VERSION 5.8 ;
BUSBITCHARS "[]" ;
DIVIDERCHAR "/" ;

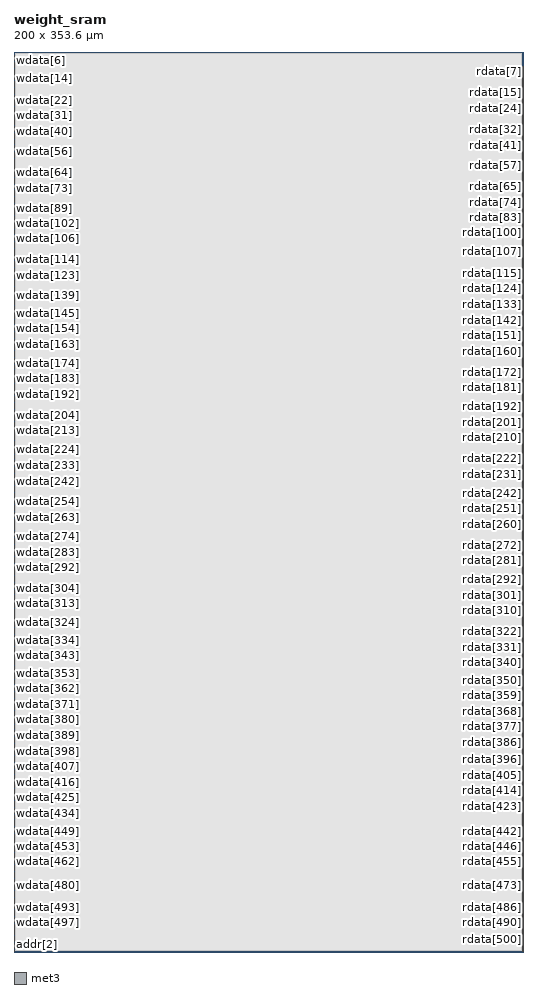
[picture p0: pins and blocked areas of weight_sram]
MACRO weight_sram
  CLASS BLOCK ;
  ORIGIN 0.000 0.000 ;
  FOREIGN weight_sram 0.000 0.000 ;
  SIZE 200.000 BY 353.600 ;
  SYMMETRY X Y ;

  PIN clk
    DIRECTION INPUT ;
    USE CLOCK ;
    PORT
      LAYER met3 ;
        RECT 0.000 0.190 0.300 0.490 ;
    END
  END clk

  PIN we
    DIRECTION INPUT ;
    USE SIGNAL ;
    PORT
      LAYER met3 ;
        RECT 0.000 0.870 0.300 1.170 ;
    END
  END we

  PIN addr[4]
    DIRECTION INPUT ;
    USE SIGNAL ;
    PORT
      LAYER met3 ;
        RECT 0.000 1.550 0.300 1.850 ;
    END
  END addr[4]

  PIN addr[3]
    DIRECTION INPUT ;
    USE SIGNAL ;
    PORT
      LAYER met3 ;
        RECT 0.000 2.230 0.300 2.530 ;
    END
  END addr[3]

  PIN addr[2]
    DIRECTION INPUT ;
    USE SIGNAL ;
    PORT
      LAYER met3 ;
        RECT 0.000 2.910 0.300 3.210 ;
    END
  END addr[2]

  PIN addr[1]
    DIRECTION INPUT ;
    USE SIGNAL ;
    PORT
      LAYER met3 ;
        RECT 0.000 3.590 0.300 3.890 ;
    END
  END addr[1]

  PIN addr[0]
    DIRECTION INPUT ;
    USE SIGNAL ;
    PORT
      LAYER met3 ;
        RECT 0.000 4.270 0.300 4.570 ;
    END
  END addr[0]

  PIN wdata[511]
    DIRECTION INPUT ;
    USE SIGNAL ;
    PORT
      LAYER met3 ;
        RECT 0.000 4.950 0.300 5.250 ;
    END
  END wdata[511]

  PIN wdata[510]
    DIRECTION INPUT ;
    USE SIGNAL ;
    PORT
      LAYER met3 ;
        RECT 0.000 5.630 0.300 5.930 ;
    END
  END wdata[510]

  PIN wdata[509]
    DIRECTION INPUT ;
    USE SIGNAL ;
    PORT
      LAYER met3 ;
        RECT 0.000 6.310 0.300 6.610 ;
    END
  END wdata[509]

  PIN wdata[508]
    DIRECTION INPUT ;
    USE SIGNAL ;
    PORT
      LAYER met3 ;
        RECT 0.000 6.990 0.300 7.290 ;
    END
  END wdata[508]

  PIN wdata[507]
    DIRECTION INPUT ;
    USE SIGNAL ;
    PORT
      LAYER met3 ;
        RECT 0.000 7.670 0.300 7.970 ;
    END
  END wdata[507]

  PIN wdata[506]
    DIRECTION INPUT ;
    USE SIGNAL ;
    PORT
      LAYER met3 ;
        RECT 0.000 8.350 0.300 8.650 ;
    END
  END wdata[506]

  PIN wdata[505]
    DIRECTION INPUT ;
    USE SIGNAL ;
    PORT
      LAYER met3 ;
        RECT 0.000 9.030 0.300 9.330 ;
    END
  END wdata[505]

  PIN wdata[504]
    DIRECTION INPUT ;
    USE SIGNAL ;
    PORT
      LAYER met3 ;
        RECT 0.000 9.710 0.300 10.010 ;
    END
  END wdata[504]

  PIN wdata[503]
    DIRECTION INPUT ;
    USE SIGNAL ;
    PORT
      LAYER met3 ;
        RECT 0.000 10.390 0.300 10.690 ;
    END
  END wdata[503]

  PIN wdata[502]
    DIRECTION INPUT ;
    USE SIGNAL ;
    PORT
      LAYER met3 ;
        RECT 0.000 11.070 0.300 11.370 ;
    END
  END wdata[502]

  PIN wdata[501]
    DIRECTION INPUT ;
    USE SIGNAL ;
    PORT
      LAYER met3 ;
        RECT 0.000 11.750 0.300 12.050 ;
    END
  END wdata[501]

  PIN wdata[500]
    DIRECTION INPUT ;
    USE SIGNAL ;
    PORT
      LAYER met3 ;
        RECT 0.000 12.430 0.300 12.730 ;
    END
  END wdata[500]

  PIN wdata[499]
    DIRECTION INPUT ;
    USE SIGNAL ;
    PORT
      LAYER met3 ;
        RECT 0.000 13.110 0.300 13.410 ;
    END
  END wdata[499]

  PIN wdata[498]
    DIRECTION INPUT ;
    USE SIGNAL ;
    PORT
      LAYER met3 ;
        RECT 0.000 13.790 0.300 14.090 ;
    END
  END wdata[498]

  PIN wdata[497]
    DIRECTION INPUT ;
    USE SIGNAL ;
    PORT
      LAYER met3 ;
        RECT 0.000 14.470 0.300 14.770 ;
    END
  END wdata[497]

  PIN wdata[496]
    DIRECTION INPUT ;
    USE SIGNAL ;
    PORT
      LAYER met3 ;
        RECT 0.000 15.150 0.300 15.450 ;
    END
  END wdata[496]

  PIN wdata[495]
    DIRECTION INPUT ;
    USE SIGNAL ;
    PORT
      LAYER met3 ;
        RECT 0.000 15.830 0.300 16.130 ;
    END
  END wdata[495]

  PIN wdata[494]
    DIRECTION INPUT ;
    USE SIGNAL ;
    PORT
      LAYER met3 ;
        RECT 0.000 16.510 0.300 16.810 ;
    END
  END wdata[494]

  PIN wdata[493]
    DIRECTION INPUT ;
    USE SIGNAL ;
    PORT
      LAYER met3 ;
        RECT 0.000 17.190 0.300 17.490 ;
    END
  END wdata[493]

  PIN wdata[492]
    DIRECTION INPUT ;
    USE SIGNAL ;
    PORT
      LAYER met3 ;
        RECT 0.000 17.870 0.300 18.170 ;
    END
  END wdata[492]

  PIN wdata[491]
    DIRECTION INPUT ;
    USE SIGNAL ;
    PORT
      LAYER met3 ;
        RECT 0.000 18.550 0.300 18.850 ;
    END
  END wdata[491]

  PIN wdata[490]
    DIRECTION INPUT ;
    USE SIGNAL ;
    PORT
      LAYER met3 ;
        RECT 0.000 19.230 0.300 19.530 ;
    END
  END wdata[490]

  PIN wdata[489]
    DIRECTION INPUT ;
    USE SIGNAL ;
    PORT
      LAYER met3 ;
        RECT 0.000 19.910 0.300 20.210 ;
    END
  END wdata[489]

  PIN wdata[488]
    DIRECTION INPUT ;
    USE SIGNAL ;
    PORT
      LAYER met3 ;
        RECT 0.000 20.590 0.300 20.890 ;
    END
  END wdata[488]

  PIN wdata[487]
    DIRECTION INPUT ;
    USE SIGNAL ;
    PORT
      LAYER met3 ;
        RECT 0.000 21.270 0.300 21.570 ;
    END
  END wdata[487]

  PIN wdata[486]
    DIRECTION INPUT ;
    USE SIGNAL ;
    PORT
      LAYER met3 ;
        RECT 0.000 21.950 0.300 22.250 ;
    END
  END wdata[486]

  PIN wdata[485]
    DIRECTION INPUT ;
    USE SIGNAL ;
    PORT
      LAYER met3 ;
        RECT 0.000 22.630 0.300 22.930 ;
    END
  END wdata[485]

  PIN wdata[484]
    DIRECTION INPUT ;
    USE SIGNAL ;
    PORT
      LAYER met3 ;
        RECT 0.000 23.310 0.300 23.610 ;
    END
  END wdata[484]

  PIN wdata[483]
    DIRECTION INPUT ;
    USE SIGNAL ;
    PORT
      LAYER met3 ;
        RECT 0.000 23.990 0.300 24.290 ;
    END
  END wdata[483]

  PIN wdata[482]
    DIRECTION INPUT ;
    USE SIGNAL ;
    PORT
      LAYER met3 ;
        RECT 0.000 24.670 0.300 24.970 ;
    END
  END wdata[482]

  PIN wdata[481]
    DIRECTION INPUT ;
    USE SIGNAL ;
    PORT
      LAYER met3 ;
        RECT 0.000 25.350 0.300 25.650 ;
    END
  END wdata[481]

  PIN wdata[480]
    DIRECTION INPUT ;
    USE SIGNAL ;
    PORT
      LAYER met3 ;
        RECT 0.000 26.030 0.300 26.330 ;
    END
  END wdata[480]

  PIN wdata[479]
    DIRECTION INPUT ;
    USE SIGNAL ;
    PORT
      LAYER met3 ;
        RECT 0.000 26.710 0.300 27.010 ;
    END
  END wdata[479]

  PIN wdata[478]
    DIRECTION INPUT ;
    USE SIGNAL ;
    PORT
      LAYER met3 ;
        RECT 0.000 27.390 0.300 27.690 ;
    END
  END wdata[478]

  PIN wdata[477]
    DIRECTION INPUT ;
    USE SIGNAL ;
    PORT
      LAYER met3 ;
        RECT 0.000 28.070 0.300 28.370 ;
    END
  END wdata[477]

  PIN wdata[476]
    DIRECTION INPUT ;
    USE SIGNAL ;
    PORT
      LAYER met3 ;
        RECT 0.000 28.750 0.300 29.050 ;
    END
  END wdata[476]

  PIN wdata[475]
    DIRECTION INPUT ;
    USE SIGNAL ;
    PORT
      LAYER met3 ;
        RECT 0.000 29.430 0.300 29.730 ;
    END
  END wdata[475]

  PIN wdata[474]
    DIRECTION INPUT ;
    USE SIGNAL ;
    PORT
      LAYER met3 ;
        RECT 0.000 30.110 0.300 30.410 ;
    END
  END wdata[474]

  PIN wdata[473]
    DIRECTION INPUT ;
    USE SIGNAL ;
    PORT
      LAYER met3 ;
        RECT 0.000 30.790 0.300 31.090 ;
    END
  END wdata[473]

  PIN wdata[472]
    DIRECTION INPUT ;
    USE SIGNAL ;
    PORT
      LAYER met3 ;
        RECT 0.000 31.470 0.300 31.770 ;
    END
  END wdata[472]

  PIN wdata[471]
    DIRECTION INPUT ;
    USE SIGNAL ;
    PORT
      LAYER met3 ;
        RECT 0.000 32.150 0.300 32.450 ;
    END
  END wdata[471]

  PIN wdata[470]
    DIRECTION INPUT ;
    USE SIGNAL ;
    PORT
      LAYER met3 ;
        RECT 0.000 32.830 0.300 33.130 ;
    END
  END wdata[470]

  PIN wdata[469]
    DIRECTION INPUT ;
    USE SIGNAL ;
    PORT
      LAYER met3 ;
        RECT 0.000 33.510 0.300 33.810 ;
    END
  END wdata[469]

  PIN wdata[468]
    DIRECTION INPUT ;
    USE SIGNAL ;
    PORT
      LAYER met3 ;
        RECT 0.000 34.190 0.300 34.490 ;
    END
  END wdata[468]

  PIN wdata[467]
    DIRECTION INPUT ;
    USE SIGNAL ;
    PORT
      LAYER met3 ;
        RECT 0.000 34.870 0.300 35.170 ;
    END
  END wdata[467]

  PIN wdata[466]
    DIRECTION INPUT ;
    USE SIGNAL ;
    PORT
      LAYER met3 ;
        RECT 0.000 35.550 0.300 35.850 ;
    END
  END wdata[466]

  PIN wdata[465]
    DIRECTION INPUT ;
    USE SIGNAL ;
    PORT
      LAYER met3 ;
        RECT 0.000 36.230 0.300 36.530 ;
    END
  END wdata[465]

  PIN wdata[464]
    DIRECTION INPUT ;
    USE SIGNAL ;
    PORT
      LAYER met3 ;
        RECT 0.000 36.910 0.300 37.210 ;
    END
  END wdata[464]

  PIN wdata[463]
    DIRECTION INPUT ;
    USE SIGNAL ;
    PORT
      LAYER met3 ;
        RECT 0.000 37.590 0.300 37.890 ;
    END
  END wdata[463]

  PIN wdata[462]
    DIRECTION INPUT ;
    USE SIGNAL ;
    PORT
      LAYER met3 ;
        RECT 0.000 38.270 0.300 38.570 ;
    END
  END wdata[462]

  PIN wdata[461]
    DIRECTION INPUT ;
    USE SIGNAL ;
    PORT
      LAYER met3 ;
        RECT 0.000 38.950 0.300 39.250 ;
    END
  END wdata[461]

  PIN wdata[460]
    DIRECTION INPUT ;
    USE SIGNAL ;
    PORT
      LAYER met3 ;
        RECT 0.000 39.630 0.300 39.930 ;
    END
  END wdata[460]

  PIN wdata[459]
    DIRECTION INPUT ;
    USE SIGNAL ;
    PORT
      LAYER met3 ;
        RECT 0.000 40.310 0.300 40.610 ;
    END
  END wdata[459]

  PIN wdata[458]
    DIRECTION INPUT ;
    USE SIGNAL ;
    PORT
      LAYER met3 ;
        RECT 0.000 40.990 0.300 41.290 ;
    END
  END wdata[458]

  PIN wdata[457]
    DIRECTION INPUT ;
    USE SIGNAL ;
    PORT
      LAYER met3 ;
        RECT 0.000 41.670 0.300 41.970 ;
    END
  END wdata[457]

  PIN wdata[456]
    DIRECTION INPUT ;
    USE SIGNAL ;
    PORT
      LAYER met3 ;
        RECT 0.000 42.350 0.300 42.650 ;
    END
  END wdata[456]

  PIN wdata[455]
    DIRECTION INPUT ;
    USE SIGNAL ;
    PORT
      LAYER met3 ;
        RECT 0.000 43.030 0.300 43.330 ;
    END
  END wdata[455]

  PIN wdata[454]
    DIRECTION INPUT ;
    USE SIGNAL ;
    PORT
      LAYER met3 ;
        RECT 0.000 43.710 0.300 44.010 ;
    END
  END wdata[454]

  PIN wdata[453]
    DIRECTION INPUT ;
    USE SIGNAL ;
    PORT
      LAYER met3 ;
        RECT 0.000 44.390 0.300 44.690 ;
    END
  END wdata[453]

  PIN wdata[452]
    DIRECTION INPUT ;
    USE SIGNAL ;
    PORT
      LAYER met3 ;
        RECT 0.000 45.070 0.300 45.370 ;
    END
  END wdata[452]

  PIN wdata[451]
    DIRECTION INPUT ;
    USE SIGNAL ;
    PORT
      LAYER met3 ;
        RECT 0.000 45.750 0.300 46.050 ;
    END
  END wdata[451]

  PIN wdata[450]
    DIRECTION INPUT ;
    USE SIGNAL ;
    PORT
      LAYER met3 ;
        RECT 0.000 46.430 0.300 46.730 ;
    END
  END wdata[450]

  PIN wdata[449]
    DIRECTION INPUT ;
    USE SIGNAL ;
    PORT
      LAYER met3 ;
        RECT 0.000 47.110 0.300 47.410 ;
    END
  END wdata[449]

  PIN wdata[448]
    DIRECTION INPUT ;
    USE SIGNAL ;
    PORT
      LAYER met3 ;
        RECT 0.000 47.790 0.300 48.090 ;
    END
  END wdata[448]

  PIN wdata[447]
    DIRECTION INPUT ;
    USE SIGNAL ;
    PORT
      LAYER met3 ;
        RECT 0.000 48.470 0.300 48.770 ;
    END
  END wdata[447]

  PIN wdata[446]
    DIRECTION INPUT ;
    USE SIGNAL ;
    PORT
      LAYER met3 ;
        RECT 0.000 49.150 0.300 49.450 ;
    END
  END wdata[446]

  PIN wdata[445]
    DIRECTION INPUT ;
    USE SIGNAL ;
    PORT
      LAYER met3 ;
        RECT 0.000 49.830 0.300 50.130 ;
    END
  END wdata[445]

  PIN wdata[444]
    DIRECTION INPUT ;
    USE SIGNAL ;
    PORT
      LAYER met3 ;
        RECT 0.000 50.510 0.300 50.810 ;
    END
  END wdata[444]

  PIN wdata[443]
    DIRECTION INPUT ;
    USE SIGNAL ;
    PORT
      LAYER met3 ;
        RECT 0.000 51.190 0.300 51.490 ;
    END
  END wdata[443]

  PIN wdata[442]
    DIRECTION INPUT ;
    USE SIGNAL ;
    PORT
      LAYER met3 ;
        RECT 0.000 51.870 0.300 52.170 ;
    END
  END wdata[442]

  PIN wdata[441]
    DIRECTION INPUT ;
    USE SIGNAL ;
    PORT
      LAYER met3 ;
        RECT 0.000 52.550 0.300 52.850 ;
    END
  END wdata[441]

  PIN wdata[440]
    DIRECTION INPUT ;
    USE SIGNAL ;
    PORT
      LAYER met3 ;
        RECT 0.000 53.230 0.300 53.530 ;
    END
  END wdata[440]

  PIN wdata[439]
    DIRECTION INPUT ;
    USE SIGNAL ;
    PORT
      LAYER met3 ;
        RECT 0.000 53.910 0.300 54.210 ;
    END
  END wdata[439]

  PIN wdata[438]
    DIRECTION INPUT ;
    USE SIGNAL ;
    PORT
      LAYER met3 ;
        RECT 0.000 54.590 0.300 54.890 ;
    END
  END wdata[438]

  PIN wdata[437]
    DIRECTION INPUT ;
    USE SIGNAL ;
    PORT
      LAYER met3 ;
        RECT 0.000 55.270 0.300 55.570 ;
    END
  END wdata[437]

  PIN wdata[436]
    DIRECTION INPUT ;
    USE SIGNAL ;
    PORT
      LAYER met3 ;
        RECT 0.000 55.950 0.300 56.250 ;
    END
  END wdata[436]

  PIN wdata[435]
    DIRECTION INPUT ;
    USE SIGNAL ;
    PORT
      LAYER met3 ;
        RECT 0.000 56.630 0.300 56.930 ;
    END
  END wdata[435]

  PIN wdata[434]
    DIRECTION INPUT ;
    USE SIGNAL ;
    PORT
      LAYER met3 ;
        RECT 0.000 57.310 0.300 57.610 ;
    END
  END wdata[434]

  PIN wdata[433]
    DIRECTION INPUT ;
    USE SIGNAL ;
    PORT
      LAYER met3 ;
        RECT 0.000 57.990 0.300 58.290 ;
    END
  END wdata[433]

  PIN wdata[432]
    DIRECTION INPUT ;
    USE SIGNAL ;
    PORT
      LAYER met3 ;
        RECT 0.000 58.670 0.300 58.970 ;
    END
  END wdata[432]

  PIN wdata[431]
    DIRECTION INPUT ;
    USE SIGNAL ;
    PORT
      LAYER met3 ;
        RECT 0.000 59.350 0.300 59.650 ;
    END
  END wdata[431]

  PIN wdata[430]
    DIRECTION INPUT ;
    USE SIGNAL ;
    PORT
      LAYER met3 ;
        RECT 0.000 60.030 0.300 60.330 ;
    END
  END wdata[430]

  PIN wdata[429]
    DIRECTION INPUT ;
    USE SIGNAL ;
    PORT
      LAYER met3 ;
        RECT 0.000 60.710 0.300 61.010 ;
    END
  END wdata[429]

  PIN wdata[428]
    DIRECTION INPUT ;
    USE SIGNAL ;
    PORT
      LAYER met3 ;
        RECT 0.000 61.390 0.300 61.690 ;
    END
  END wdata[428]

  PIN wdata[427]
    DIRECTION INPUT ;
    USE SIGNAL ;
    PORT
      LAYER met3 ;
        RECT 0.000 62.070 0.300 62.370 ;
    END
  END wdata[427]

  PIN wdata[426]
    DIRECTION INPUT ;
    USE SIGNAL ;
    PORT
      LAYER met3 ;
        RECT 0.000 62.750 0.300 63.050 ;
    END
  END wdata[426]

  PIN wdata[425]
    DIRECTION INPUT ;
    USE SIGNAL ;
    PORT
      LAYER met3 ;
        RECT 0.000 63.430 0.300 63.730 ;
    END
  END wdata[425]

  PIN wdata[424]
    DIRECTION INPUT ;
    USE SIGNAL ;
    PORT
      LAYER met3 ;
        RECT 0.000 64.110 0.300 64.410 ;
    END
  END wdata[424]

  PIN wdata[423]
    DIRECTION INPUT ;
    USE SIGNAL ;
    PORT
      LAYER met3 ;
        RECT 0.000 64.790 0.300 65.090 ;
    END
  END wdata[423]

  PIN wdata[422]
    DIRECTION INPUT ;
    USE SIGNAL ;
    PORT
      LAYER met3 ;
        RECT 0.000 65.470 0.300 65.770 ;
    END
  END wdata[422]

  PIN wdata[421]
    DIRECTION INPUT ;
    USE SIGNAL ;
    PORT
      LAYER met3 ;
        RECT 0.000 66.150 0.300 66.450 ;
    END
  END wdata[421]

  PIN wdata[420]
    DIRECTION INPUT ;
    USE SIGNAL ;
    PORT
      LAYER met3 ;
        RECT 0.000 66.830 0.300 67.130 ;
    END
  END wdata[420]

  PIN wdata[419]
    DIRECTION INPUT ;
    USE SIGNAL ;
    PORT
      LAYER met3 ;
        RECT 0.000 67.510 0.300 67.810 ;
    END
  END wdata[419]

  PIN wdata[418]
    DIRECTION INPUT ;
    USE SIGNAL ;
    PORT
      LAYER met3 ;
        RECT 0.000 68.190 0.300 68.490 ;
    END
  END wdata[418]

  PIN wdata[417]
    DIRECTION INPUT ;
    USE SIGNAL ;
    PORT
      LAYER met3 ;
        RECT 0.000 68.870 0.300 69.170 ;
    END
  END wdata[417]

  PIN wdata[416]
    DIRECTION INPUT ;
    USE SIGNAL ;
    PORT
      LAYER met3 ;
        RECT 0.000 69.550 0.300 69.850 ;
    END
  END wdata[416]

  PIN wdata[415]
    DIRECTION INPUT ;
    USE SIGNAL ;
    PORT
      LAYER met3 ;
        RECT 0.000 70.230 0.300 70.530 ;
    END
  END wdata[415]

  PIN wdata[414]
    DIRECTION INPUT ;
    USE SIGNAL ;
    PORT
      LAYER met3 ;
        RECT 0.000 70.910 0.300 71.210 ;
    END
  END wdata[414]

  PIN wdata[413]
    DIRECTION INPUT ;
    USE SIGNAL ;
    PORT
      LAYER met3 ;
        RECT 0.000 71.590 0.300 71.890 ;
    END
  END wdata[413]

  PIN wdata[412]
    DIRECTION INPUT ;
    USE SIGNAL ;
    PORT
      LAYER met3 ;
        RECT 0.000 72.270 0.300 72.570 ;
    END
  END wdata[412]

  PIN wdata[411]
    DIRECTION INPUT ;
    USE SIGNAL ;
    PORT
      LAYER met3 ;
        RECT 0.000 72.950 0.300 73.250 ;
    END
  END wdata[411]

  PIN wdata[410]
    DIRECTION INPUT ;
    USE SIGNAL ;
    PORT
      LAYER met3 ;
        RECT 0.000 73.630 0.300 73.930 ;
    END
  END wdata[410]

  PIN wdata[409]
    DIRECTION INPUT ;
    USE SIGNAL ;
    PORT
      LAYER met3 ;
        RECT 0.000 74.310 0.300 74.610 ;
    END
  END wdata[409]

  PIN wdata[408]
    DIRECTION INPUT ;
    USE SIGNAL ;
    PORT
      LAYER met3 ;
        RECT 0.000 74.990 0.300 75.290 ;
    END
  END wdata[408]

  PIN wdata[407]
    DIRECTION INPUT ;
    USE SIGNAL ;
    PORT
      LAYER met3 ;
        RECT 0.000 75.670 0.300 75.970 ;
    END
  END wdata[407]

  PIN wdata[406]
    DIRECTION INPUT ;
    USE SIGNAL ;
    PORT
      LAYER met3 ;
        RECT 0.000 76.350 0.300 76.650 ;
    END
  END wdata[406]

  PIN wdata[405]
    DIRECTION INPUT ;
    USE SIGNAL ;
    PORT
      LAYER met3 ;
        RECT 0.000 77.030 0.300 77.330 ;
    END
  END wdata[405]

  PIN wdata[404]
    DIRECTION INPUT ;
    USE SIGNAL ;
    PORT
      LAYER met3 ;
        RECT 0.000 77.710 0.300 78.010 ;
    END
  END wdata[404]

  PIN wdata[403]
    DIRECTION INPUT ;
    USE SIGNAL ;
    PORT
      LAYER met3 ;
        RECT 0.000 78.390 0.300 78.690 ;
    END
  END wdata[403]

  PIN wdata[402]
    DIRECTION INPUT ;
    USE SIGNAL ;
    PORT
      LAYER met3 ;
        RECT 0.000 79.070 0.300 79.370 ;
    END
  END wdata[402]

  PIN wdata[401]
    DIRECTION INPUT ;
    USE SIGNAL ;
    PORT
      LAYER met3 ;
        RECT 0.000 79.750 0.300 80.050 ;
    END
  END wdata[401]

  PIN wdata[400]
    DIRECTION INPUT ;
    USE SIGNAL ;
    PORT
      LAYER met3 ;
        RECT 0.000 80.430 0.300 80.730 ;
    END
  END wdata[400]

  PIN wdata[399]
    DIRECTION INPUT ;
    USE SIGNAL ;
    PORT
      LAYER met3 ;
        RECT 0.000 81.110 0.300 81.410 ;
    END
  END wdata[399]

  PIN wdata[398]
    DIRECTION INPUT ;
    USE SIGNAL ;
    PORT
      LAYER met3 ;
        RECT 0.000 81.790 0.300 82.090 ;
    END
  END wdata[398]

  PIN wdata[397]
    DIRECTION INPUT ;
    USE SIGNAL ;
    PORT
      LAYER met3 ;
        RECT 0.000 82.470 0.300 82.770 ;
    END
  END wdata[397]

  PIN wdata[396]
    DIRECTION INPUT ;
    USE SIGNAL ;
    PORT
      LAYER met3 ;
        RECT 0.000 83.150 0.300 83.450 ;
    END
  END wdata[396]

  PIN wdata[395]
    DIRECTION INPUT ;
    USE SIGNAL ;
    PORT
      LAYER met3 ;
        RECT 0.000 83.830 0.300 84.130 ;
    END
  END wdata[395]

  PIN wdata[394]
    DIRECTION INPUT ;
    USE SIGNAL ;
    PORT
      LAYER met3 ;
        RECT 0.000 84.510 0.300 84.810 ;
    END
  END wdata[394]

  PIN wdata[393]
    DIRECTION INPUT ;
    USE SIGNAL ;
    PORT
      LAYER met3 ;
        RECT 0.000 85.190 0.300 85.490 ;
    END
  END wdata[393]

  PIN wdata[392]
    DIRECTION INPUT ;
    USE SIGNAL ;
    PORT
      LAYER met3 ;
        RECT 0.000 85.870 0.300 86.170 ;
    END
  END wdata[392]

  PIN wdata[391]
    DIRECTION INPUT ;
    USE SIGNAL ;
    PORT
      LAYER met3 ;
        RECT 0.000 86.550 0.300 86.850 ;
    END
  END wdata[391]

  PIN wdata[390]
    DIRECTION INPUT ;
    USE SIGNAL ;
    PORT
      LAYER met3 ;
        RECT 0.000 87.230 0.300 87.530 ;
    END
  END wdata[390]

  PIN wdata[389]
    DIRECTION INPUT ;
    USE SIGNAL ;
    PORT
      LAYER met3 ;
        RECT 0.000 87.910 0.300 88.210 ;
    END
  END wdata[389]

  PIN wdata[388]
    DIRECTION INPUT ;
    USE SIGNAL ;
    PORT
      LAYER met3 ;
        RECT 0.000 88.590 0.300 88.890 ;
    END
  END wdata[388]

  PIN wdata[387]
    DIRECTION INPUT ;
    USE SIGNAL ;
    PORT
      LAYER met3 ;
        RECT 0.000 89.270 0.300 89.570 ;
    END
  END wdata[387]

  PIN wdata[386]
    DIRECTION INPUT ;
    USE SIGNAL ;
    PORT
      LAYER met3 ;
        RECT 0.000 89.950 0.300 90.250 ;
    END
  END wdata[386]

  PIN wdata[385]
    DIRECTION INPUT ;
    USE SIGNAL ;
    PORT
      LAYER met3 ;
        RECT 0.000 90.630 0.300 90.930 ;
    END
  END wdata[385]

  PIN wdata[384]
    DIRECTION INPUT ;
    USE SIGNAL ;
    PORT
      LAYER met3 ;
        RECT 0.000 91.310 0.300 91.610 ;
    END
  END wdata[384]

  PIN wdata[383]
    DIRECTION INPUT ;
    USE SIGNAL ;
    PORT
      LAYER met3 ;
        RECT 0.000 91.990 0.300 92.290 ;
    END
  END wdata[383]

  PIN wdata[382]
    DIRECTION INPUT ;
    USE SIGNAL ;
    PORT
      LAYER met3 ;
        RECT 0.000 92.670 0.300 92.970 ;
    END
  END wdata[382]

  PIN wdata[381]
    DIRECTION INPUT ;
    USE SIGNAL ;
    PORT
      LAYER met3 ;
        RECT 0.000 93.350 0.300 93.650 ;
    END
  END wdata[381]

  PIN wdata[380]
    DIRECTION INPUT ;
    USE SIGNAL ;
    PORT
      LAYER met3 ;
        RECT 0.000 94.030 0.300 94.330 ;
    END
  END wdata[380]

  PIN wdata[379]
    DIRECTION INPUT ;
    USE SIGNAL ;
    PORT
      LAYER met3 ;
        RECT 0.000 94.710 0.300 95.010 ;
    END
  END wdata[379]

  PIN wdata[378]
    DIRECTION INPUT ;
    USE SIGNAL ;
    PORT
      LAYER met3 ;
        RECT 0.000 95.390 0.300 95.690 ;
    END
  END wdata[378]

  PIN wdata[377]
    DIRECTION INPUT ;
    USE SIGNAL ;
    PORT
      LAYER met3 ;
        RECT 0.000 96.070 0.300 96.370 ;
    END
  END wdata[377]

  PIN wdata[376]
    DIRECTION INPUT ;
    USE SIGNAL ;
    PORT
      LAYER met3 ;
        RECT 0.000 96.750 0.300 97.050 ;
    END
  END wdata[376]

  PIN wdata[375]
    DIRECTION INPUT ;
    USE SIGNAL ;
    PORT
      LAYER met3 ;
        RECT 0.000 97.430 0.300 97.730 ;
    END
  END wdata[375]

  PIN wdata[374]
    DIRECTION INPUT ;
    USE SIGNAL ;
    PORT
      LAYER met3 ;
        RECT 0.000 98.110 0.300 98.410 ;
    END
  END wdata[374]

  PIN wdata[373]
    DIRECTION INPUT ;
    USE SIGNAL ;
    PORT
      LAYER met3 ;
        RECT 0.000 98.790 0.300 99.090 ;
    END
  END wdata[373]

  PIN wdata[372]
    DIRECTION INPUT ;
    USE SIGNAL ;
    PORT
      LAYER met3 ;
        RECT 0.000 99.470 0.300 99.770 ;
    END
  END wdata[372]

  PIN wdata[371]
    DIRECTION INPUT ;
    USE SIGNAL ;
    PORT
      LAYER met3 ;
        RECT 0.000 100.150 0.300 100.450 ;
    END
  END wdata[371]

  PIN wdata[370]
    DIRECTION INPUT ;
    USE SIGNAL ;
    PORT
      LAYER met3 ;
        RECT 0.000 100.830 0.300 101.130 ;
    END
  END wdata[370]

  PIN wdata[369]
    DIRECTION INPUT ;
    USE SIGNAL ;
    PORT
      LAYER met3 ;
        RECT 0.000 101.510 0.300 101.810 ;
    END
  END wdata[369]

  PIN wdata[368]
    DIRECTION INPUT ;
    USE SIGNAL ;
    PORT
      LAYER met3 ;
        RECT 0.000 102.190 0.300 102.490 ;
    END
  END wdata[368]

  PIN wdata[367]
    DIRECTION INPUT ;
    USE SIGNAL ;
    PORT
      LAYER met3 ;
        RECT 0.000 102.870 0.300 103.170 ;
    END
  END wdata[367]

  PIN wdata[366]
    DIRECTION INPUT ;
    USE SIGNAL ;
    PORT
      LAYER met3 ;
        RECT 0.000 103.550 0.300 103.850 ;
    END
  END wdata[366]

  PIN wdata[365]
    DIRECTION INPUT ;
    USE SIGNAL ;
    PORT
      LAYER met3 ;
        RECT 0.000 104.230 0.300 104.530 ;
    END
  END wdata[365]

  PIN wdata[364]
    DIRECTION INPUT ;
    USE SIGNAL ;
    PORT
      LAYER met3 ;
        RECT 0.000 104.910 0.300 105.210 ;
    END
  END wdata[364]

  PIN wdata[363]
    DIRECTION INPUT ;
    USE SIGNAL ;
    PORT
      LAYER met3 ;
        RECT 0.000 105.590 0.300 105.890 ;
    END
  END wdata[363]

  PIN wdata[362]
    DIRECTION INPUT ;
    USE SIGNAL ;
    PORT
      LAYER met3 ;
        RECT 0.000 106.270 0.300 106.570 ;
    END
  END wdata[362]

  PIN wdata[361]
    DIRECTION INPUT ;
    USE SIGNAL ;
    PORT
      LAYER met3 ;
        RECT 0.000 106.950 0.300 107.250 ;
    END
  END wdata[361]

  PIN wdata[360]
    DIRECTION INPUT ;
    USE SIGNAL ;
    PORT
      LAYER met3 ;
        RECT 0.000 107.630 0.300 107.930 ;
    END
  END wdata[360]

  PIN wdata[359]
    DIRECTION INPUT ;
    USE SIGNAL ;
    PORT
      LAYER met3 ;
        RECT 0.000 108.310 0.300 108.610 ;
    END
  END wdata[359]

  PIN wdata[358]
    DIRECTION INPUT ;
    USE SIGNAL ;
    PORT
      LAYER met3 ;
        RECT 0.000 108.990 0.300 109.290 ;
    END
  END wdata[358]

  PIN wdata[357]
    DIRECTION INPUT ;
    USE SIGNAL ;
    PORT
      LAYER met3 ;
        RECT 0.000 109.670 0.300 109.970 ;
    END
  END wdata[357]

  PIN wdata[356]
    DIRECTION INPUT ;
    USE SIGNAL ;
    PORT
      LAYER met3 ;
        RECT 0.000 110.350 0.300 110.650 ;
    END
  END wdata[356]

  PIN wdata[355]
    DIRECTION INPUT ;
    USE SIGNAL ;
    PORT
      LAYER met3 ;
        RECT 0.000 111.030 0.300 111.330 ;
    END
  END wdata[355]

  PIN wdata[354]
    DIRECTION INPUT ;
    USE SIGNAL ;
    PORT
      LAYER met3 ;
        RECT 0.000 111.710 0.300 112.010 ;
    END
  END wdata[354]

  PIN wdata[353]
    DIRECTION INPUT ;
    USE SIGNAL ;
    PORT
      LAYER met3 ;
        RECT 0.000 112.390 0.300 112.690 ;
    END
  END wdata[353]

  PIN wdata[352]
    DIRECTION INPUT ;
    USE SIGNAL ;
    PORT
      LAYER met3 ;
        RECT 0.000 113.070 0.300 113.370 ;
    END
  END wdata[352]

  PIN wdata[351]
    DIRECTION INPUT ;
    USE SIGNAL ;
    PORT
      LAYER met3 ;
        RECT 0.000 113.750 0.300 114.050 ;
    END
  END wdata[351]

  PIN wdata[350]
    DIRECTION INPUT ;
    USE SIGNAL ;
    PORT
      LAYER met3 ;
        RECT 0.000 114.430 0.300 114.730 ;
    END
  END wdata[350]

  PIN wdata[349]
    DIRECTION INPUT ;
    USE SIGNAL ;
    PORT
      LAYER met3 ;
        RECT 0.000 115.110 0.300 115.410 ;
    END
  END wdata[349]

  PIN wdata[348]
    DIRECTION INPUT ;
    USE SIGNAL ;
    PORT
      LAYER met3 ;
        RECT 0.000 115.790 0.300 116.090 ;
    END
  END wdata[348]

  PIN wdata[347]
    DIRECTION INPUT ;
    USE SIGNAL ;
    PORT
      LAYER met3 ;
        RECT 0.000 116.470 0.300 116.770 ;
    END
  END wdata[347]

  PIN wdata[346]
    DIRECTION INPUT ;
    USE SIGNAL ;
    PORT
      LAYER met3 ;
        RECT 0.000 117.150 0.300 117.450 ;
    END
  END wdata[346]

  PIN wdata[345]
    DIRECTION INPUT ;
    USE SIGNAL ;
    PORT
      LAYER met3 ;
        RECT 0.000 117.830 0.300 118.130 ;
    END
  END wdata[345]

  PIN wdata[344]
    DIRECTION INPUT ;
    USE SIGNAL ;
    PORT
      LAYER met3 ;
        RECT 0.000 118.510 0.300 118.810 ;
    END
  END wdata[344]

  PIN wdata[343]
    DIRECTION INPUT ;
    USE SIGNAL ;
    PORT
      LAYER met3 ;
        RECT 0.000 119.190 0.300 119.490 ;
    END
  END wdata[343]

  PIN wdata[342]
    DIRECTION INPUT ;
    USE SIGNAL ;
    PORT
      LAYER met3 ;
        RECT 0.000 119.870 0.300 120.170 ;
    END
  END wdata[342]

  PIN wdata[341]
    DIRECTION INPUT ;
    USE SIGNAL ;
    PORT
      LAYER met3 ;
        RECT 0.000 120.550 0.300 120.850 ;
    END
  END wdata[341]

  PIN wdata[340]
    DIRECTION INPUT ;
    USE SIGNAL ;
    PORT
      LAYER met3 ;
        RECT 0.000 121.230 0.300 121.530 ;
    END
  END wdata[340]

  PIN wdata[339]
    DIRECTION INPUT ;
    USE SIGNAL ;
    PORT
      LAYER met3 ;
        RECT 0.000 121.910 0.300 122.210 ;
    END
  END wdata[339]

  PIN wdata[338]
    DIRECTION INPUT ;
    USE SIGNAL ;
    PORT
      LAYER met3 ;
        RECT 0.000 122.590 0.300 122.890 ;
    END
  END wdata[338]

  PIN wdata[337]
    DIRECTION INPUT ;
    USE SIGNAL ;
    PORT
      LAYER met3 ;
        RECT 0.000 123.270 0.300 123.570 ;
    END
  END wdata[337]

  PIN wdata[336]
    DIRECTION INPUT ;
    USE SIGNAL ;
    PORT
      LAYER met3 ;
        RECT 0.000 123.950 0.300 124.250 ;
    END
  END wdata[336]

  PIN wdata[335]
    DIRECTION INPUT ;
    USE SIGNAL ;
    PORT
      LAYER met3 ;
        RECT 0.000 124.630 0.300 124.930 ;
    END
  END wdata[335]

  PIN wdata[334]
    DIRECTION INPUT ;
    USE SIGNAL ;
    PORT
      LAYER met3 ;
        RECT 0.000 125.310 0.300 125.610 ;
    END
  END wdata[334]

  PIN wdata[333]
    DIRECTION INPUT ;
    USE SIGNAL ;
    PORT
      LAYER met3 ;
        RECT 0.000 125.990 0.300 126.290 ;
    END
  END wdata[333]

  PIN wdata[332]
    DIRECTION INPUT ;
    USE SIGNAL ;
    PORT
      LAYER met3 ;
        RECT 0.000 126.670 0.300 126.970 ;
    END
  END wdata[332]

  PIN wdata[331]
    DIRECTION INPUT ;
    USE SIGNAL ;
    PORT
      LAYER met3 ;
        RECT 0.000 127.350 0.300 127.650 ;
    END
  END wdata[331]

  PIN wdata[330]
    DIRECTION INPUT ;
    USE SIGNAL ;
    PORT
      LAYER met3 ;
        RECT 0.000 128.030 0.300 128.330 ;
    END
  END wdata[330]

  PIN wdata[329]
    DIRECTION INPUT ;
    USE SIGNAL ;
    PORT
      LAYER met3 ;
        RECT 0.000 128.710 0.300 129.010 ;
    END
  END wdata[329]

  PIN wdata[328]
    DIRECTION INPUT ;
    USE SIGNAL ;
    PORT
      LAYER met3 ;
        RECT 0.000 129.390 0.300 129.690 ;
    END
  END wdata[328]

  PIN wdata[327]
    DIRECTION INPUT ;
    USE SIGNAL ;
    PORT
      LAYER met3 ;
        RECT 0.000 130.070 0.300 130.370 ;
    END
  END wdata[327]

  PIN wdata[326]
    DIRECTION INPUT ;
    USE SIGNAL ;
    PORT
      LAYER met3 ;
        RECT 0.000 130.750 0.300 131.050 ;
    END
  END wdata[326]

  PIN wdata[325]
    DIRECTION INPUT ;
    USE SIGNAL ;
    PORT
      LAYER met3 ;
        RECT 0.000 131.430 0.300 131.730 ;
    END
  END wdata[325]

  PIN wdata[324]
    DIRECTION INPUT ;
    USE SIGNAL ;
    PORT
      LAYER met3 ;
        RECT 0.000 132.110 0.300 132.410 ;
    END
  END wdata[324]

  PIN wdata[323]
    DIRECTION INPUT ;
    USE SIGNAL ;
    PORT
      LAYER met3 ;
        RECT 0.000 132.790 0.300 133.090 ;
    END
  END wdata[323]

  PIN wdata[322]
    DIRECTION INPUT ;
    USE SIGNAL ;
    PORT
      LAYER met3 ;
        RECT 0.000 133.470 0.300 133.770 ;
    END
  END wdata[322]

  PIN wdata[321]
    DIRECTION INPUT ;
    USE SIGNAL ;
    PORT
      LAYER met3 ;
        RECT 0.000 134.150 0.300 134.450 ;
    END
  END wdata[321]

  PIN wdata[320]
    DIRECTION INPUT ;
    USE SIGNAL ;
    PORT
      LAYER met3 ;
        RECT 0.000 134.830 0.300 135.130 ;
    END
  END wdata[320]

  PIN wdata[319]
    DIRECTION INPUT ;
    USE SIGNAL ;
    PORT
      LAYER met3 ;
        RECT 0.000 135.510 0.300 135.810 ;
    END
  END wdata[319]

  PIN wdata[318]
    DIRECTION INPUT ;
    USE SIGNAL ;
    PORT
      LAYER met3 ;
        RECT 0.000 136.190 0.300 136.490 ;
    END
  END wdata[318]

  PIN wdata[317]
    DIRECTION INPUT ;
    USE SIGNAL ;
    PORT
      LAYER met3 ;
        RECT 0.000 136.870 0.300 137.170 ;
    END
  END wdata[317]

  PIN wdata[316]
    DIRECTION INPUT ;
    USE SIGNAL ;
    PORT
      LAYER met3 ;
        RECT 0.000 137.550 0.300 137.850 ;
    END
  END wdata[316]

  PIN wdata[315]
    DIRECTION INPUT ;
    USE SIGNAL ;
    PORT
      LAYER met3 ;
        RECT 0.000 138.230 0.300 138.530 ;
    END
  END wdata[315]

  PIN wdata[314]
    DIRECTION INPUT ;
    USE SIGNAL ;
    PORT
      LAYER met3 ;
        RECT 0.000 138.910 0.300 139.210 ;
    END
  END wdata[314]

  PIN wdata[313]
    DIRECTION INPUT ;
    USE SIGNAL ;
    PORT
      LAYER met3 ;
        RECT 0.000 139.590 0.300 139.890 ;
    END
  END wdata[313]

  PIN wdata[312]
    DIRECTION INPUT ;
    USE SIGNAL ;
    PORT
      LAYER met3 ;
        RECT 0.000 140.270 0.300 140.570 ;
    END
  END wdata[312]

  PIN wdata[311]
    DIRECTION INPUT ;
    USE SIGNAL ;
    PORT
      LAYER met3 ;
        RECT 0.000 140.950 0.300 141.250 ;
    END
  END wdata[311]

  PIN wdata[310]
    DIRECTION INPUT ;
    USE SIGNAL ;
    PORT
      LAYER met3 ;
        RECT 0.000 141.630 0.300 141.930 ;
    END
  END wdata[310]

  PIN wdata[309]
    DIRECTION INPUT ;
    USE SIGNAL ;
    PORT
      LAYER met3 ;
        RECT 0.000 142.310 0.300 142.610 ;
    END
  END wdata[309]

  PIN wdata[308]
    DIRECTION INPUT ;
    USE SIGNAL ;
    PORT
      LAYER met3 ;
        RECT 0.000 142.990 0.300 143.290 ;
    END
  END wdata[308]

  PIN wdata[307]
    DIRECTION INPUT ;
    USE SIGNAL ;
    PORT
      LAYER met3 ;
        RECT 0.000 143.670 0.300 143.970 ;
    END
  END wdata[307]

  PIN wdata[306]
    DIRECTION INPUT ;
    USE SIGNAL ;
    PORT
      LAYER met3 ;
        RECT 0.000 144.350 0.300 144.650 ;
    END
  END wdata[306]

  PIN wdata[305]
    DIRECTION INPUT ;
    USE SIGNAL ;
    PORT
      LAYER met3 ;
        RECT 0.000 145.030 0.300 145.330 ;
    END
  END wdata[305]

  PIN wdata[304]
    DIRECTION INPUT ;
    USE SIGNAL ;
    PORT
      LAYER met3 ;
        RECT 0.000 145.710 0.300 146.010 ;
    END
  END wdata[304]

  PIN wdata[303]
    DIRECTION INPUT ;
    USE SIGNAL ;
    PORT
      LAYER met3 ;
        RECT 0.000 146.390 0.300 146.690 ;
    END
  END wdata[303]

  PIN wdata[302]
    DIRECTION INPUT ;
    USE SIGNAL ;
    PORT
      LAYER met3 ;
        RECT 0.000 147.070 0.300 147.370 ;
    END
  END wdata[302]

  PIN wdata[301]
    DIRECTION INPUT ;
    USE SIGNAL ;
    PORT
      LAYER met3 ;
        RECT 0.000 147.750 0.300 148.050 ;
    END
  END wdata[301]

  PIN wdata[300]
    DIRECTION INPUT ;
    USE SIGNAL ;
    PORT
      LAYER met3 ;
        RECT 0.000 148.430 0.300 148.730 ;
    END
  END wdata[300]

  PIN wdata[299]
    DIRECTION INPUT ;
    USE SIGNAL ;
    PORT
      LAYER met3 ;
        RECT 0.000 149.110 0.300 149.410 ;
    END
  END wdata[299]

  PIN wdata[298]
    DIRECTION INPUT ;
    USE SIGNAL ;
    PORT
      LAYER met3 ;
        RECT 0.000 149.790 0.300 150.090 ;
    END
  END wdata[298]

  PIN wdata[297]
    DIRECTION INPUT ;
    USE SIGNAL ;
    PORT
      LAYER met3 ;
        RECT 0.000 150.470 0.300 150.770 ;
    END
  END wdata[297]

  PIN wdata[296]
    DIRECTION INPUT ;
    USE SIGNAL ;
    PORT
      LAYER met3 ;
        RECT 0.000 151.150 0.300 151.450 ;
    END
  END wdata[296]

  PIN wdata[295]
    DIRECTION INPUT ;
    USE SIGNAL ;
    PORT
      LAYER met3 ;
        RECT 0.000 151.830 0.300 152.130 ;
    END
  END wdata[295]

  PIN wdata[294]
    DIRECTION INPUT ;
    USE SIGNAL ;
    PORT
      LAYER met3 ;
        RECT 0.000 152.510 0.300 152.810 ;
    END
  END wdata[294]

  PIN wdata[293]
    DIRECTION INPUT ;
    USE SIGNAL ;
    PORT
      LAYER met3 ;
        RECT 0.000 153.190 0.300 153.490 ;
    END
  END wdata[293]

  PIN wdata[292]
    DIRECTION INPUT ;
    USE SIGNAL ;
    PORT
      LAYER met3 ;
        RECT 0.000 153.870 0.300 154.170 ;
    END
  END wdata[292]

  PIN wdata[291]
    DIRECTION INPUT ;
    USE SIGNAL ;
    PORT
      LAYER met3 ;
        RECT 0.000 154.550 0.300 154.850 ;
    END
  END wdata[291]

  PIN wdata[290]
    DIRECTION INPUT ;
    USE SIGNAL ;
    PORT
      LAYER met3 ;
        RECT 0.000 155.230 0.300 155.530 ;
    END
  END wdata[290]

  PIN wdata[289]
    DIRECTION INPUT ;
    USE SIGNAL ;
    PORT
      LAYER met3 ;
        RECT 0.000 155.910 0.300 156.210 ;
    END
  END wdata[289]

  PIN wdata[288]
    DIRECTION INPUT ;
    USE SIGNAL ;
    PORT
      LAYER met3 ;
        RECT 0.000 156.590 0.300 156.890 ;
    END
  END wdata[288]

  PIN wdata[287]
    DIRECTION INPUT ;
    USE SIGNAL ;
    PORT
      LAYER met3 ;
        RECT 0.000 157.270 0.300 157.570 ;
    END
  END wdata[287]

  PIN wdata[286]
    DIRECTION INPUT ;
    USE SIGNAL ;
    PORT
      LAYER met3 ;
        RECT 0.000 157.950 0.300 158.250 ;
    END
  END wdata[286]

  PIN wdata[285]
    DIRECTION INPUT ;
    USE SIGNAL ;
    PORT
      LAYER met3 ;
        RECT 0.000 158.630 0.300 158.930 ;
    END
  END wdata[285]

  PIN wdata[284]
    DIRECTION INPUT ;
    USE SIGNAL ;
    PORT
      LAYER met3 ;
        RECT 0.000 159.310 0.300 159.610 ;
    END
  END wdata[284]

  PIN wdata[283]
    DIRECTION INPUT ;
    USE SIGNAL ;
    PORT
      LAYER met3 ;
        RECT 0.000 159.990 0.300 160.290 ;
    END
  END wdata[283]

  PIN wdata[282]
    DIRECTION INPUT ;
    USE SIGNAL ;
    PORT
      LAYER met3 ;
        RECT 0.000 160.670 0.300 160.970 ;
    END
  END wdata[282]

  PIN wdata[281]
    DIRECTION INPUT ;
    USE SIGNAL ;
    PORT
      LAYER met3 ;
        RECT 0.000 161.350 0.300 161.650 ;
    END
  END wdata[281]

  PIN wdata[280]
    DIRECTION INPUT ;
    USE SIGNAL ;
    PORT
      LAYER met3 ;
        RECT 0.000 162.030 0.300 162.330 ;
    END
  END wdata[280]

  PIN wdata[279]
    DIRECTION INPUT ;
    USE SIGNAL ;
    PORT
      LAYER met3 ;
        RECT 0.000 162.710 0.300 163.010 ;
    END
  END wdata[279]

  PIN wdata[278]
    DIRECTION INPUT ;
    USE SIGNAL ;
    PORT
      LAYER met3 ;
        RECT 0.000 163.390 0.300 163.690 ;
    END
  END wdata[278]

  PIN wdata[277]
    DIRECTION INPUT ;
    USE SIGNAL ;
    PORT
      LAYER met3 ;
        RECT 0.000 164.070 0.300 164.370 ;
    END
  END wdata[277]

  PIN wdata[276]
    DIRECTION INPUT ;
    USE SIGNAL ;
    PORT
      LAYER met3 ;
        RECT 0.000 164.750 0.300 165.050 ;
    END
  END wdata[276]

  PIN wdata[275]
    DIRECTION INPUT ;
    USE SIGNAL ;
    PORT
      LAYER met3 ;
        RECT 0.000 165.430 0.300 165.730 ;
    END
  END wdata[275]

  PIN wdata[274]
    DIRECTION INPUT ;
    USE SIGNAL ;
    PORT
      LAYER met3 ;
        RECT 0.000 166.110 0.300 166.410 ;
    END
  END wdata[274]

  PIN wdata[273]
    DIRECTION INPUT ;
    USE SIGNAL ;
    PORT
      LAYER met3 ;
        RECT 0.000 166.790 0.300 167.090 ;
    END
  END wdata[273]

  PIN wdata[272]
    DIRECTION INPUT ;
    USE SIGNAL ;
    PORT
      LAYER met3 ;
        RECT 0.000 167.470 0.300 167.770 ;
    END
  END wdata[272]

  PIN wdata[271]
    DIRECTION INPUT ;
    USE SIGNAL ;
    PORT
      LAYER met3 ;
        RECT 0.000 168.150 0.300 168.450 ;
    END
  END wdata[271]

  PIN wdata[270]
    DIRECTION INPUT ;
    USE SIGNAL ;
    PORT
      LAYER met3 ;
        RECT 0.000 168.830 0.300 169.130 ;
    END
  END wdata[270]

  PIN wdata[269]
    DIRECTION INPUT ;
    USE SIGNAL ;
    PORT
      LAYER met3 ;
        RECT 0.000 169.510 0.300 169.810 ;
    END
  END wdata[269]

  PIN wdata[268]
    DIRECTION INPUT ;
    USE SIGNAL ;
    PORT
      LAYER met3 ;
        RECT 0.000 170.190 0.300 170.490 ;
    END
  END wdata[268]

  PIN wdata[267]
    DIRECTION INPUT ;
    USE SIGNAL ;
    PORT
      LAYER met3 ;
        RECT 0.000 170.870 0.300 171.170 ;
    END
  END wdata[267]

  PIN wdata[266]
    DIRECTION INPUT ;
    USE SIGNAL ;
    PORT
      LAYER met3 ;
        RECT 0.000 171.550 0.300 171.850 ;
    END
  END wdata[266]

  PIN wdata[265]
    DIRECTION INPUT ;
    USE SIGNAL ;
    PORT
      LAYER met3 ;
        RECT 0.000 172.230 0.300 172.530 ;
    END
  END wdata[265]

  PIN wdata[264]
    DIRECTION INPUT ;
    USE SIGNAL ;
    PORT
      LAYER met3 ;
        RECT 0.000 172.910 0.300 173.210 ;
    END
  END wdata[264]

  PIN wdata[263]
    DIRECTION INPUT ;
    USE SIGNAL ;
    PORT
      LAYER met3 ;
        RECT 0.000 173.590 0.300 173.890 ;
    END
  END wdata[263]

  PIN wdata[262]
    DIRECTION INPUT ;
    USE SIGNAL ;
    PORT
      LAYER met3 ;
        RECT 0.000 174.270 0.300 174.570 ;
    END
  END wdata[262]

  PIN wdata[261]
    DIRECTION INPUT ;
    USE SIGNAL ;
    PORT
      LAYER met3 ;
        RECT 0.000 174.950 0.300 175.250 ;
    END
  END wdata[261]

  PIN wdata[260]
    DIRECTION INPUT ;
    USE SIGNAL ;
    PORT
      LAYER met3 ;
        RECT 0.000 175.630 0.300 175.930 ;
    END
  END wdata[260]

  PIN wdata[259]
    DIRECTION INPUT ;
    USE SIGNAL ;
    PORT
      LAYER met3 ;
        RECT 0.000 176.310 0.300 176.610 ;
    END
  END wdata[259]

  PIN wdata[258]
    DIRECTION INPUT ;
    USE SIGNAL ;
    PORT
      LAYER met3 ;
        RECT 0.000 176.990 0.300 177.290 ;
    END
  END wdata[258]

  PIN wdata[257]
    DIRECTION INPUT ;
    USE SIGNAL ;
    PORT
      LAYER met3 ;
        RECT 0.000 177.670 0.300 177.970 ;
    END
  END wdata[257]

  PIN wdata[256]
    DIRECTION INPUT ;
    USE SIGNAL ;
    PORT
      LAYER met3 ;
        RECT 0.000 178.350 0.300 178.650 ;
    END
  END wdata[256]

  PIN wdata[255]
    DIRECTION INPUT ;
    USE SIGNAL ;
    PORT
      LAYER met3 ;
        RECT 0.000 179.030 0.300 179.330 ;
    END
  END wdata[255]

  PIN wdata[254]
    DIRECTION INPUT ;
    USE SIGNAL ;
    PORT
      LAYER met3 ;
        RECT 0.000 179.710 0.300 180.010 ;
    END
  END wdata[254]

  PIN wdata[253]
    DIRECTION INPUT ;
    USE SIGNAL ;
    PORT
      LAYER met3 ;
        RECT 0.000 180.390 0.300 180.690 ;
    END
  END wdata[253]

  PIN wdata[252]
    DIRECTION INPUT ;
    USE SIGNAL ;
    PORT
      LAYER met3 ;
        RECT 0.000 181.070 0.300 181.370 ;
    END
  END wdata[252]

  PIN wdata[251]
    DIRECTION INPUT ;
    USE SIGNAL ;
    PORT
      LAYER met3 ;
        RECT 0.000 181.750 0.300 182.050 ;
    END
  END wdata[251]

  PIN wdata[250]
    DIRECTION INPUT ;
    USE SIGNAL ;
    PORT
      LAYER met3 ;
        RECT 0.000 182.430 0.300 182.730 ;
    END
  END wdata[250]

  PIN wdata[249]
    DIRECTION INPUT ;
    USE SIGNAL ;
    PORT
      LAYER met3 ;
        RECT 0.000 183.110 0.300 183.410 ;
    END
  END wdata[249]

  PIN wdata[248]
    DIRECTION INPUT ;
    USE SIGNAL ;
    PORT
      LAYER met3 ;
        RECT 0.000 183.790 0.300 184.090 ;
    END
  END wdata[248]

  PIN wdata[247]
    DIRECTION INPUT ;
    USE SIGNAL ;
    PORT
      LAYER met3 ;
        RECT 0.000 184.470 0.300 184.770 ;
    END
  END wdata[247]

  PIN wdata[246]
    DIRECTION INPUT ;
    USE SIGNAL ;
    PORT
      LAYER met3 ;
        RECT 0.000 185.150 0.300 185.450 ;
    END
  END wdata[246]

  PIN wdata[245]
    DIRECTION INPUT ;
    USE SIGNAL ;
    PORT
      LAYER met3 ;
        RECT 0.000 185.830 0.300 186.130 ;
    END
  END wdata[245]

  PIN wdata[244]
    DIRECTION INPUT ;
    USE SIGNAL ;
    PORT
      LAYER met3 ;
        RECT 0.000 186.510 0.300 186.810 ;
    END
  END wdata[244]

  PIN wdata[243]
    DIRECTION INPUT ;
    USE SIGNAL ;
    PORT
      LAYER met3 ;
        RECT 0.000 187.190 0.300 187.490 ;
    END
  END wdata[243]

  PIN wdata[242]
    DIRECTION INPUT ;
    USE SIGNAL ;
    PORT
      LAYER met3 ;
        RECT 0.000 187.870 0.300 188.170 ;
    END
  END wdata[242]

  PIN wdata[241]
    DIRECTION INPUT ;
    USE SIGNAL ;
    PORT
      LAYER met3 ;
        RECT 0.000 188.550 0.300 188.850 ;
    END
  END wdata[241]

  PIN wdata[240]
    DIRECTION INPUT ;
    USE SIGNAL ;
    PORT
      LAYER met3 ;
        RECT 0.000 189.230 0.300 189.530 ;
    END
  END wdata[240]

  PIN wdata[239]
    DIRECTION INPUT ;
    USE SIGNAL ;
    PORT
      LAYER met3 ;
        RECT 0.000 189.910 0.300 190.210 ;
    END
  END wdata[239]

  PIN wdata[238]
    DIRECTION INPUT ;
    USE SIGNAL ;
    PORT
      LAYER met3 ;
        RECT 0.000 190.590 0.300 190.890 ;
    END
  END wdata[238]

  PIN wdata[237]
    DIRECTION INPUT ;
    USE SIGNAL ;
    PORT
      LAYER met3 ;
        RECT 0.000 191.270 0.300 191.570 ;
    END
  END wdata[237]

  PIN wdata[236]
    DIRECTION INPUT ;
    USE SIGNAL ;
    PORT
      LAYER met3 ;
        RECT 0.000 191.950 0.300 192.250 ;
    END
  END wdata[236]

  PIN wdata[235]
    DIRECTION INPUT ;
    USE SIGNAL ;
    PORT
      LAYER met3 ;
        RECT 0.000 192.630 0.300 192.930 ;
    END
  END wdata[235]

  PIN wdata[234]
    DIRECTION INPUT ;
    USE SIGNAL ;
    PORT
      LAYER met3 ;
        RECT 0.000 193.310 0.300 193.610 ;
    END
  END wdata[234]

  PIN wdata[233]
    DIRECTION INPUT ;
    USE SIGNAL ;
    PORT
      LAYER met3 ;
        RECT 0.000 193.990 0.300 194.290 ;
    END
  END wdata[233]

  PIN wdata[232]
    DIRECTION INPUT ;
    USE SIGNAL ;
    PORT
      LAYER met3 ;
        RECT 0.000 194.670 0.300 194.970 ;
    END
  END wdata[232]

  PIN wdata[231]
    DIRECTION INPUT ;
    USE SIGNAL ;
    PORT
      LAYER met3 ;
        RECT 0.000 195.350 0.300 195.650 ;
    END
  END wdata[231]

  PIN wdata[230]
    DIRECTION INPUT ;
    USE SIGNAL ;
    PORT
      LAYER met3 ;
        RECT 0.000 196.030 0.300 196.330 ;
    END
  END wdata[230]

  PIN wdata[229]
    DIRECTION INPUT ;
    USE SIGNAL ;
    PORT
      LAYER met3 ;
        RECT 0.000 196.710 0.300 197.010 ;
    END
  END wdata[229]

  PIN wdata[228]
    DIRECTION INPUT ;
    USE SIGNAL ;
    PORT
      LAYER met3 ;
        RECT 0.000 197.390 0.300 197.690 ;
    END
  END wdata[228]

  PIN wdata[227]
    DIRECTION INPUT ;
    USE SIGNAL ;
    PORT
      LAYER met3 ;
        RECT 0.000 198.070 0.300 198.370 ;
    END
  END wdata[227]

  PIN wdata[226]
    DIRECTION INPUT ;
    USE SIGNAL ;
    PORT
      LAYER met3 ;
        RECT 0.000 198.750 0.300 199.050 ;
    END
  END wdata[226]

  PIN wdata[225]
    DIRECTION INPUT ;
    USE SIGNAL ;
    PORT
      LAYER met3 ;
        RECT 0.000 199.430 0.300 199.730 ;
    END
  END wdata[225]

  PIN wdata[224]
    DIRECTION INPUT ;
    USE SIGNAL ;
    PORT
      LAYER met3 ;
        RECT 0.000 200.110 0.300 200.410 ;
    END
  END wdata[224]

  PIN wdata[223]
    DIRECTION INPUT ;
    USE SIGNAL ;
    PORT
      LAYER met3 ;
        RECT 0.000 200.790 0.300 201.090 ;
    END
  END wdata[223]

  PIN wdata[222]
    DIRECTION INPUT ;
    USE SIGNAL ;
    PORT
      LAYER met3 ;
        RECT 0.000 201.470 0.300 201.770 ;
    END
  END wdata[222]

  PIN wdata[221]
    DIRECTION INPUT ;
    USE SIGNAL ;
    PORT
      LAYER met3 ;
        RECT 0.000 202.150 0.300 202.450 ;
    END
  END wdata[221]

  PIN wdata[220]
    DIRECTION INPUT ;
    USE SIGNAL ;
    PORT
      LAYER met3 ;
        RECT 0.000 202.830 0.300 203.130 ;
    END
  END wdata[220]

  PIN wdata[219]
    DIRECTION INPUT ;
    USE SIGNAL ;
    PORT
      LAYER met3 ;
        RECT 0.000 203.510 0.300 203.810 ;
    END
  END wdata[219]

  PIN wdata[218]
    DIRECTION INPUT ;
    USE SIGNAL ;
    PORT
      LAYER met3 ;
        RECT 0.000 204.190 0.300 204.490 ;
    END
  END wdata[218]

  PIN wdata[217]
    DIRECTION INPUT ;
    USE SIGNAL ;
    PORT
      LAYER met3 ;
        RECT 0.000 204.870 0.300 205.170 ;
    END
  END wdata[217]

  PIN wdata[216]
    DIRECTION INPUT ;
    USE SIGNAL ;
    PORT
      LAYER met3 ;
        RECT 0.000 205.550 0.300 205.850 ;
    END
  END wdata[216]

  PIN wdata[215]
    DIRECTION INPUT ;
    USE SIGNAL ;
    PORT
      LAYER met3 ;
        RECT 0.000 206.230 0.300 206.530 ;
    END
  END wdata[215]

  PIN wdata[214]
    DIRECTION INPUT ;
    USE SIGNAL ;
    PORT
      LAYER met3 ;
        RECT 0.000 206.910 0.300 207.210 ;
    END
  END wdata[214]

  PIN wdata[213]
    DIRECTION INPUT ;
    USE SIGNAL ;
    PORT
      LAYER met3 ;
        RECT 0.000 207.590 0.300 207.890 ;
    END
  END wdata[213]

  PIN wdata[212]
    DIRECTION INPUT ;
    USE SIGNAL ;
    PORT
      LAYER met3 ;
        RECT 0.000 208.270 0.300 208.570 ;
    END
  END wdata[212]

  PIN wdata[211]
    DIRECTION INPUT ;
    USE SIGNAL ;
    PORT
      LAYER met3 ;
        RECT 0.000 208.950 0.300 209.250 ;
    END
  END wdata[211]

  PIN wdata[210]
    DIRECTION INPUT ;
    USE SIGNAL ;
    PORT
      LAYER met3 ;
        RECT 0.000 209.630 0.300 209.930 ;
    END
  END wdata[210]

  PIN wdata[209]
    DIRECTION INPUT ;
    USE SIGNAL ;
    PORT
      LAYER met3 ;
        RECT 0.000 210.310 0.300 210.610 ;
    END
  END wdata[209]

  PIN wdata[208]
    DIRECTION INPUT ;
    USE SIGNAL ;
    PORT
      LAYER met3 ;
        RECT 0.000 210.990 0.300 211.290 ;
    END
  END wdata[208]

  PIN wdata[207]
    DIRECTION INPUT ;
    USE SIGNAL ;
    PORT
      LAYER met3 ;
        RECT 0.000 211.670 0.300 211.970 ;
    END
  END wdata[207]

  PIN wdata[206]
    DIRECTION INPUT ;
    USE SIGNAL ;
    PORT
      LAYER met3 ;
        RECT 0.000 212.350 0.300 212.650 ;
    END
  END wdata[206]

  PIN wdata[205]
    DIRECTION INPUT ;
    USE SIGNAL ;
    PORT
      LAYER met3 ;
        RECT 0.000 213.030 0.300 213.330 ;
    END
  END wdata[205]

  PIN wdata[204]
    DIRECTION INPUT ;
    USE SIGNAL ;
    PORT
      LAYER met3 ;
        RECT 0.000 213.710 0.300 214.010 ;
    END
  END wdata[204]

  PIN wdata[203]
    DIRECTION INPUT ;
    USE SIGNAL ;
    PORT
      LAYER met3 ;
        RECT 0.000 214.390 0.300 214.690 ;
    END
  END wdata[203]

  PIN wdata[202]
    DIRECTION INPUT ;
    USE SIGNAL ;
    PORT
      LAYER met3 ;
        RECT 0.000 215.070 0.300 215.370 ;
    END
  END wdata[202]

  PIN wdata[201]
    DIRECTION INPUT ;
    USE SIGNAL ;
    PORT
      LAYER met3 ;
        RECT 0.000 215.750 0.300 216.050 ;
    END
  END wdata[201]

  PIN wdata[200]
    DIRECTION INPUT ;
    USE SIGNAL ;
    PORT
      LAYER met3 ;
        RECT 0.000 216.430 0.300 216.730 ;
    END
  END wdata[200]

  PIN wdata[199]
    DIRECTION INPUT ;
    USE SIGNAL ;
    PORT
      LAYER met3 ;
        RECT 0.000 217.110 0.300 217.410 ;
    END
  END wdata[199]

  PIN wdata[198]
    DIRECTION INPUT ;
    USE SIGNAL ;
    PORT
      LAYER met3 ;
        RECT 0.000 217.790 0.300 218.090 ;
    END
  END wdata[198]

  PIN wdata[197]
    DIRECTION INPUT ;
    USE SIGNAL ;
    PORT
      LAYER met3 ;
        RECT 0.000 218.470 0.300 218.770 ;
    END
  END wdata[197]

  PIN wdata[196]
    DIRECTION INPUT ;
    USE SIGNAL ;
    PORT
      LAYER met3 ;
        RECT 0.000 219.150 0.300 219.450 ;
    END
  END wdata[196]

  PIN wdata[195]
    DIRECTION INPUT ;
    USE SIGNAL ;
    PORT
      LAYER met3 ;
        RECT 0.000 219.830 0.300 220.130 ;
    END
  END wdata[195]

  PIN wdata[194]
    DIRECTION INPUT ;
    USE SIGNAL ;
    PORT
      LAYER met3 ;
        RECT 0.000 220.510 0.300 220.810 ;
    END
  END wdata[194]

  PIN wdata[193]
    DIRECTION INPUT ;
    USE SIGNAL ;
    PORT
      LAYER met3 ;
        RECT 0.000 221.190 0.300 221.490 ;
    END
  END wdata[193]

  PIN wdata[192]
    DIRECTION INPUT ;
    USE SIGNAL ;
    PORT
      LAYER met3 ;
        RECT 0.000 221.870 0.300 222.170 ;
    END
  END wdata[192]

  PIN wdata[191]
    DIRECTION INPUT ;
    USE SIGNAL ;
    PORT
      LAYER met3 ;
        RECT 0.000 222.550 0.300 222.850 ;
    END
  END wdata[191]

  PIN wdata[190]
    DIRECTION INPUT ;
    USE SIGNAL ;
    PORT
      LAYER met3 ;
        RECT 0.000 223.230 0.300 223.530 ;
    END
  END wdata[190]

  PIN wdata[189]
    DIRECTION INPUT ;
    USE SIGNAL ;
    PORT
      LAYER met3 ;
        RECT 0.000 223.910 0.300 224.210 ;
    END
  END wdata[189]

  PIN wdata[188]
    DIRECTION INPUT ;
    USE SIGNAL ;
    PORT
      LAYER met3 ;
        RECT 0.000 224.590 0.300 224.890 ;
    END
  END wdata[188]

  PIN wdata[187]
    DIRECTION INPUT ;
    USE SIGNAL ;
    PORT
      LAYER met3 ;
        RECT 0.000 225.270 0.300 225.570 ;
    END
  END wdata[187]

  PIN wdata[186]
    DIRECTION INPUT ;
    USE SIGNAL ;
    PORT
      LAYER met3 ;
        RECT 0.000 225.950 0.300 226.250 ;
    END
  END wdata[186]

  PIN wdata[185]
    DIRECTION INPUT ;
    USE SIGNAL ;
    PORT
      LAYER met3 ;
        RECT 0.000 226.630 0.300 226.930 ;
    END
  END wdata[185]

  PIN wdata[184]
    DIRECTION INPUT ;
    USE SIGNAL ;
    PORT
      LAYER met3 ;
        RECT 0.000 227.310 0.300 227.610 ;
    END
  END wdata[184]

  PIN wdata[183]
    DIRECTION INPUT ;
    USE SIGNAL ;
    PORT
      LAYER met3 ;
        RECT 0.000 227.990 0.300 228.290 ;
    END
  END wdata[183]

  PIN wdata[182]
    DIRECTION INPUT ;
    USE SIGNAL ;
    PORT
      LAYER met3 ;
        RECT 0.000 228.670 0.300 228.970 ;
    END
  END wdata[182]

  PIN wdata[181]
    DIRECTION INPUT ;
    USE SIGNAL ;
    PORT
      LAYER met3 ;
        RECT 0.000 229.350 0.300 229.650 ;
    END
  END wdata[181]

  PIN wdata[180]
    DIRECTION INPUT ;
    USE SIGNAL ;
    PORT
      LAYER met3 ;
        RECT 0.000 230.030 0.300 230.330 ;
    END
  END wdata[180]

  PIN wdata[179]
    DIRECTION INPUT ;
    USE SIGNAL ;
    PORT
      LAYER met3 ;
        RECT 0.000 230.710 0.300 231.010 ;
    END
  END wdata[179]

  PIN wdata[178]
    DIRECTION INPUT ;
    USE SIGNAL ;
    PORT
      LAYER met3 ;
        RECT 0.000 231.390 0.300 231.690 ;
    END
  END wdata[178]

  PIN wdata[177]
    DIRECTION INPUT ;
    USE SIGNAL ;
    PORT
      LAYER met3 ;
        RECT 0.000 232.070 0.300 232.370 ;
    END
  END wdata[177]

  PIN wdata[176]
    DIRECTION INPUT ;
    USE SIGNAL ;
    PORT
      LAYER met3 ;
        RECT 0.000 232.750 0.300 233.050 ;
    END
  END wdata[176]

  PIN wdata[175]
    DIRECTION INPUT ;
    USE SIGNAL ;
    PORT
      LAYER met3 ;
        RECT 0.000 233.430 0.300 233.730 ;
    END
  END wdata[175]

  PIN wdata[174]
    DIRECTION INPUT ;
    USE SIGNAL ;
    PORT
      LAYER met3 ;
        RECT 0.000 234.110 0.300 234.410 ;
    END
  END wdata[174]

  PIN wdata[173]
    DIRECTION INPUT ;
    USE SIGNAL ;
    PORT
      LAYER met3 ;
        RECT 0.000 234.790 0.300 235.090 ;
    END
  END wdata[173]

  PIN wdata[172]
    DIRECTION INPUT ;
    USE SIGNAL ;
    PORT
      LAYER met3 ;
        RECT 0.000 235.470 0.300 235.770 ;
    END
  END wdata[172]

  PIN wdata[171]
    DIRECTION INPUT ;
    USE SIGNAL ;
    PORT
      LAYER met3 ;
        RECT 0.000 236.150 0.300 236.450 ;
    END
  END wdata[171]

  PIN wdata[170]
    DIRECTION INPUT ;
    USE SIGNAL ;
    PORT
      LAYER met3 ;
        RECT 0.000 236.830 0.300 237.130 ;
    END
  END wdata[170]

  PIN wdata[169]
    DIRECTION INPUT ;
    USE SIGNAL ;
    PORT
      LAYER met3 ;
        RECT 0.000 237.510 0.300 237.810 ;
    END
  END wdata[169]

  PIN wdata[168]
    DIRECTION INPUT ;
    USE SIGNAL ;
    PORT
      LAYER met3 ;
        RECT 0.000 238.190 0.300 238.490 ;
    END
  END wdata[168]

  PIN wdata[167]
    DIRECTION INPUT ;
    USE SIGNAL ;
    PORT
      LAYER met3 ;
        RECT 0.000 238.870 0.300 239.170 ;
    END
  END wdata[167]

  PIN wdata[166]
    DIRECTION INPUT ;
    USE SIGNAL ;
    PORT
      LAYER met3 ;
        RECT 0.000 239.550 0.300 239.850 ;
    END
  END wdata[166]

  PIN wdata[165]
    DIRECTION INPUT ;
    USE SIGNAL ;
    PORT
      LAYER met3 ;
        RECT 0.000 240.230 0.300 240.530 ;
    END
  END wdata[165]

  PIN wdata[164]
    DIRECTION INPUT ;
    USE SIGNAL ;
    PORT
      LAYER met3 ;
        RECT 0.000 240.910 0.300 241.210 ;
    END
  END wdata[164]

  PIN wdata[163]
    DIRECTION INPUT ;
    USE SIGNAL ;
    PORT
      LAYER met3 ;
        RECT 0.000 241.590 0.300 241.890 ;
    END
  END wdata[163]

  PIN wdata[162]
    DIRECTION INPUT ;
    USE SIGNAL ;
    PORT
      LAYER met3 ;
        RECT 0.000 242.270 0.300 242.570 ;
    END
  END wdata[162]

  PIN wdata[161]
    DIRECTION INPUT ;
    USE SIGNAL ;
    PORT
      LAYER met3 ;
        RECT 0.000 242.950 0.300 243.250 ;
    END
  END wdata[161]

  PIN wdata[160]
    DIRECTION INPUT ;
    USE SIGNAL ;
    PORT
      LAYER met3 ;
        RECT 0.000 243.630 0.300 243.930 ;
    END
  END wdata[160]

  PIN wdata[159]
    DIRECTION INPUT ;
    USE SIGNAL ;
    PORT
      LAYER met3 ;
        RECT 0.000 244.310 0.300 244.610 ;
    END
  END wdata[159]

  PIN wdata[158]
    DIRECTION INPUT ;
    USE SIGNAL ;
    PORT
      LAYER met3 ;
        RECT 0.000 244.990 0.300 245.290 ;
    END
  END wdata[158]

  PIN wdata[157]
    DIRECTION INPUT ;
    USE SIGNAL ;
    PORT
      LAYER met3 ;
        RECT 0.000 245.670 0.300 245.970 ;
    END
  END wdata[157]

  PIN wdata[156]
    DIRECTION INPUT ;
    USE SIGNAL ;
    PORT
      LAYER met3 ;
        RECT 0.000 246.350 0.300 246.650 ;
    END
  END wdata[156]

  PIN wdata[155]
    DIRECTION INPUT ;
    USE SIGNAL ;
    PORT
      LAYER met3 ;
        RECT 0.000 247.030 0.300 247.330 ;
    END
  END wdata[155]

  PIN wdata[154]
    DIRECTION INPUT ;
    USE SIGNAL ;
    PORT
      LAYER met3 ;
        RECT 0.000 247.710 0.300 248.010 ;
    END
  END wdata[154]

  PIN wdata[153]
    DIRECTION INPUT ;
    USE SIGNAL ;
    PORT
      LAYER met3 ;
        RECT 0.000 248.390 0.300 248.690 ;
    END
  END wdata[153]

  PIN wdata[152]
    DIRECTION INPUT ;
    USE SIGNAL ;
    PORT
      LAYER met3 ;
        RECT 0.000 249.070 0.300 249.370 ;
    END
  END wdata[152]

  PIN wdata[151]
    DIRECTION INPUT ;
    USE SIGNAL ;
    PORT
      LAYER met3 ;
        RECT 0.000 249.750 0.300 250.050 ;
    END
  END wdata[151]

  PIN wdata[150]
    DIRECTION INPUT ;
    USE SIGNAL ;
    PORT
      LAYER met3 ;
        RECT 0.000 250.430 0.300 250.730 ;
    END
  END wdata[150]

  PIN wdata[149]
    DIRECTION INPUT ;
    USE SIGNAL ;
    PORT
      LAYER met3 ;
        RECT 0.000 251.110 0.300 251.410 ;
    END
  END wdata[149]

  PIN wdata[148]
    DIRECTION INPUT ;
    USE SIGNAL ;
    PORT
      LAYER met3 ;
        RECT 0.000 251.790 0.300 252.090 ;
    END
  END wdata[148]

  PIN wdata[147]
    DIRECTION INPUT ;
    USE SIGNAL ;
    PORT
      LAYER met3 ;
        RECT 0.000 252.470 0.300 252.770 ;
    END
  END wdata[147]

  PIN wdata[146]
    DIRECTION INPUT ;
    USE SIGNAL ;
    PORT
      LAYER met3 ;
        RECT 0.000 253.150 0.300 253.450 ;
    END
  END wdata[146]

  PIN wdata[145]
    DIRECTION INPUT ;
    USE SIGNAL ;
    PORT
      LAYER met3 ;
        RECT 0.000 253.830 0.300 254.130 ;
    END
  END wdata[145]

  PIN wdata[144]
    DIRECTION INPUT ;
    USE SIGNAL ;
    PORT
      LAYER met3 ;
        RECT 0.000 254.510 0.300 254.810 ;
    END
  END wdata[144]

  PIN wdata[143]
    DIRECTION INPUT ;
    USE SIGNAL ;
    PORT
      LAYER met3 ;
        RECT 0.000 255.190 0.300 255.490 ;
    END
  END wdata[143]

  PIN wdata[142]
    DIRECTION INPUT ;
    USE SIGNAL ;
    PORT
      LAYER met3 ;
        RECT 0.000 255.870 0.300 256.170 ;
    END
  END wdata[142]

  PIN wdata[141]
    DIRECTION INPUT ;
    USE SIGNAL ;
    PORT
      LAYER met3 ;
        RECT 0.000 256.550 0.300 256.850 ;
    END
  END wdata[141]

  PIN wdata[140]
    DIRECTION INPUT ;
    USE SIGNAL ;
    PORT
      LAYER met3 ;
        RECT 0.000 257.230 0.300 257.530 ;
    END
  END wdata[140]

  PIN wdata[139]
    DIRECTION INPUT ;
    USE SIGNAL ;
    PORT
      LAYER met3 ;
        RECT 0.000 257.910 0.300 258.210 ;
    END
  END wdata[139]

  PIN wdata[138]
    DIRECTION INPUT ;
    USE SIGNAL ;
    PORT
      LAYER met3 ;
        RECT 0.000 258.590 0.300 258.890 ;
    END
  END wdata[138]

  PIN wdata[137]
    DIRECTION INPUT ;
    USE SIGNAL ;
    PORT
      LAYER met3 ;
        RECT 0.000 259.270 0.300 259.570 ;
    END
  END wdata[137]

  PIN wdata[136]
    DIRECTION INPUT ;
    USE SIGNAL ;
    PORT
      LAYER met3 ;
        RECT 0.000 259.950 0.300 260.250 ;
    END
  END wdata[136]

  PIN wdata[135]
    DIRECTION INPUT ;
    USE SIGNAL ;
    PORT
      LAYER met3 ;
        RECT 0.000 260.630 0.300 260.930 ;
    END
  END wdata[135]

  PIN wdata[134]
    DIRECTION INPUT ;
    USE SIGNAL ;
    PORT
      LAYER met3 ;
        RECT 0.000 261.310 0.300 261.610 ;
    END
  END wdata[134]

  PIN wdata[133]
    DIRECTION INPUT ;
    USE SIGNAL ;
    PORT
      LAYER met3 ;
        RECT 0.000 261.990 0.300 262.290 ;
    END
  END wdata[133]

  PIN wdata[132]
    DIRECTION INPUT ;
    USE SIGNAL ;
    PORT
      LAYER met3 ;
        RECT 0.000 262.670 0.300 262.970 ;
    END
  END wdata[132]

  PIN wdata[131]
    DIRECTION INPUT ;
    USE SIGNAL ;
    PORT
      LAYER met3 ;
        RECT 0.000 263.350 0.300 263.650 ;
    END
  END wdata[131]

  PIN wdata[130]
    DIRECTION INPUT ;
    USE SIGNAL ;
    PORT
      LAYER met3 ;
        RECT 0.000 264.030 0.300 264.330 ;
    END
  END wdata[130]

  PIN wdata[129]
    DIRECTION INPUT ;
    USE SIGNAL ;
    PORT
      LAYER met3 ;
        RECT 0.000 264.710 0.300 265.010 ;
    END
  END wdata[129]

  PIN wdata[128]
    DIRECTION INPUT ;
    USE SIGNAL ;
    PORT
      LAYER met3 ;
        RECT 0.000 265.390 0.300 265.690 ;
    END
  END wdata[128]

  PIN wdata[127]
    DIRECTION INPUT ;
    USE SIGNAL ;
    PORT
      LAYER met3 ;
        RECT 0.000 266.070 0.300 266.370 ;
    END
  END wdata[127]

  PIN wdata[126]
    DIRECTION INPUT ;
    USE SIGNAL ;
    PORT
      LAYER met3 ;
        RECT 0.000 266.750 0.300 267.050 ;
    END
  END wdata[126]

  PIN wdata[125]
    DIRECTION INPUT ;
    USE SIGNAL ;
    PORT
      LAYER met3 ;
        RECT 0.000 267.430 0.300 267.730 ;
    END
  END wdata[125]

  PIN wdata[124]
    DIRECTION INPUT ;
    USE SIGNAL ;
    PORT
      LAYER met3 ;
        RECT 0.000 268.110 0.300 268.410 ;
    END
  END wdata[124]

  PIN wdata[123]
    DIRECTION INPUT ;
    USE SIGNAL ;
    PORT
      LAYER met3 ;
        RECT 0.000 268.790 0.300 269.090 ;
    END
  END wdata[123]

  PIN wdata[122]
    DIRECTION INPUT ;
    USE SIGNAL ;
    PORT
      LAYER met3 ;
        RECT 0.000 269.470 0.300 269.770 ;
    END
  END wdata[122]

  PIN wdata[121]
    DIRECTION INPUT ;
    USE SIGNAL ;
    PORT
      LAYER met3 ;
        RECT 0.000 270.150 0.300 270.450 ;
    END
  END wdata[121]

  PIN wdata[120]
    DIRECTION INPUT ;
    USE SIGNAL ;
    PORT
      LAYER met3 ;
        RECT 0.000 270.830 0.300 271.130 ;
    END
  END wdata[120]

  PIN wdata[119]
    DIRECTION INPUT ;
    USE SIGNAL ;
    PORT
      LAYER met3 ;
        RECT 0.000 271.510 0.300 271.810 ;
    END
  END wdata[119]

  PIN wdata[118]
    DIRECTION INPUT ;
    USE SIGNAL ;
    PORT
      LAYER met3 ;
        RECT 0.000 272.190 0.300 272.490 ;
    END
  END wdata[118]

  PIN wdata[117]
    DIRECTION INPUT ;
    USE SIGNAL ;
    PORT
      LAYER met3 ;
        RECT 0.000 272.870 0.300 273.170 ;
    END
  END wdata[117]

  PIN wdata[116]
    DIRECTION INPUT ;
    USE SIGNAL ;
    PORT
      LAYER met3 ;
        RECT 0.000 273.550 0.300 273.850 ;
    END
  END wdata[116]

  PIN wdata[115]
    DIRECTION INPUT ;
    USE SIGNAL ;
    PORT
      LAYER met3 ;
        RECT 0.000 274.230 0.300 274.530 ;
    END
  END wdata[115]

  PIN wdata[114]
    DIRECTION INPUT ;
    USE SIGNAL ;
    PORT
      LAYER met3 ;
        RECT 0.000 274.910 0.300 275.210 ;
    END
  END wdata[114]

  PIN wdata[113]
    DIRECTION INPUT ;
    USE SIGNAL ;
    PORT
      LAYER met3 ;
        RECT 0.000 275.590 0.300 275.890 ;
    END
  END wdata[113]

  PIN wdata[112]
    DIRECTION INPUT ;
    USE SIGNAL ;
    PORT
      LAYER met3 ;
        RECT 0.000 276.270 0.300 276.570 ;
    END
  END wdata[112]

  PIN wdata[111]
    DIRECTION INPUT ;
    USE SIGNAL ;
    PORT
      LAYER met3 ;
        RECT 0.000 276.950 0.300 277.250 ;
    END
  END wdata[111]

  PIN wdata[110]
    DIRECTION INPUT ;
    USE SIGNAL ;
    PORT
      LAYER met3 ;
        RECT 0.000 277.630 0.300 277.930 ;
    END
  END wdata[110]

  PIN wdata[109]
    DIRECTION INPUT ;
    USE SIGNAL ;
    PORT
      LAYER met3 ;
        RECT 0.000 278.310 0.300 278.610 ;
    END
  END wdata[109]

  PIN wdata[108]
    DIRECTION INPUT ;
    USE SIGNAL ;
    PORT
      LAYER met3 ;
        RECT 0.000 278.990 0.300 279.290 ;
    END
  END wdata[108]

  PIN wdata[107]
    DIRECTION INPUT ;
    USE SIGNAL ;
    PORT
      LAYER met3 ;
        RECT 0.000 279.670 0.300 279.970 ;
    END
  END wdata[107]

  PIN wdata[106]
    DIRECTION INPUT ;
    USE SIGNAL ;
    PORT
      LAYER met3 ;
        RECT 0.000 280.350 0.300 280.650 ;
    END
  END wdata[106]

  PIN wdata[105]
    DIRECTION INPUT ;
    USE SIGNAL ;
    PORT
      LAYER met3 ;
        RECT 0.000 281.030 0.300 281.330 ;
    END
  END wdata[105]

  PIN wdata[104]
    DIRECTION INPUT ;
    USE SIGNAL ;
    PORT
      LAYER met3 ;
        RECT 0.000 281.710 0.300 282.010 ;
    END
  END wdata[104]

  PIN wdata[103]
    DIRECTION INPUT ;
    USE SIGNAL ;
    PORT
      LAYER met3 ;
        RECT 0.000 282.390 0.300 282.690 ;
    END
  END wdata[103]

  PIN wdata[102]
    DIRECTION INPUT ;
    USE SIGNAL ;
    PORT
      LAYER met3 ;
        RECT 0.000 283.070 0.300 283.370 ;
    END
  END wdata[102]

  PIN wdata[101]
    DIRECTION INPUT ;
    USE SIGNAL ;
    PORT
      LAYER met3 ;
        RECT 0.000 283.750 0.300 284.050 ;
    END
  END wdata[101]

  PIN wdata[100]
    DIRECTION INPUT ;
    USE SIGNAL ;
    PORT
      LAYER met3 ;
        RECT 0.000 284.430 0.300 284.730 ;
    END
  END wdata[100]

  PIN wdata[99]
    DIRECTION INPUT ;
    USE SIGNAL ;
    PORT
      LAYER met3 ;
        RECT 0.000 285.110 0.300 285.410 ;
    END
  END wdata[99]

  PIN wdata[98]
    DIRECTION INPUT ;
    USE SIGNAL ;
    PORT
      LAYER met3 ;
        RECT 0.000 285.790 0.300 286.090 ;
    END
  END wdata[98]

  PIN wdata[97]
    DIRECTION INPUT ;
    USE SIGNAL ;
    PORT
      LAYER met3 ;
        RECT 0.000 286.470 0.300 286.770 ;
    END
  END wdata[97]

  PIN wdata[96]
    DIRECTION INPUT ;
    USE SIGNAL ;
    PORT
      LAYER met3 ;
        RECT 0.000 287.150 0.300 287.450 ;
    END
  END wdata[96]

  PIN wdata[95]
    DIRECTION INPUT ;
    USE SIGNAL ;
    PORT
      LAYER met3 ;
        RECT 0.000 287.830 0.300 288.130 ;
    END
  END wdata[95]

  PIN wdata[94]
    DIRECTION INPUT ;
    USE SIGNAL ;
    PORT
      LAYER met3 ;
        RECT 0.000 288.510 0.300 288.810 ;
    END
  END wdata[94]

  PIN wdata[93]
    DIRECTION INPUT ;
    USE SIGNAL ;
    PORT
      LAYER met3 ;
        RECT 0.000 289.190 0.300 289.490 ;
    END
  END wdata[93]

  PIN wdata[92]
    DIRECTION INPUT ;
    USE SIGNAL ;
    PORT
      LAYER met3 ;
        RECT 0.000 289.870 0.300 290.170 ;
    END
  END wdata[92]

  PIN wdata[91]
    DIRECTION INPUT ;
    USE SIGNAL ;
    PORT
      LAYER met3 ;
        RECT 0.000 290.550 0.300 290.850 ;
    END
  END wdata[91]

  PIN wdata[90]
    DIRECTION INPUT ;
    USE SIGNAL ;
    PORT
      LAYER met3 ;
        RECT 0.000 291.230 0.300 291.530 ;
    END
  END wdata[90]

  PIN wdata[89]
    DIRECTION INPUT ;
    USE SIGNAL ;
    PORT
      LAYER met3 ;
        RECT 0.000 291.910 0.300 292.210 ;
    END
  END wdata[89]

  PIN wdata[88]
    DIRECTION INPUT ;
    USE SIGNAL ;
    PORT
      LAYER met3 ;
        RECT 0.000 292.590 0.300 292.890 ;
    END
  END wdata[88]

  PIN wdata[87]
    DIRECTION INPUT ;
    USE SIGNAL ;
    PORT
      LAYER met3 ;
        RECT 0.000 293.270 0.300 293.570 ;
    END
  END wdata[87]

  PIN wdata[86]
    DIRECTION INPUT ;
    USE SIGNAL ;
    PORT
      LAYER met3 ;
        RECT 0.000 293.950 0.300 294.250 ;
    END
  END wdata[86]

  PIN wdata[85]
    DIRECTION INPUT ;
    USE SIGNAL ;
    PORT
      LAYER met3 ;
        RECT 0.000 294.630 0.300 294.930 ;
    END
  END wdata[85]

  PIN wdata[84]
    DIRECTION INPUT ;
    USE SIGNAL ;
    PORT
      LAYER met3 ;
        RECT 0.000 295.310 0.300 295.610 ;
    END
  END wdata[84]

  PIN wdata[83]
    DIRECTION INPUT ;
    USE SIGNAL ;
    PORT
      LAYER met3 ;
        RECT 0.000 295.990 0.300 296.290 ;
    END
  END wdata[83]

  PIN wdata[82]
    DIRECTION INPUT ;
    USE SIGNAL ;
    PORT
      LAYER met3 ;
        RECT 0.000 296.670 0.300 296.970 ;
    END
  END wdata[82]

  PIN wdata[81]
    DIRECTION INPUT ;
    USE SIGNAL ;
    PORT
      LAYER met3 ;
        RECT 0.000 297.350 0.300 297.650 ;
    END
  END wdata[81]

  PIN wdata[80]
    DIRECTION INPUT ;
    USE SIGNAL ;
    PORT
      LAYER met3 ;
        RECT 0.000 298.030 0.300 298.330 ;
    END
  END wdata[80]

  PIN wdata[79]
    DIRECTION INPUT ;
    USE SIGNAL ;
    PORT
      LAYER met3 ;
        RECT 0.000 298.710 0.300 299.010 ;
    END
  END wdata[79]

  PIN wdata[78]
    DIRECTION INPUT ;
    USE SIGNAL ;
    PORT
      LAYER met3 ;
        RECT 0.000 299.390 0.300 299.690 ;
    END
  END wdata[78]

  PIN wdata[77]
    DIRECTION INPUT ;
    USE SIGNAL ;
    PORT
      LAYER met3 ;
        RECT 0.000 300.070 0.300 300.370 ;
    END
  END wdata[77]

  PIN wdata[76]
    DIRECTION INPUT ;
    USE SIGNAL ;
    PORT
      LAYER met3 ;
        RECT 0.000 300.750 0.300 301.050 ;
    END
  END wdata[76]

  PIN wdata[75]
    DIRECTION INPUT ;
    USE SIGNAL ;
    PORT
      LAYER met3 ;
        RECT 0.000 301.430 0.300 301.730 ;
    END
  END wdata[75]

  PIN wdata[74]
    DIRECTION INPUT ;
    USE SIGNAL ;
    PORT
      LAYER met3 ;
        RECT 0.000 302.110 0.300 302.410 ;
    END
  END wdata[74]

  PIN wdata[73]
    DIRECTION INPUT ;
    USE SIGNAL ;
    PORT
      LAYER met3 ;
        RECT 0.000 302.790 0.300 303.090 ;
    END
  END wdata[73]

  PIN wdata[72]
    DIRECTION INPUT ;
    USE SIGNAL ;
    PORT
      LAYER met3 ;
        RECT 0.000 303.470 0.300 303.770 ;
    END
  END wdata[72]

  PIN wdata[71]
    DIRECTION INPUT ;
    USE SIGNAL ;
    PORT
      LAYER met3 ;
        RECT 0.000 304.150 0.300 304.450 ;
    END
  END wdata[71]

  PIN wdata[70]
    DIRECTION INPUT ;
    USE SIGNAL ;
    PORT
      LAYER met3 ;
        RECT 0.000 304.830 0.300 305.130 ;
    END
  END wdata[70]

  PIN wdata[69]
    DIRECTION INPUT ;
    USE SIGNAL ;
    PORT
      LAYER met3 ;
        RECT 0.000 305.510 0.300 305.810 ;
    END
  END wdata[69]

  PIN wdata[68]
    DIRECTION INPUT ;
    USE SIGNAL ;
    PORT
      LAYER met3 ;
        RECT 0.000 306.190 0.300 306.490 ;
    END
  END wdata[68]

  PIN wdata[67]
    DIRECTION INPUT ;
    USE SIGNAL ;
    PORT
      LAYER met3 ;
        RECT 0.000 306.870 0.300 307.170 ;
    END
  END wdata[67]

  PIN wdata[66]
    DIRECTION INPUT ;
    USE SIGNAL ;
    PORT
      LAYER met3 ;
        RECT 0.000 307.550 0.300 307.850 ;
    END
  END wdata[66]

  PIN wdata[65]
    DIRECTION INPUT ;
    USE SIGNAL ;
    PORT
      LAYER met3 ;
        RECT 0.000 308.230 0.300 308.530 ;
    END
  END wdata[65]

  PIN wdata[64]
    DIRECTION INPUT ;
    USE SIGNAL ;
    PORT
      LAYER met3 ;
        RECT 0.000 308.910 0.300 309.210 ;
    END
  END wdata[64]

  PIN wdata[63]
    DIRECTION INPUT ;
    USE SIGNAL ;
    PORT
      LAYER met3 ;
        RECT 0.000 309.590 0.300 309.890 ;
    END
  END wdata[63]

  PIN wdata[62]
    DIRECTION INPUT ;
    USE SIGNAL ;
    PORT
      LAYER met3 ;
        RECT 0.000 310.270 0.300 310.570 ;
    END
  END wdata[62]

  PIN wdata[61]
    DIRECTION INPUT ;
    USE SIGNAL ;
    PORT
      LAYER met3 ;
        RECT 0.000 310.950 0.300 311.250 ;
    END
  END wdata[61]

  PIN wdata[60]
    DIRECTION INPUT ;
    USE SIGNAL ;
    PORT
      LAYER met3 ;
        RECT 0.000 311.630 0.300 311.930 ;
    END
  END wdata[60]

  PIN wdata[59]
    DIRECTION INPUT ;
    USE SIGNAL ;
    PORT
      LAYER met3 ;
        RECT 0.000 312.310 0.300 312.610 ;
    END
  END wdata[59]

  PIN wdata[58]
    DIRECTION INPUT ;
    USE SIGNAL ;
    PORT
      LAYER met3 ;
        RECT 0.000 312.990 0.300 313.290 ;
    END
  END wdata[58]

  PIN wdata[57]
    DIRECTION INPUT ;
    USE SIGNAL ;
    PORT
      LAYER met3 ;
        RECT 0.000 313.670 0.300 313.970 ;
    END
  END wdata[57]

  PIN wdata[56]
    DIRECTION INPUT ;
    USE SIGNAL ;
    PORT
      LAYER met3 ;
        RECT 0.000 314.350 0.300 314.650 ;
    END
  END wdata[56]

  PIN wdata[55]
    DIRECTION INPUT ;
    USE SIGNAL ;
    PORT
      LAYER met3 ;
        RECT 0.000 315.030 0.300 315.330 ;
    END
  END wdata[55]

  PIN wdata[54]
    DIRECTION INPUT ;
    USE SIGNAL ;
    PORT
      LAYER met3 ;
        RECT 0.000 315.710 0.300 316.010 ;
    END
  END wdata[54]

  PIN wdata[53]
    DIRECTION INPUT ;
    USE SIGNAL ;
    PORT
      LAYER met3 ;
        RECT 0.000 316.390 0.300 316.690 ;
    END
  END wdata[53]

  PIN wdata[52]
    DIRECTION INPUT ;
    USE SIGNAL ;
    PORT
      LAYER met3 ;
        RECT 0.000 317.070 0.300 317.370 ;
    END
  END wdata[52]

  PIN wdata[51]
    DIRECTION INPUT ;
    USE SIGNAL ;
    PORT
      LAYER met3 ;
        RECT 0.000 317.750 0.300 318.050 ;
    END
  END wdata[51]

  PIN wdata[50]
    DIRECTION INPUT ;
    USE SIGNAL ;
    PORT
      LAYER met3 ;
        RECT 0.000 318.430 0.300 318.730 ;
    END
  END wdata[50]

  PIN wdata[49]
    DIRECTION INPUT ;
    USE SIGNAL ;
    PORT
      LAYER met3 ;
        RECT 0.000 319.110 0.300 319.410 ;
    END
  END wdata[49]

  PIN wdata[48]
    DIRECTION INPUT ;
    USE SIGNAL ;
    PORT
      LAYER met3 ;
        RECT 0.000 319.790 0.300 320.090 ;
    END
  END wdata[48]

  PIN wdata[47]
    DIRECTION INPUT ;
    USE SIGNAL ;
    PORT
      LAYER met3 ;
        RECT 0.000 320.470 0.300 320.770 ;
    END
  END wdata[47]

  PIN wdata[46]
    DIRECTION INPUT ;
    USE SIGNAL ;
    PORT
      LAYER met3 ;
        RECT 0.000 321.150 0.300 321.450 ;
    END
  END wdata[46]

  PIN wdata[45]
    DIRECTION INPUT ;
    USE SIGNAL ;
    PORT
      LAYER met3 ;
        RECT 0.000 321.830 0.300 322.130 ;
    END
  END wdata[45]

  PIN wdata[44]
    DIRECTION INPUT ;
    USE SIGNAL ;
    PORT
      LAYER met3 ;
        RECT 0.000 322.510 0.300 322.810 ;
    END
  END wdata[44]

  PIN wdata[43]
    DIRECTION INPUT ;
    USE SIGNAL ;
    PORT
      LAYER met3 ;
        RECT 0.000 323.190 0.300 323.490 ;
    END
  END wdata[43]

  PIN wdata[42]
    DIRECTION INPUT ;
    USE SIGNAL ;
    PORT
      LAYER met3 ;
        RECT 0.000 323.870 0.300 324.170 ;
    END
  END wdata[42]

  PIN wdata[41]
    DIRECTION INPUT ;
    USE SIGNAL ;
    PORT
      LAYER met3 ;
        RECT 0.000 324.550 0.300 324.850 ;
    END
  END wdata[41]

  PIN wdata[40]
    DIRECTION INPUT ;
    USE SIGNAL ;
    PORT
      LAYER met3 ;
        RECT 0.000 325.230 0.300 325.530 ;
    END
  END wdata[40]

  PIN wdata[39]
    DIRECTION INPUT ;
    USE SIGNAL ;
    PORT
      LAYER met3 ;
        RECT 0.000 325.910 0.300 326.210 ;
    END
  END wdata[39]

  PIN wdata[38]
    DIRECTION INPUT ;
    USE SIGNAL ;
    PORT
      LAYER met3 ;
        RECT 0.000 326.590 0.300 326.890 ;
    END
  END wdata[38]

  PIN wdata[37]
    DIRECTION INPUT ;
    USE SIGNAL ;
    PORT
      LAYER met3 ;
        RECT 0.000 327.270 0.300 327.570 ;
    END
  END wdata[37]

  PIN wdata[36]
    DIRECTION INPUT ;
    USE SIGNAL ;
    PORT
      LAYER met3 ;
        RECT 0.000 327.950 0.300 328.250 ;
    END
  END wdata[36]

  PIN wdata[35]
    DIRECTION INPUT ;
    USE SIGNAL ;
    PORT
      LAYER met3 ;
        RECT 0.000 328.630 0.300 328.930 ;
    END
  END wdata[35]

  PIN wdata[34]
    DIRECTION INPUT ;
    USE SIGNAL ;
    PORT
      LAYER met3 ;
        RECT 0.000 329.310 0.300 329.610 ;
    END
  END wdata[34]

  PIN wdata[33]
    DIRECTION INPUT ;
    USE SIGNAL ;
    PORT
      LAYER met3 ;
        RECT 0.000 329.990 0.300 330.290 ;
    END
  END wdata[33]

  PIN wdata[32]
    DIRECTION INPUT ;
    USE SIGNAL ;
    PORT
      LAYER met3 ;
        RECT 0.000 330.670 0.300 330.970 ;
    END
  END wdata[32]

  PIN wdata[31]
    DIRECTION INPUT ;
    USE SIGNAL ;
    PORT
      LAYER met3 ;
        RECT 0.000 331.350 0.300 331.650 ;
    END
  END wdata[31]

  PIN wdata[30]
    DIRECTION INPUT ;
    USE SIGNAL ;
    PORT
      LAYER met3 ;
        RECT 0.000 332.030 0.300 332.330 ;
    END
  END wdata[30]

  PIN wdata[29]
    DIRECTION INPUT ;
    USE SIGNAL ;
    PORT
      LAYER met3 ;
        RECT 0.000 332.710 0.300 333.010 ;
    END
  END wdata[29]

  PIN wdata[28]
    DIRECTION INPUT ;
    USE SIGNAL ;
    PORT
      LAYER met3 ;
        RECT 0.000 333.390 0.300 333.690 ;
    END
  END wdata[28]

  PIN wdata[27]
    DIRECTION INPUT ;
    USE SIGNAL ;
    PORT
      LAYER met3 ;
        RECT 0.000 334.070 0.300 334.370 ;
    END
  END wdata[27]

  PIN wdata[26]
    DIRECTION INPUT ;
    USE SIGNAL ;
    PORT
      LAYER met3 ;
        RECT 0.000 334.750 0.300 335.050 ;
    END
  END wdata[26]

  PIN wdata[25]
    DIRECTION INPUT ;
    USE SIGNAL ;
    PORT
      LAYER met3 ;
        RECT 0.000 335.430 0.300 335.730 ;
    END
  END wdata[25]

  PIN wdata[24]
    DIRECTION INPUT ;
    USE SIGNAL ;
    PORT
      LAYER met3 ;
        RECT 0.000 336.110 0.300 336.410 ;
    END
  END wdata[24]

  PIN wdata[23]
    DIRECTION INPUT ;
    USE SIGNAL ;
    PORT
      LAYER met3 ;
        RECT 0.000 336.790 0.300 337.090 ;
    END
  END wdata[23]

  PIN wdata[22]
    DIRECTION INPUT ;
    USE SIGNAL ;
    PORT
      LAYER met3 ;
        RECT 0.000 337.470 0.300 337.770 ;
    END
  END wdata[22]

  PIN wdata[21]
    DIRECTION INPUT ;
    USE SIGNAL ;
    PORT
      LAYER met3 ;
        RECT 0.000 338.150 0.300 338.450 ;
    END
  END wdata[21]

  PIN wdata[20]
    DIRECTION INPUT ;
    USE SIGNAL ;
    PORT
      LAYER met3 ;
        RECT 0.000 338.830 0.300 339.130 ;
    END
  END wdata[20]

  PIN wdata[19]
    DIRECTION INPUT ;
    USE SIGNAL ;
    PORT
      LAYER met3 ;
        RECT 0.000 339.510 0.300 339.810 ;
    END
  END wdata[19]

  PIN wdata[18]
    DIRECTION INPUT ;
    USE SIGNAL ;
    PORT
      LAYER met3 ;
        RECT 0.000 340.190 0.300 340.490 ;
    END
  END wdata[18]

  PIN wdata[17]
    DIRECTION INPUT ;
    USE SIGNAL ;
    PORT
      LAYER met3 ;
        RECT 0.000 340.870 0.300 341.170 ;
    END
  END wdata[17]

  PIN wdata[16]
    DIRECTION INPUT ;
    USE SIGNAL ;
    PORT
      LAYER met3 ;
        RECT 0.000 341.550 0.300 341.850 ;
    END
  END wdata[16]

  PIN wdata[15]
    DIRECTION INPUT ;
    USE SIGNAL ;
    PORT
      LAYER met3 ;
        RECT 0.000 342.230 0.300 342.530 ;
    END
  END wdata[15]

  PIN wdata[14]
    DIRECTION INPUT ;
    USE SIGNAL ;
    PORT
      LAYER met3 ;
        RECT 0.000 342.910 0.300 343.210 ;
    END
  END wdata[14]

  PIN wdata[13]
    DIRECTION INPUT ;
    USE SIGNAL ;
    PORT
      LAYER met3 ;
        RECT 0.000 343.590 0.300 343.890 ;
    END
  END wdata[13]

  PIN wdata[12]
    DIRECTION INPUT ;
    USE SIGNAL ;
    PORT
      LAYER met3 ;
        RECT 0.000 344.270 0.300 344.570 ;
    END
  END wdata[12]

  PIN wdata[11]
    DIRECTION INPUT ;
    USE SIGNAL ;
    PORT
      LAYER met3 ;
        RECT 0.000 344.950 0.300 345.250 ;
    END
  END wdata[11]

  PIN wdata[10]
    DIRECTION INPUT ;
    USE SIGNAL ;
    PORT
      LAYER met3 ;
        RECT 0.000 345.630 0.300 345.930 ;
    END
  END wdata[10]

  PIN wdata[9]
    DIRECTION INPUT ;
    USE SIGNAL ;
    PORT
      LAYER met3 ;
        RECT 0.000 346.310 0.300 346.610 ;
    END
  END wdata[9]

  PIN wdata[8]
    DIRECTION INPUT ;
    USE SIGNAL ;
    PORT
      LAYER met3 ;
        RECT 0.000 346.990 0.300 347.290 ;
    END
  END wdata[8]

  PIN wdata[7]
    DIRECTION INPUT ;
    USE SIGNAL ;
    PORT
      LAYER met3 ;
        RECT 0.000 347.670 0.300 347.970 ;
    END
  END wdata[7]

  PIN wdata[6]
    DIRECTION INPUT ;
    USE SIGNAL ;
    PORT
      LAYER met3 ;
        RECT 0.000 348.350 0.300 348.650 ;
    END
  END wdata[6]

  PIN wdata[5]
    DIRECTION INPUT ;
    USE SIGNAL ;
    PORT
      LAYER met3 ;
        RECT 0.000 349.030 0.300 349.330 ;
    END
  END wdata[5]

  PIN wdata[4]
    DIRECTION INPUT ;
    USE SIGNAL ;
    PORT
      LAYER met3 ;
        RECT 0.000 349.710 0.300 350.010 ;
    END
  END wdata[4]

  PIN wdata[3]
    DIRECTION INPUT ;
    USE SIGNAL ;
    PORT
      LAYER met3 ;
        RECT 0.000 350.390 0.300 350.690 ;
    END
  END wdata[3]

  PIN wdata[2]
    DIRECTION INPUT ;
    USE SIGNAL ;
    PORT
      LAYER met3 ;
        RECT 0.000 351.070 0.300 351.370 ;
    END
  END wdata[2]

  PIN wdata[1]
    DIRECTION INPUT ;
    USE SIGNAL ;
    PORT
      LAYER met3 ;
        RECT 0.000 351.750 0.300 352.050 ;
    END
  END wdata[1]

  PIN wdata[0]
    DIRECTION INPUT ;
    USE SIGNAL ;
    PORT
      LAYER met3 ;
        RECT 0.000 352.430 0.300 352.730 ;
    END
  END wdata[0]

  PIN rdata[511]
    DIRECTION OUTPUT ;
    USE SIGNAL ;
    PORT
      LAYER met3 ;
        RECT 199.700 0.190 200.000 0.490 ;
    END
  END rdata[511]

  PIN rdata[510]
    DIRECTION OUTPUT ;
    USE SIGNAL ;
    PORT
      LAYER met3 ;
        RECT 199.700 0.870 200.000 1.170 ;
    END
  END rdata[510]

  PIN rdata[509]
    DIRECTION OUTPUT ;
    USE SIGNAL ;
    PORT
      LAYER met3 ;
        RECT 199.700 1.550 200.000 1.850 ;
    END
  END rdata[509]

  PIN rdata[508]
    DIRECTION OUTPUT ;
    USE SIGNAL ;
    PORT
      LAYER met3 ;
        RECT 199.700 2.230 200.000 2.530 ;
    END
  END rdata[508]

  PIN rdata[507]
    DIRECTION OUTPUT ;
    USE SIGNAL ;
    PORT
      LAYER met3 ;
        RECT 199.700 2.910 200.000 3.210 ;
    END
  END rdata[507]

  PIN rdata[506]
    DIRECTION OUTPUT ;
    USE SIGNAL ;
    PORT
      LAYER met3 ;
        RECT 199.700 3.590 200.000 3.890 ;
    END
  END rdata[506]

  PIN rdata[505]
    DIRECTION OUTPUT ;
    USE SIGNAL ;
    PORT
      LAYER met3 ;
        RECT 199.700 4.270 200.000 4.570 ;
    END
  END rdata[505]

  PIN rdata[504]
    DIRECTION OUTPUT ;
    USE SIGNAL ;
    PORT
      LAYER met3 ;
        RECT 199.700 4.950 200.000 5.250 ;
    END
  END rdata[504]

  PIN rdata[503]
    DIRECTION OUTPUT ;
    USE SIGNAL ;
    PORT
      LAYER met3 ;
        RECT 199.700 5.630 200.000 5.930 ;
    END
  END rdata[503]

  PIN rdata[502]
    DIRECTION OUTPUT ;
    USE SIGNAL ;
    PORT
      LAYER met3 ;
        RECT 199.700 6.310 200.000 6.610 ;
    END
  END rdata[502]

  PIN rdata[501]
    DIRECTION OUTPUT ;
    USE SIGNAL ;
    PORT
      LAYER met3 ;
        RECT 199.700 6.990 200.000 7.290 ;
    END
  END rdata[501]

  PIN rdata[500]
    DIRECTION OUTPUT ;
    USE SIGNAL ;
    PORT
      LAYER met3 ;
        RECT 199.700 7.670 200.000 7.970 ;
    END
  END rdata[500]

  PIN rdata[499]
    DIRECTION OUTPUT ;
    USE SIGNAL ;
    PORT
      LAYER met3 ;
        RECT 199.700 8.350 200.000 8.650 ;
    END
  END rdata[499]

  PIN rdata[498]
    DIRECTION OUTPUT ;
    USE SIGNAL ;
    PORT
      LAYER met3 ;
        RECT 199.700 9.030 200.000 9.330 ;
    END
  END rdata[498]

  PIN rdata[497]
    DIRECTION OUTPUT ;
    USE SIGNAL ;
    PORT
      LAYER met3 ;
        RECT 199.700 9.710 200.000 10.010 ;
    END
  END rdata[497]

  PIN rdata[496]
    DIRECTION OUTPUT ;
    USE SIGNAL ;
    PORT
      LAYER met3 ;
        RECT 199.700 10.390 200.000 10.690 ;
    END
  END rdata[496]

  PIN rdata[495]
    DIRECTION OUTPUT ;
    USE SIGNAL ;
    PORT
      LAYER met3 ;
        RECT 199.700 11.070 200.000 11.370 ;
    END
  END rdata[495]

  PIN rdata[494]
    DIRECTION OUTPUT ;
    USE SIGNAL ;
    PORT
      LAYER met3 ;
        RECT 199.700 11.750 200.000 12.050 ;
    END
  END rdata[494]

  PIN rdata[493]
    DIRECTION OUTPUT ;
    USE SIGNAL ;
    PORT
      LAYER met3 ;
        RECT 199.700 12.430 200.000 12.730 ;
    END
  END rdata[493]

  PIN rdata[492]
    DIRECTION OUTPUT ;
    USE SIGNAL ;
    PORT
      LAYER met3 ;
        RECT 199.700 13.110 200.000 13.410 ;
    END
  END rdata[492]

  PIN rdata[491]
    DIRECTION OUTPUT ;
    USE SIGNAL ;
    PORT
      LAYER met3 ;
        RECT 199.700 13.790 200.000 14.090 ;
    END
  END rdata[491]

  PIN rdata[490]
    DIRECTION OUTPUT ;
    USE SIGNAL ;
    PORT
      LAYER met3 ;
        RECT 199.700 14.470 200.000 14.770 ;
    END
  END rdata[490]

  PIN rdata[489]
    DIRECTION OUTPUT ;
    USE SIGNAL ;
    PORT
      LAYER met3 ;
        RECT 199.700 15.150 200.000 15.450 ;
    END
  END rdata[489]

  PIN rdata[488]
    DIRECTION OUTPUT ;
    USE SIGNAL ;
    PORT
      LAYER met3 ;
        RECT 199.700 15.830 200.000 16.130 ;
    END
  END rdata[488]

  PIN rdata[487]
    DIRECTION OUTPUT ;
    USE SIGNAL ;
    PORT
      LAYER met3 ;
        RECT 199.700 16.510 200.000 16.810 ;
    END
  END rdata[487]

  PIN rdata[486]
    DIRECTION OUTPUT ;
    USE SIGNAL ;
    PORT
      LAYER met3 ;
        RECT 199.700 17.190 200.000 17.490 ;
    END
  END rdata[486]

  PIN rdata[485]
    DIRECTION OUTPUT ;
    USE SIGNAL ;
    PORT
      LAYER met3 ;
        RECT 199.700 17.870 200.000 18.170 ;
    END
  END rdata[485]

  PIN rdata[484]
    DIRECTION OUTPUT ;
    USE SIGNAL ;
    PORT
      LAYER met3 ;
        RECT 199.700 18.550 200.000 18.850 ;
    END
  END rdata[484]

  PIN rdata[483]
    DIRECTION OUTPUT ;
    USE SIGNAL ;
    PORT
      LAYER met3 ;
        RECT 199.700 19.230 200.000 19.530 ;
    END
  END rdata[483]

  PIN rdata[482]
    DIRECTION OUTPUT ;
    USE SIGNAL ;
    PORT
      LAYER met3 ;
        RECT 199.700 19.910 200.000 20.210 ;
    END
  END rdata[482]

  PIN rdata[481]
    DIRECTION OUTPUT ;
    USE SIGNAL ;
    PORT
      LAYER met3 ;
        RECT 199.700 20.590 200.000 20.890 ;
    END
  END rdata[481]

  PIN rdata[480]
    DIRECTION OUTPUT ;
    USE SIGNAL ;
    PORT
      LAYER met3 ;
        RECT 199.700 21.270 200.000 21.570 ;
    END
  END rdata[480]

  PIN rdata[479]
    DIRECTION OUTPUT ;
    USE SIGNAL ;
    PORT
      LAYER met3 ;
        RECT 199.700 21.950 200.000 22.250 ;
    END
  END rdata[479]

  PIN rdata[478]
    DIRECTION OUTPUT ;
    USE SIGNAL ;
    PORT
      LAYER met3 ;
        RECT 199.700 22.630 200.000 22.930 ;
    END
  END rdata[478]

  PIN rdata[477]
    DIRECTION OUTPUT ;
    USE SIGNAL ;
    PORT
      LAYER met3 ;
        RECT 199.700 23.310 200.000 23.610 ;
    END
  END rdata[477]

  PIN rdata[476]
    DIRECTION OUTPUT ;
    USE SIGNAL ;
    PORT
      LAYER met3 ;
        RECT 199.700 23.990 200.000 24.290 ;
    END
  END rdata[476]

  PIN rdata[475]
    DIRECTION OUTPUT ;
    USE SIGNAL ;
    PORT
      LAYER met3 ;
        RECT 199.700 24.670 200.000 24.970 ;
    END
  END rdata[475]

  PIN rdata[474]
    DIRECTION OUTPUT ;
    USE SIGNAL ;
    PORT
      LAYER met3 ;
        RECT 199.700 25.350 200.000 25.650 ;
    END
  END rdata[474]

  PIN rdata[473]
    DIRECTION OUTPUT ;
    USE SIGNAL ;
    PORT
      LAYER met3 ;
        RECT 199.700 26.030 200.000 26.330 ;
    END
  END rdata[473]

  PIN rdata[472]
    DIRECTION OUTPUT ;
    USE SIGNAL ;
    PORT
      LAYER met3 ;
        RECT 199.700 26.710 200.000 27.010 ;
    END
  END rdata[472]

  PIN rdata[471]
    DIRECTION OUTPUT ;
    USE SIGNAL ;
    PORT
      LAYER met3 ;
        RECT 199.700 27.390 200.000 27.690 ;
    END
  END rdata[471]

  PIN rdata[470]
    DIRECTION OUTPUT ;
    USE SIGNAL ;
    PORT
      LAYER met3 ;
        RECT 199.700 28.070 200.000 28.370 ;
    END
  END rdata[470]

  PIN rdata[469]
    DIRECTION OUTPUT ;
    USE SIGNAL ;
    PORT
      LAYER met3 ;
        RECT 199.700 28.750 200.000 29.050 ;
    END
  END rdata[469]

  PIN rdata[468]
    DIRECTION OUTPUT ;
    USE SIGNAL ;
    PORT
      LAYER met3 ;
        RECT 199.700 29.430 200.000 29.730 ;
    END
  END rdata[468]

  PIN rdata[467]
    DIRECTION OUTPUT ;
    USE SIGNAL ;
    PORT
      LAYER met3 ;
        RECT 199.700 30.110 200.000 30.410 ;
    END
  END rdata[467]

  PIN rdata[466]
    DIRECTION OUTPUT ;
    USE SIGNAL ;
    PORT
      LAYER met3 ;
        RECT 199.700 30.790 200.000 31.090 ;
    END
  END rdata[466]

  PIN rdata[465]
    DIRECTION OUTPUT ;
    USE SIGNAL ;
    PORT
      LAYER met3 ;
        RECT 199.700 31.470 200.000 31.770 ;
    END
  END rdata[465]

  PIN rdata[464]
    DIRECTION OUTPUT ;
    USE SIGNAL ;
    PORT
      LAYER met3 ;
        RECT 199.700 32.150 200.000 32.450 ;
    END
  END rdata[464]

  PIN rdata[463]
    DIRECTION OUTPUT ;
    USE SIGNAL ;
    PORT
      LAYER met3 ;
        RECT 199.700 32.830 200.000 33.130 ;
    END
  END rdata[463]

  PIN rdata[462]
    DIRECTION OUTPUT ;
    USE SIGNAL ;
    PORT
      LAYER met3 ;
        RECT 199.700 33.510 200.000 33.810 ;
    END
  END rdata[462]

  PIN rdata[461]
    DIRECTION OUTPUT ;
    USE SIGNAL ;
    PORT
      LAYER met3 ;
        RECT 199.700 34.190 200.000 34.490 ;
    END
  END rdata[461]

  PIN rdata[460]
    DIRECTION OUTPUT ;
    USE SIGNAL ;
    PORT
      LAYER met3 ;
        RECT 199.700 34.870 200.000 35.170 ;
    END
  END rdata[460]

  PIN rdata[459]
    DIRECTION OUTPUT ;
    USE SIGNAL ;
    PORT
      LAYER met3 ;
        RECT 199.700 35.550 200.000 35.850 ;
    END
  END rdata[459]

  PIN rdata[458]
    DIRECTION OUTPUT ;
    USE SIGNAL ;
    PORT
      LAYER met3 ;
        RECT 199.700 36.230 200.000 36.530 ;
    END
  END rdata[458]

  PIN rdata[457]
    DIRECTION OUTPUT ;
    USE SIGNAL ;
    PORT
      LAYER met3 ;
        RECT 199.700 36.910 200.000 37.210 ;
    END
  END rdata[457]

  PIN rdata[456]
    DIRECTION OUTPUT ;
    USE SIGNAL ;
    PORT
      LAYER met3 ;
        RECT 199.700 37.590 200.000 37.890 ;
    END
  END rdata[456]

  PIN rdata[455]
    DIRECTION OUTPUT ;
    USE SIGNAL ;
    PORT
      LAYER met3 ;
        RECT 199.700 38.270 200.000 38.570 ;
    END
  END rdata[455]

  PIN rdata[454]
    DIRECTION OUTPUT ;
    USE SIGNAL ;
    PORT
      LAYER met3 ;
        RECT 199.700 38.950 200.000 39.250 ;
    END
  END rdata[454]

  PIN rdata[453]
    DIRECTION OUTPUT ;
    USE SIGNAL ;
    PORT
      LAYER met3 ;
        RECT 199.700 39.630 200.000 39.930 ;
    END
  END rdata[453]

  PIN rdata[452]
    DIRECTION OUTPUT ;
    USE SIGNAL ;
    PORT
      LAYER met3 ;
        RECT 199.700 40.310 200.000 40.610 ;
    END
  END rdata[452]

  PIN rdata[451]
    DIRECTION OUTPUT ;
    USE SIGNAL ;
    PORT
      LAYER met3 ;
        RECT 199.700 40.990 200.000 41.290 ;
    END
  END rdata[451]

  PIN rdata[450]
    DIRECTION OUTPUT ;
    USE SIGNAL ;
    PORT
      LAYER met3 ;
        RECT 199.700 41.670 200.000 41.970 ;
    END
  END rdata[450]

  PIN rdata[449]
    DIRECTION OUTPUT ;
    USE SIGNAL ;
    PORT
      LAYER met3 ;
        RECT 199.700 42.350 200.000 42.650 ;
    END
  END rdata[449]

  PIN rdata[448]
    DIRECTION OUTPUT ;
    USE SIGNAL ;
    PORT
      LAYER met3 ;
        RECT 199.700 43.030 200.000 43.330 ;
    END
  END rdata[448]

  PIN rdata[447]
    DIRECTION OUTPUT ;
    USE SIGNAL ;
    PORT
      LAYER met3 ;
        RECT 199.700 43.710 200.000 44.010 ;
    END
  END rdata[447]

  PIN rdata[446]
    DIRECTION OUTPUT ;
    USE SIGNAL ;
    PORT
      LAYER met3 ;
        RECT 199.700 44.390 200.000 44.690 ;
    END
  END rdata[446]

  PIN rdata[445]
    DIRECTION OUTPUT ;
    USE SIGNAL ;
    PORT
      LAYER met3 ;
        RECT 199.700 45.070 200.000 45.370 ;
    END
  END rdata[445]

  PIN rdata[444]
    DIRECTION OUTPUT ;
    USE SIGNAL ;
    PORT
      LAYER met3 ;
        RECT 199.700 45.750 200.000 46.050 ;
    END
  END rdata[444]

  PIN rdata[443]
    DIRECTION OUTPUT ;
    USE SIGNAL ;
    PORT
      LAYER met3 ;
        RECT 199.700 46.430 200.000 46.730 ;
    END
  END rdata[443]

  PIN rdata[442]
    DIRECTION OUTPUT ;
    USE SIGNAL ;
    PORT
      LAYER met3 ;
        RECT 199.700 47.110 200.000 47.410 ;
    END
  END rdata[442]

  PIN rdata[441]
    DIRECTION OUTPUT ;
    USE SIGNAL ;
    PORT
      LAYER met3 ;
        RECT 199.700 47.790 200.000 48.090 ;
    END
  END rdata[441]

  PIN rdata[440]
    DIRECTION OUTPUT ;
    USE SIGNAL ;
    PORT
      LAYER met3 ;
        RECT 199.700 48.470 200.000 48.770 ;
    END
  END rdata[440]

  PIN rdata[439]
    DIRECTION OUTPUT ;
    USE SIGNAL ;
    PORT
      LAYER met3 ;
        RECT 199.700 49.150 200.000 49.450 ;
    END
  END rdata[439]

  PIN rdata[438]
    DIRECTION OUTPUT ;
    USE SIGNAL ;
    PORT
      LAYER met3 ;
        RECT 199.700 49.830 200.000 50.130 ;
    END
  END rdata[438]

  PIN rdata[437]
    DIRECTION OUTPUT ;
    USE SIGNAL ;
    PORT
      LAYER met3 ;
        RECT 199.700 50.510 200.000 50.810 ;
    END
  END rdata[437]

  PIN rdata[436]
    DIRECTION OUTPUT ;
    USE SIGNAL ;
    PORT
      LAYER met3 ;
        RECT 199.700 51.190 200.000 51.490 ;
    END
  END rdata[436]

  PIN rdata[435]
    DIRECTION OUTPUT ;
    USE SIGNAL ;
    PORT
      LAYER met3 ;
        RECT 199.700 51.870 200.000 52.170 ;
    END
  END rdata[435]

  PIN rdata[434]
    DIRECTION OUTPUT ;
    USE SIGNAL ;
    PORT
      LAYER met3 ;
        RECT 199.700 52.550 200.000 52.850 ;
    END
  END rdata[434]

  PIN rdata[433]
    DIRECTION OUTPUT ;
    USE SIGNAL ;
    PORT
      LAYER met3 ;
        RECT 199.700 53.230 200.000 53.530 ;
    END
  END rdata[433]

  PIN rdata[432]
    DIRECTION OUTPUT ;
    USE SIGNAL ;
    PORT
      LAYER met3 ;
        RECT 199.700 53.910 200.000 54.210 ;
    END
  END rdata[432]

  PIN rdata[431]
    DIRECTION OUTPUT ;
    USE SIGNAL ;
    PORT
      LAYER met3 ;
        RECT 199.700 54.590 200.000 54.890 ;
    END
  END rdata[431]

  PIN rdata[430]
    DIRECTION OUTPUT ;
    USE SIGNAL ;
    PORT
      LAYER met3 ;
        RECT 199.700 55.270 200.000 55.570 ;
    END
  END rdata[430]

  PIN rdata[429]
    DIRECTION OUTPUT ;
    USE SIGNAL ;
    PORT
      LAYER met3 ;
        RECT 199.700 55.950 200.000 56.250 ;
    END
  END rdata[429]

  PIN rdata[428]
    DIRECTION OUTPUT ;
    USE SIGNAL ;
    PORT
      LAYER met3 ;
        RECT 199.700 56.630 200.000 56.930 ;
    END
  END rdata[428]

  PIN rdata[427]
    DIRECTION OUTPUT ;
    USE SIGNAL ;
    PORT
      LAYER met3 ;
        RECT 199.700 57.310 200.000 57.610 ;
    END
  END rdata[427]

  PIN rdata[426]
    DIRECTION OUTPUT ;
    USE SIGNAL ;
    PORT
      LAYER met3 ;
        RECT 199.700 57.990 200.000 58.290 ;
    END
  END rdata[426]

  PIN rdata[425]
    DIRECTION OUTPUT ;
    USE SIGNAL ;
    PORT
      LAYER met3 ;
        RECT 199.700 58.670 200.000 58.970 ;
    END
  END rdata[425]

  PIN rdata[424]
    DIRECTION OUTPUT ;
    USE SIGNAL ;
    PORT
      LAYER met3 ;
        RECT 199.700 59.350 200.000 59.650 ;
    END
  END rdata[424]

  PIN rdata[423]
    DIRECTION OUTPUT ;
    USE SIGNAL ;
    PORT
      LAYER met3 ;
        RECT 199.700 60.030 200.000 60.330 ;
    END
  END rdata[423]

  PIN rdata[422]
    DIRECTION OUTPUT ;
    USE SIGNAL ;
    PORT
      LAYER met3 ;
        RECT 199.700 60.710 200.000 61.010 ;
    END
  END rdata[422]

  PIN rdata[421]
    DIRECTION OUTPUT ;
    USE SIGNAL ;
    PORT
      LAYER met3 ;
        RECT 199.700 61.390 200.000 61.690 ;
    END
  END rdata[421]

  PIN rdata[420]
    DIRECTION OUTPUT ;
    USE SIGNAL ;
    PORT
      LAYER met3 ;
        RECT 199.700 62.070 200.000 62.370 ;
    END
  END rdata[420]

  PIN rdata[419]
    DIRECTION OUTPUT ;
    USE SIGNAL ;
    PORT
      LAYER met3 ;
        RECT 199.700 62.750 200.000 63.050 ;
    END
  END rdata[419]

  PIN rdata[418]
    DIRECTION OUTPUT ;
    USE SIGNAL ;
    PORT
      LAYER met3 ;
        RECT 199.700 63.430 200.000 63.730 ;
    END
  END rdata[418]

  PIN rdata[417]
    DIRECTION OUTPUT ;
    USE SIGNAL ;
    PORT
      LAYER met3 ;
        RECT 199.700 64.110 200.000 64.410 ;
    END
  END rdata[417]

  PIN rdata[416]
    DIRECTION OUTPUT ;
    USE SIGNAL ;
    PORT
      LAYER met3 ;
        RECT 199.700 64.790 200.000 65.090 ;
    END
  END rdata[416]

  PIN rdata[415]
    DIRECTION OUTPUT ;
    USE SIGNAL ;
    PORT
      LAYER met3 ;
        RECT 199.700 65.470 200.000 65.770 ;
    END
  END rdata[415]

  PIN rdata[414]
    DIRECTION OUTPUT ;
    USE SIGNAL ;
    PORT
      LAYER met3 ;
        RECT 199.700 66.150 200.000 66.450 ;
    END
  END rdata[414]

  PIN rdata[413]
    DIRECTION OUTPUT ;
    USE SIGNAL ;
    PORT
      LAYER met3 ;
        RECT 199.700 66.830 200.000 67.130 ;
    END
  END rdata[413]

  PIN rdata[412]
    DIRECTION OUTPUT ;
    USE SIGNAL ;
    PORT
      LAYER met3 ;
        RECT 199.700 67.510 200.000 67.810 ;
    END
  END rdata[412]

  PIN rdata[411]
    DIRECTION OUTPUT ;
    USE SIGNAL ;
    PORT
      LAYER met3 ;
        RECT 199.700 68.190 200.000 68.490 ;
    END
  END rdata[411]

  PIN rdata[410]
    DIRECTION OUTPUT ;
    USE SIGNAL ;
    PORT
      LAYER met3 ;
        RECT 199.700 68.870 200.000 69.170 ;
    END
  END rdata[410]

  PIN rdata[409]
    DIRECTION OUTPUT ;
    USE SIGNAL ;
    PORT
      LAYER met3 ;
        RECT 199.700 69.550 200.000 69.850 ;
    END
  END rdata[409]

  PIN rdata[408]
    DIRECTION OUTPUT ;
    USE SIGNAL ;
    PORT
      LAYER met3 ;
        RECT 199.700 70.230 200.000 70.530 ;
    END
  END rdata[408]

  PIN rdata[407]
    DIRECTION OUTPUT ;
    USE SIGNAL ;
    PORT
      LAYER met3 ;
        RECT 199.700 70.910 200.000 71.210 ;
    END
  END rdata[407]

  PIN rdata[406]
    DIRECTION OUTPUT ;
    USE SIGNAL ;
    PORT
      LAYER met3 ;
        RECT 199.700 71.590 200.000 71.890 ;
    END
  END rdata[406]

  PIN rdata[405]
    DIRECTION OUTPUT ;
    USE SIGNAL ;
    PORT
      LAYER met3 ;
        RECT 199.700 72.270 200.000 72.570 ;
    END
  END rdata[405]

  PIN rdata[404]
    DIRECTION OUTPUT ;
    USE SIGNAL ;
    PORT
      LAYER met3 ;
        RECT 199.700 72.950 200.000 73.250 ;
    END
  END rdata[404]

  PIN rdata[403]
    DIRECTION OUTPUT ;
    USE SIGNAL ;
    PORT
      LAYER met3 ;
        RECT 199.700 73.630 200.000 73.930 ;
    END
  END rdata[403]

  PIN rdata[402]
    DIRECTION OUTPUT ;
    USE SIGNAL ;
    PORT
      LAYER met3 ;
        RECT 199.700 74.310 200.000 74.610 ;
    END
  END rdata[402]

  PIN rdata[401]
    DIRECTION OUTPUT ;
    USE SIGNAL ;
    PORT
      LAYER met3 ;
        RECT 199.700 74.990 200.000 75.290 ;
    END
  END rdata[401]

  PIN rdata[400]
    DIRECTION OUTPUT ;
    USE SIGNAL ;
    PORT
      LAYER met3 ;
        RECT 199.700 75.670 200.000 75.970 ;
    END
  END rdata[400]

  PIN rdata[399]
    DIRECTION OUTPUT ;
    USE SIGNAL ;
    PORT
      LAYER met3 ;
        RECT 199.700 76.350 200.000 76.650 ;
    END
  END rdata[399]

  PIN rdata[398]
    DIRECTION OUTPUT ;
    USE SIGNAL ;
    PORT
      LAYER met3 ;
        RECT 199.700 77.030 200.000 77.330 ;
    END
  END rdata[398]

  PIN rdata[397]
    DIRECTION OUTPUT ;
    USE SIGNAL ;
    PORT
      LAYER met3 ;
        RECT 199.700 77.710 200.000 78.010 ;
    END
  END rdata[397]

  PIN rdata[396]
    DIRECTION OUTPUT ;
    USE SIGNAL ;
    PORT
      LAYER met3 ;
        RECT 199.700 78.390 200.000 78.690 ;
    END
  END rdata[396]

  PIN rdata[395]
    DIRECTION OUTPUT ;
    USE SIGNAL ;
    PORT
      LAYER met3 ;
        RECT 199.700 79.070 200.000 79.370 ;
    END
  END rdata[395]

  PIN rdata[394]
    DIRECTION OUTPUT ;
    USE SIGNAL ;
    PORT
      LAYER met3 ;
        RECT 199.700 79.750 200.000 80.050 ;
    END
  END rdata[394]

  PIN rdata[393]
    DIRECTION OUTPUT ;
    USE SIGNAL ;
    PORT
      LAYER met3 ;
        RECT 199.700 80.430 200.000 80.730 ;
    END
  END rdata[393]

  PIN rdata[392]
    DIRECTION OUTPUT ;
    USE SIGNAL ;
    PORT
      LAYER met3 ;
        RECT 199.700 81.110 200.000 81.410 ;
    END
  END rdata[392]

  PIN rdata[391]
    DIRECTION OUTPUT ;
    USE SIGNAL ;
    PORT
      LAYER met3 ;
        RECT 199.700 81.790 200.000 82.090 ;
    END
  END rdata[391]

  PIN rdata[390]
    DIRECTION OUTPUT ;
    USE SIGNAL ;
    PORT
      LAYER met3 ;
        RECT 199.700 82.470 200.000 82.770 ;
    END
  END rdata[390]

  PIN rdata[389]
    DIRECTION OUTPUT ;
    USE SIGNAL ;
    PORT
      LAYER met3 ;
        RECT 199.700 83.150 200.000 83.450 ;
    END
  END rdata[389]

  PIN rdata[388]
    DIRECTION OUTPUT ;
    USE SIGNAL ;
    PORT
      LAYER met3 ;
        RECT 199.700 83.830 200.000 84.130 ;
    END
  END rdata[388]

  PIN rdata[387]
    DIRECTION OUTPUT ;
    USE SIGNAL ;
    PORT
      LAYER met3 ;
        RECT 199.700 84.510 200.000 84.810 ;
    END
  END rdata[387]

  PIN rdata[386]
    DIRECTION OUTPUT ;
    USE SIGNAL ;
    PORT
      LAYER met3 ;
        RECT 199.700 85.190 200.000 85.490 ;
    END
  END rdata[386]

  PIN rdata[385]
    DIRECTION OUTPUT ;
    USE SIGNAL ;
    PORT
      LAYER met3 ;
        RECT 199.700 85.870 200.000 86.170 ;
    END
  END rdata[385]

  PIN rdata[384]
    DIRECTION OUTPUT ;
    USE SIGNAL ;
    PORT
      LAYER met3 ;
        RECT 199.700 86.550 200.000 86.850 ;
    END
  END rdata[384]

  PIN rdata[383]
    DIRECTION OUTPUT ;
    USE SIGNAL ;
    PORT
      LAYER met3 ;
        RECT 199.700 87.230 200.000 87.530 ;
    END
  END rdata[383]

  PIN rdata[382]
    DIRECTION OUTPUT ;
    USE SIGNAL ;
    PORT
      LAYER met3 ;
        RECT 199.700 87.910 200.000 88.210 ;
    END
  END rdata[382]

  PIN rdata[381]
    DIRECTION OUTPUT ;
    USE SIGNAL ;
    PORT
      LAYER met3 ;
        RECT 199.700 88.590 200.000 88.890 ;
    END
  END rdata[381]

  PIN rdata[380]
    DIRECTION OUTPUT ;
    USE SIGNAL ;
    PORT
      LAYER met3 ;
        RECT 199.700 89.270 200.000 89.570 ;
    END
  END rdata[380]

  PIN rdata[379]
    DIRECTION OUTPUT ;
    USE SIGNAL ;
    PORT
      LAYER met3 ;
        RECT 199.700 89.950 200.000 90.250 ;
    END
  END rdata[379]

  PIN rdata[378]
    DIRECTION OUTPUT ;
    USE SIGNAL ;
    PORT
      LAYER met3 ;
        RECT 199.700 90.630 200.000 90.930 ;
    END
  END rdata[378]

  PIN rdata[377]
    DIRECTION OUTPUT ;
    USE SIGNAL ;
    PORT
      LAYER met3 ;
        RECT 199.700 91.310 200.000 91.610 ;
    END
  END rdata[377]

  PIN rdata[376]
    DIRECTION OUTPUT ;
    USE SIGNAL ;
    PORT
      LAYER met3 ;
        RECT 199.700 91.990 200.000 92.290 ;
    END
  END rdata[376]

  PIN rdata[375]
    DIRECTION OUTPUT ;
    USE SIGNAL ;
    PORT
      LAYER met3 ;
        RECT 199.700 92.670 200.000 92.970 ;
    END
  END rdata[375]

  PIN rdata[374]
    DIRECTION OUTPUT ;
    USE SIGNAL ;
    PORT
      LAYER met3 ;
        RECT 199.700 93.350 200.000 93.650 ;
    END
  END rdata[374]

  PIN rdata[373]
    DIRECTION OUTPUT ;
    USE SIGNAL ;
    PORT
      LAYER met3 ;
        RECT 199.700 94.030 200.000 94.330 ;
    END
  END rdata[373]

  PIN rdata[372]
    DIRECTION OUTPUT ;
    USE SIGNAL ;
    PORT
      LAYER met3 ;
        RECT 199.700 94.710 200.000 95.010 ;
    END
  END rdata[372]

  PIN rdata[371]
    DIRECTION OUTPUT ;
    USE SIGNAL ;
    PORT
      LAYER met3 ;
        RECT 199.700 95.390 200.000 95.690 ;
    END
  END rdata[371]

  PIN rdata[370]
    DIRECTION OUTPUT ;
    USE SIGNAL ;
    PORT
      LAYER met3 ;
        RECT 199.700 96.070 200.000 96.370 ;
    END
  END rdata[370]

  PIN rdata[369]
    DIRECTION OUTPUT ;
    USE SIGNAL ;
    PORT
      LAYER met3 ;
        RECT 199.700 96.750 200.000 97.050 ;
    END
  END rdata[369]

  PIN rdata[368]
    DIRECTION OUTPUT ;
    USE SIGNAL ;
    PORT
      LAYER met3 ;
        RECT 199.700 97.430 200.000 97.730 ;
    END
  END rdata[368]

  PIN rdata[367]
    DIRECTION OUTPUT ;
    USE SIGNAL ;
    PORT
      LAYER met3 ;
        RECT 199.700 98.110 200.000 98.410 ;
    END
  END rdata[367]

  PIN rdata[366]
    DIRECTION OUTPUT ;
    USE SIGNAL ;
    PORT
      LAYER met3 ;
        RECT 199.700 98.790 200.000 99.090 ;
    END
  END rdata[366]

  PIN rdata[365]
    DIRECTION OUTPUT ;
    USE SIGNAL ;
    PORT
      LAYER met3 ;
        RECT 199.700 99.470 200.000 99.770 ;
    END
  END rdata[365]

  PIN rdata[364]
    DIRECTION OUTPUT ;
    USE SIGNAL ;
    PORT
      LAYER met3 ;
        RECT 199.700 100.150 200.000 100.450 ;
    END
  END rdata[364]

  PIN rdata[363]
    DIRECTION OUTPUT ;
    USE SIGNAL ;
    PORT
      LAYER met3 ;
        RECT 199.700 100.830 200.000 101.130 ;
    END
  END rdata[363]

  PIN rdata[362]
    DIRECTION OUTPUT ;
    USE SIGNAL ;
    PORT
      LAYER met3 ;
        RECT 199.700 101.510 200.000 101.810 ;
    END
  END rdata[362]

  PIN rdata[361]
    DIRECTION OUTPUT ;
    USE SIGNAL ;
    PORT
      LAYER met3 ;
        RECT 199.700 102.190 200.000 102.490 ;
    END
  END rdata[361]

  PIN rdata[360]
    DIRECTION OUTPUT ;
    USE SIGNAL ;
    PORT
      LAYER met3 ;
        RECT 199.700 102.870 200.000 103.170 ;
    END
  END rdata[360]

  PIN rdata[359]
    DIRECTION OUTPUT ;
    USE SIGNAL ;
    PORT
      LAYER met3 ;
        RECT 199.700 103.550 200.000 103.850 ;
    END
  END rdata[359]

  PIN rdata[358]
    DIRECTION OUTPUT ;
    USE SIGNAL ;
    PORT
      LAYER met3 ;
        RECT 199.700 104.230 200.000 104.530 ;
    END
  END rdata[358]

  PIN rdata[357]
    DIRECTION OUTPUT ;
    USE SIGNAL ;
    PORT
      LAYER met3 ;
        RECT 199.700 104.910 200.000 105.210 ;
    END
  END rdata[357]

  PIN rdata[356]
    DIRECTION OUTPUT ;
    USE SIGNAL ;
    PORT
      LAYER met3 ;
        RECT 199.700 105.590 200.000 105.890 ;
    END
  END rdata[356]

  PIN rdata[355]
    DIRECTION OUTPUT ;
    USE SIGNAL ;
    PORT
      LAYER met3 ;
        RECT 199.700 106.270 200.000 106.570 ;
    END
  END rdata[355]

  PIN rdata[354]
    DIRECTION OUTPUT ;
    USE SIGNAL ;
    PORT
      LAYER met3 ;
        RECT 199.700 106.950 200.000 107.250 ;
    END
  END rdata[354]

  PIN rdata[353]
    DIRECTION OUTPUT ;
    USE SIGNAL ;
    PORT
      LAYER met3 ;
        RECT 199.700 107.630 200.000 107.930 ;
    END
  END rdata[353]

  PIN rdata[352]
    DIRECTION OUTPUT ;
    USE SIGNAL ;
    PORT
      LAYER met3 ;
        RECT 199.700 108.310 200.000 108.610 ;
    END
  END rdata[352]

  PIN rdata[351]
    DIRECTION OUTPUT ;
    USE SIGNAL ;
    PORT
      LAYER met3 ;
        RECT 199.700 108.990 200.000 109.290 ;
    END
  END rdata[351]

  PIN rdata[350]
    DIRECTION OUTPUT ;
    USE SIGNAL ;
    PORT
      LAYER met3 ;
        RECT 199.700 109.670 200.000 109.970 ;
    END
  END rdata[350]

  PIN rdata[349]
    DIRECTION OUTPUT ;
    USE SIGNAL ;
    PORT
      LAYER met3 ;
        RECT 199.700 110.350 200.000 110.650 ;
    END
  END rdata[349]

  PIN rdata[348]
    DIRECTION OUTPUT ;
    USE SIGNAL ;
    PORT
      LAYER met3 ;
        RECT 199.700 111.030 200.000 111.330 ;
    END
  END rdata[348]

  PIN rdata[347]
    DIRECTION OUTPUT ;
    USE SIGNAL ;
    PORT
      LAYER met3 ;
        RECT 199.700 111.710 200.000 112.010 ;
    END
  END rdata[347]

  PIN rdata[346]
    DIRECTION OUTPUT ;
    USE SIGNAL ;
    PORT
      LAYER met3 ;
        RECT 199.700 112.390 200.000 112.690 ;
    END
  END rdata[346]

  PIN rdata[345]
    DIRECTION OUTPUT ;
    USE SIGNAL ;
    PORT
      LAYER met3 ;
        RECT 199.700 113.070 200.000 113.370 ;
    END
  END rdata[345]

  PIN rdata[344]
    DIRECTION OUTPUT ;
    USE SIGNAL ;
    PORT
      LAYER met3 ;
        RECT 199.700 113.750 200.000 114.050 ;
    END
  END rdata[344]

  PIN rdata[343]
    DIRECTION OUTPUT ;
    USE SIGNAL ;
    PORT
      LAYER met3 ;
        RECT 199.700 114.430 200.000 114.730 ;
    END
  END rdata[343]

  PIN rdata[342]
    DIRECTION OUTPUT ;
    USE SIGNAL ;
    PORT
      LAYER met3 ;
        RECT 199.700 115.110 200.000 115.410 ;
    END
  END rdata[342]

  PIN rdata[341]
    DIRECTION OUTPUT ;
    USE SIGNAL ;
    PORT
      LAYER met3 ;
        RECT 199.700 115.790 200.000 116.090 ;
    END
  END rdata[341]

  PIN rdata[340]
    DIRECTION OUTPUT ;
    USE SIGNAL ;
    PORT
      LAYER met3 ;
        RECT 199.700 116.470 200.000 116.770 ;
    END
  END rdata[340]

  PIN rdata[339]
    DIRECTION OUTPUT ;
    USE SIGNAL ;
    PORT
      LAYER met3 ;
        RECT 199.700 117.150 200.000 117.450 ;
    END
  END rdata[339]

  PIN rdata[338]
    DIRECTION OUTPUT ;
    USE SIGNAL ;
    PORT
      LAYER met3 ;
        RECT 199.700 117.830 200.000 118.130 ;
    END
  END rdata[338]

  PIN rdata[337]
    DIRECTION OUTPUT ;
    USE SIGNAL ;
    PORT
      LAYER met3 ;
        RECT 199.700 118.510 200.000 118.810 ;
    END
  END rdata[337]

  PIN rdata[336]
    DIRECTION OUTPUT ;
    USE SIGNAL ;
    PORT
      LAYER met3 ;
        RECT 199.700 119.190 200.000 119.490 ;
    END
  END rdata[336]

  PIN rdata[335]
    DIRECTION OUTPUT ;
    USE SIGNAL ;
    PORT
      LAYER met3 ;
        RECT 199.700 119.870 200.000 120.170 ;
    END
  END rdata[335]

  PIN rdata[334]
    DIRECTION OUTPUT ;
    USE SIGNAL ;
    PORT
      LAYER met3 ;
        RECT 199.700 120.550 200.000 120.850 ;
    END
  END rdata[334]

  PIN rdata[333]
    DIRECTION OUTPUT ;
    USE SIGNAL ;
    PORT
      LAYER met3 ;
        RECT 199.700 121.230 200.000 121.530 ;
    END
  END rdata[333]

  PIN rdata[332]
    DIRECTION OUTPUT ;
    USE SIGNAL ;
    PORT
      LAYER met3 ;
        RECT 199.700 121.910 200.000 122.210 ;
    END
  END rdata[332]

  PIN rdata[331]
    DIRECTION OUTPUT ;
    USE SIGNAL ;
    PORT
      LAYER met3 ;
        RECT 199.700 122.590 200.000 122.890 ;
    END
  END rdata[331]

  PIN rdata[330]
    DIRECTION OUTPUT ;
    USE SIGNAL ;
    PORT
      LAYER met3 ;
        RECT 199.700 123.270 200.000 123.570 ;
    END
  END rdata[330]

  PIN rdata[329]
    DIRECTION OUTPUT ;
    USE SIGNAL ;
    PORT
      LAYER met3 ;
        RECT 199.700 123.950 200.000 124.250 ;
    END
  END rdata[329]

  PIN rdata[328]
    DIRECTION OUTPUT ;
    USE SIGNAL ;
    PORT
      LAYER met3 ;
        RECT 199.700 124.630 200.000 124.930 ;
    END
  END rdata[328]

  PIN rdata[327]
    DIRECTION OUTPUT ;
    USE SIGNAL ;
    PORT
      LAYER met3 ;
        RECT 199.700 125.310 200.000 125.610 ;
    END
  END rdata[327]

  PIN rdata[326]
    DIRECTION OUTPUT ;
    USE SIGNAL ;
    PORT
      LAYER met3 ;
        RECT 199.700 125.990 200.000 126.290 ;
    END
  END rdata[326]

  PIN rdata[325]
    DIRECTION OUTPUT ;
    USE SIGNAL ;
    PORT
      LAYER met3 ;
        RECT 199.700 126.670 200.000 126.970 ;
    END
  END rdata[325]

  PIN rdata[324]
    DIRECTION OUTPUT ;
    USE SIGNAL ;
    PORT
      LAYER met3 ;
        RECT 199.700 127.350 200.000 127.650 ;
    END
  END rdata[324]

  PIN rdata[323]
    DIRECTION OUTPUT ;
    USE SIGNAL ;
    PORT
      LAYER met3 ;
        RECT 199.700 128.030 200.000 128.330 ;
    END
  END rdata[323]

  PIN rdata[322]
    DIRECTION OUTPUT ;
    USE SIGNAL ;
    PORT
      LAYER met3 ;
        RECT 199.700 128.710 200.000 129.010 ;
    END
  END rdata[322]

  PIN rdata[321]
    DIRECTION OUTPUT ;
    USE SIGNAL ;
    PORT
      LAYER met3 ;
        RECT 199.700 129.390 200.000 129.690 ;
    END
  END rdata[321]

  PIN rdata[320]
    DIRECTION OUTPUT ;
    USE SIGNAL ;
    PORT
      LAYER met3 ;
        RECT 199.700 130.070 200.000 130.370 ;
    END
  END rdata[320]

  PIN rdata[319]
    DIRECTION OUTPUT ;
    USE SIGNAL ;
    PORT
      LAYER met3 ;
        RECT 199.700 130.750 200.000 131.050 ;
    END
  END rdata[319]

  PIN rdata[318]
    DIRECTION OUTPUT ;
    USE SIGNAL ;
    PORT
      LAYER met3 ;
        RECT 199.700 131.430 200.000 131.730 ;
    END
  END rdata[318]

  PIN rdata[317]
    DIRECTION OUTPUT ;
    USE SIGNAL ;
    PORT
      LAYER met3 ;
        RECT 199.700 132.110 200.000 132.410 ;
    END
  END rdata[317]

  PIN rdata[316]
    DIRECTION OUTPUT ;
    USE SIGNAL ;
    PORT
      LAYER met3 ;
        RECT 199.700 132.790 200.000 133.090 ;
    END
  END rdata[316]

  PIN rdata[315]
    DIRECTION OUTPUT ;
    USE SIGNAL ;
    PORT
      LAYER met3 ;
        RECT 199.700 133.470 200.000 133.770 ;
    END
  END rdata[315]

  PIN rdata[314]
    DIRECTION OUTPUT ;
    USE SIGNAL ;
    PORT
      LAYER met3 ;
        RECT 199.700 134.150 200.000 134.450 ;
    END
  END rdata[314]

  PIN rdata[313]
    DIRECTION OUTPUT ;
    USE SIGNAL ;
    PORT
      LAYER met3 ;
        RECT 199.700 134.830 200.000 135.130 ;
    END
  END rdata[313]

  PIN rdata[312]
    DIRECTION OUTPUT ;
    USE SIGNAL ;
    PORT
      LAYER met3 ;
        RECT 199.700 135.510 200.000 135.810 ;
    END
  END rdata[312]

  PIN rdata[311]
    DIRECTION OUTPUT ;
    USE SIGNAL ;
    PORT
      LAYER met3 ;
        RECT 199.700 136.190 200.000 136.490 ;
    END
  END rdata[311]

  PIN rdata[310]
    DIRECTION OUTPUT ;
    USE SIGNAL ;
    PORT
      LAYER met3 ;
        RECT 199.700 136.870 200.000 137.170 ;
    END
  END rdata[310]

  PIN rdata[309]
    DIRECTION OUTPUT ;
    USE SIGNAL ;
    PORT
      LAYER met3 ;
        RECT 199.700 137.550 200.000 137.850 ;
    END
  END rdata[309]

  PIN rdata[308]
    DIRECTION OUTPUT ;
    USE SIGNAL ;
    PORT
      LAYER met3 ;
        RECT 199.700 138.230 200.000 138.530 ;
    END
  END rdata[308]

  PIN rdata[307]
    DIRECTION OUTPUT ;
    USE SIGNAL ;
    PORT
      LAYER met3 ;
        RECT 199.700 138.910 200.000 139.210 ;
    END
  END rdata[307]

  PIN rdata[306]
    DIRECTION OUTPUT ;
    USE SIGNAL ;
    PORT
      LAYER met3 ;
        RECT 199.700 139.590 200.000 139.890 ;
    END
  END rdata[306]

  PIN rdata[305]
    DIRECTION OUTPUT ;
    USE SIGNAL ;
    PORT
      LAYER met3 ;
        RECT 199.700 140.270 200.000 140.570 ;
    END
  END rdata[305]

  PIN rdata[304]
    DIRECTION OUTPUT ;
    USE SIGNAL ;
    PORT
      LAYER met3 ;
        RECT 199.700 140.950 200.000 141.250 ;
    END
  END rdata[304]

  PIN rdata[303]
    DIRECTION OUTPUT ;
    USE SIGNAL ;
    PORT
      LAYER met3 ;
        RECT 199.700 141.630 200.000 141.930 ;
    END
  END rdata[303]

  PIN rdata[302]
    DIRECTION OUTPUT ;
    USE SIGNAL ;
    PORT
      LAYER met3 ;
        RECT 199.700 142.310 200.000 142.610 ;
    END
  END rdata[302]

  PIN rdata[301]
    DIRECTION OUTPUT ;
    USE SIGNAL ;
    PORT
      LAYER met3 ;
        RECT 199.700 142.990 200.000 143.290 ;
    END
  END rdata[301]

  PIN rdata[300]
    DIRECTION OUTPUT ;
    USE SIGNAL ;
    PORT
      LAYER met3 ;
        RECT 199.700 143.670 200.000 143.970 ;
    END
  END rdata[300]

  PIN rdata[299]
    DIRECTION OUTPUT ;
    USE SIGNAL ;
    PORT
      LAYER met3 ;
        RECT 199.700 144.350 200.000 144.650 ;
    END
  END rdata[299]

  PIN rdata[298]
    DIRECTION OUTPUT ;
    USE SIGNAL ;
    PORT
      LAYER met3 ;
        RECT 199.700 145.030 200.000 145.330 ;
    END
  END rdata[298]

  PIN rdata[297]
    DIRECTION OUTPUT ;
    USE SIGNAL ;
    PORT
      LAYER met3 ;
        RECT 199.700 145.710 200.000 146.010 ;
    END
  END rdata[297]

  PIN rdata[296]
    DIRECTION OUTPUT ;
    USE SIGNAL ;
    PORT
      LAYER met3 ;
        RECT 199.700 146.390 200.000 146.690 ;
    END
  END rdata[296]

  PIN rdata[295]
    DIRECTION OUTPUT ;
    USE SIGNAL ;
    PORT
      LAYER met3 ;
        RECT 199.700 147.070 200.000 147.370 ;
    END
  END rdata[295]

  PIN rdata[294]
    DIRECTION OUTPUT ;
    USE SIGNAL ;
    PORT
      LAYER met3 ;
        RECT 199.700 147.750 200.000 148.050 ;
    END
  END rdata[294]

  PIN rdata[293]
    DIRECTION OUTPUT ;
    USE SIGNAL ;
    PORT
      LAYER met3 ;
        RECT 199.700 148.430 200.000 148.730 ;
    END
  END rdata[293]

  PIN rdata[292]
    DIRECTION OUTPUT ;
    USE SIGNAL ;
    PORT
      LAYER met3 ;
        RECT 199.700 149.110 200.000 149.410 ;
    END
  END rdata[292]

  PIN rdata[291]
    DIRECTION OUTPUT ;
    USE SIGNAL ;
    PORT
      LAYER met3 ;
        RECT 199.700 149.790 200.000 150.090 ;
    END
  END rdata[291]

  PIN rdata[290]
    DIRECTION OUTPUT ;
    USE SIGNAL ;
    PORT
      LAYER met3 ;
        RECT 199.700 150.470 200.000 150.770 ;
    END
  END rdata[290]

  PIN rdata[289]
    DIRECTION OUTPUT ;
    USE SIGNAL ;
    PORT
      LAYER met3 ;
        RECT 199.700 151.150 200.000 151.450 ;
    END
  END rdata[289]

  PIN rdata[288]
    DIRECTION OUTPUT ;
    USE SIGNAL ;
    PORT
      LAYER met3 ;
        RECT 199.700 151.830 200.000 152.130 ;
    END
  END rdata[288]

  PIN rdata[287]
    DIRECTION OUTPUT ;
    USE SIGNAL ;
    PORT
      LAYER met3 ;
        RECT 199.700 152.510 200.000 152.810 ;
    END
  END rdata[287]

  PIN rdata[286]
    DIRECTION OUTPUT ;
    USE SIGNAL ;
    PORT
      LAYER met3 ;
        RECT 199.700 153.190 200.000 153.490 ;
    END
  END rdata[286]

  PIN rdata[285]
    DIRECTION OUTPUT ;
    USE SIGNAL ;
    PORT
      LAYER met3 ;
        RECT 199.700 153.870 200.000 154.170 ;
    END
  END rdata[285]

  PIN rdata[284]
    DIRECTION OUTPUT ;
    USE SIGNAL ;
    PORT
      LAYER met3 ;
        RECT 199.700 154.550 200.000 154.850 ;
    END
  END rdata[284]

  PIN rdata[283]
    DIRECTION OUTPUT ;
    USE SIGNAL ;
    PORT
      LAYER met3 ;
        RECT 199.700 155.230 200.000 155.530 ;
    END
  END rdata[283]

  PIN rdata[282]
    DIRECTION OUTPUT ;
    USE SIGNAL ;
    PORT
      LAYER met3 ;
        RECT 199.700 155.910 200.000 156.210 ;
    END
  END rdata[282]

  PIN rdata[281]
    DIRECTION OUTPUT ;
    USE SIGNAL ;
    PORT
      LAYER met3 ;
        RECT 199.700 156.590 200.000 156.890 ;
    END
  END rdata[281]

  PIN rdata[280]
    DIRECTION OUTPUT ;
    USE SIGNAL ;
    PORT
      LAYER met3 ;
        RECT 199.700 157.270 200.000 157.570 ;
    END
  END rdata[280]

  PIN rdata[279]
    DIRECTION OUTPUT ;
    USE SIGNAL ;
    PORT
      LAYER met3 ;
        RECT 199.700 157.950 200.000 158.250 ;
    END
  END rdata[279]

  PIN rdata[278]
    DIRECTION OUTPUT ;
    USE SIGNAL ;
    PORT
      LAYER met3 ;
        RECT 199.700 158.630 200.000 158.930 ;
    END
  END rdata[278]

  PIN rdata[277]
    DIRECTION OUTPUT ;
    USE SIGNAL ;
    PORT
      LAYER met3 ;
        RECT 199.700 159.310 200.000 159.610 ;
    END
  END rdata[277]

  PIN rdata[276]
    DIRECTION OUTPUT ;
    USE SIGNAL ;
    PORT
      LAYER met3 ;
        RECT 199.700 159.990 200.000 160.290 ;
    END
  END rdata[276]

  PIN rdata[275]
    DIRECTION OUTPUT ;
    USE SIGNAL ;
    PORT
      LAYER met3 ;
        RECT 199.700 160.670 200.000 160.970 ;
    END
  END rdata[275]

  PIN rdata[274]
    DIRECTION OUTPUT ;
    USE SIGNAL ;
    PORT
      LAYER met3 ;
        RECT 199.700 161.350 200.000 161.650 ;
    END
  END rdata[274]

  PIN rdata[273]
    DIRECTION OUTPUT ;
    USE SIGNAL ;
    PORT
      LAYER met3 ;
        RECT 199.700 162.030 200.000 162.330 ;
    END
  END rdata[273]

  PIN rdata[272]
    DIRECTION OUTPUT ;
    USE SIGNAL ;
    PORT
      LAYER met3 ;
        RECT 199.700 162.710 200.000 163.010 ;
    END
  END rdata[272]

  PIN rdata[271]
    DIRECTION OUTPUT ;
    USE SIGNAL ;
    PORT
      LAYER met3 ;
        RECT 199.700 163.390 200.000 163.690 ;
    END
  END rdata[271]

  PIN rdata[270]
    DIRECTION OUTPUT ;
    USE SIGNAL ;
    PORT
      LAYER met3 ;
        RECT 199.700 164.070 200.000 164.370 ;
    END
  END rdata[270]

  PIN rdata[269]
    DIRECTION OUTPUT ;
    USE SIGNAL ;
    PORT
      LAYER met3 ;
        RECT 199.700 164.750 200.000 165.050 ;
    END
  END rdata[269]

  PIN rdata[268]
    DIRECTION OUTPUT ;
    USE SIGNAL ;
    PORT
      LAYER met3 ;
        RECT 199.700 165.430 200.000 165.730 ;
    END
  END rdata[268]

  PIN rdata[267]
    DIRECTION OUTPUT ;
    USE SIGNAL ;
    PORT
      LAYER met3 ;
        RECT 199.700 166.110 200.000 166.410 ;
    END
  END rdata[267]

  PIN rdata[266]
    DIRECTION OUTPUT ;
    USE SIGNAL ;
    PORT
      LAYER met3 ;
        RECT 199.700 166.790 200.000 167.090 ;
    END
  END rdata[266]

  PIN rdata[265]
    DIRECTION OUTPUT ;
    USE SIGNAL ;
    PORT
      LAYER met3 ;
        RECT 199.700 167.470 200.000 167.770 ;
    END
  END rdata[265]

  PIN rdata[264]
    DIRECTION OUTPUT ;
    USE SIGNAL ;
    PORT
      LAYER met3 ;
        RECT 199.700 168.150 200.000 168.450 ;
    END
  END rdata[264]

  PIN rdata[263]
    DIRECTION OUTPUT ;
    USE SIGNAL ;
    PORT
      LAYER met3 ;
        RECT 199.700 168.830 200.000 169.130 ;
    END
  END rdata[263]

  PIN rdata[262]
    DIRECTION OUTPUT ;
    USE SIGNAL ;
    PORT
      LAYER met3 ;
        RECT 199.700 169.510 200.000 169.810 ;
    END
  END rdata[262]

  PIN rdata[261]
    DIRECTION OUTPUT ;
    USE SIGNAL ;
    PORT
      LAYER met3 ;
        RECT 199.700 170.190 200.000 170.490 ;
    END
  END rdata[261]

  PIN rdata[260]
    DIRECTION OUTPUT ;
    USE SIGNAL ;
    PORT
      LAYER met3 ;
        RECT 199.700 170.870 200.000 171.170 ;
    END
  END rdata[260]

  PIN rdata[259]
    DIRECTION OUTPUT ;
    USE SIGNAL ;
    PORT
      LAYER met3 ;
        RECT 199.700 171.550 200.000 171.850 ;
    END
  END rdata[259]

  PIN rdata[258]
    DIRECTION OUTPUT ;
    USE SIGNAL ;
    PORT
      LAYER met3 ;
        RECT 199.700 172.230 200.000 172.530 ;
    END
  END rdata[258]

  PIN rdata[257]
    DIRECTION OUTPUT ;
    USE SIGNAL ;
    PORT
      LAYER met3 ;
        RECT 199.700 172.910 200.000 173.210 ;
    END
  END rdata[257]

  PIN rdata[256]
    DIRECTION OUTPUT ;
    USE SIGNAL ;
    PORT
      LAYER met3 ;
        RECT 199.700 173.590 200.000 173.890 ;
    END
  END rdata[256]

  PIN rdata[255]
    DIRECTION OUTPUT ;
    USE SIGNAL ;
    PORT
      LAYER met3 ;
        RECT 199.700 174.270 200.000 174.570 ;
    END
  END rdata[255]

  PIN rdata[254]
    DIRECTION OUTPUT ;
    USE SIGNAL ;
    PORT
      LAYER met3 ;
        RECT 199.700 174.950 200.000 175.250 ;
    END
  END rdata[254]

  PIN rdata[253]
    DIRECTION OUTPUT ;
    USE SIGNAL ;
    PORT
      LAYER met3 ;
        RECT 199.700 175.630 200.000 175.930 ;
    END
  END rdata[253]

  PIN rdata[252]
    DIRECTION OUTPUT ;
    USE SIGNAL ;
    PORT
      LAYER met3 ;
        RECT 199.700 176.310 200.000 176.610 ;
    END
  END rdata[252]

  PIN rdata[251]
    DIRECTION OUTPUT ;
    USE SIGNAL ;
    PORT
      LAYER met3 ;
        RECT 199.700 176.990 200.000 177.290 ;
    END
  END rdata[251]

  PIN rdata[250]
    DIRECTION OUTPUT ;
    USE SIGNAL ;
    PORT
      LAYER met3 ;
        RECT 199.700 177.670 200.000 177.970 ;
    END
  END rdata[250]

  PIN rdata[249]
    DIRECTION OUTPUT ;
    USE SIGNAL ;
    PORT
      LAYER met3 ;
        RECT 199.700 178.350 200.000 178.650 ;
    END
  END rdata[249]

  PIN rdata[248]
    DIRECTION OUTPUT ;
    USE SIGNAL ;
    PORT
      LAYER met3 ;
        RECT 199.700 179.030 200.000 179.330 ;
    END
  END rdata[248]

  PIN rdata[247]
    DIRECTION OUTPUT ;
    USE SIGNAL ;
    PORT
      LAYER met3 ;
        RECT 199.700 179.710 200.000 180.010 ;
    END
  END rdata[247]

  PIN rdata[246]
    DIRECTION OUTPUT ;
    USE SIGNAL ;
    PORT
      LAYER met3 ;
        RECT 199.700 180.390 200.000 180.690 ;
    END
  END rdata[246]

  PIN rdata[245]
    DIRECTION OUTPUT ;
    USE SIGNAL ;
    PORT
      LAYER met3 ;
        RECT 199.700 181.070 200.000 181.370 ;
    END
  END rdata[245]

  PIN rdata[244]
    DIRECTION OUTPUT ;
    USE SIGNAL ;
    PORT
      LAYER met3 ;
        RECT 199.700 181.750 200.000 182.050 ;
    END
  END rdata[244]

  PIN rdata[243]
    DIRECTION OUTPUT ;
    USE SIGNAL ;
    PORT
      LAYER met3 ;
        RECT 199.700 182.430 200.000 182.730 ;
    END
  END rdata[243]

  PIN rdata[242]
    DIRECTION OUTPUT ;
    USE SIGNAL ;
    PORT
      LAYER met3 ;
        RECT 199.700 183.110 200.000 183.410 ;
    END
  END rdata[242]

  PIN rdata[241]
    DIRECTION OUTPUT ;
    USE SIGNAL ;
    PORT
      LAYER met3 ;
        RECT 199.700 183.790 200.000 184.090 ;
    END
  END rdata[241]

  PIN rdata[240]
    DIRECTION OUTPUT ;
    USE SIGNAL ;
    PORT
      LAYER met3 ;
        RECT 199.700 184.470 200.000 184.770 ;
    END
  END rdata[240]

  PIN rdata[239]
    DIRECTION OUTPUT ;
    USE SIGNAL ;
    PORT
      LAYER met3 ;
        RECT 199.700 185.150 200.000 185.450 ;
    END
  END rdata[239]

  PIN rdata[238]
    DIRECTION OUTPUT ;
    USE SIGNAL ;
    PORT
      LAYER met3 ;
        RECT 199.700 185.830 200.000 186.130 ;
    END
  END rdata[238]

  PIN rdata[237]
    DIRECTION OUTPUT ;
    USE SIGNAL ;
    PORT
      LAYER met3 ;
        RECT 199.700 186.510 200.000 186.810 ;
    END
  END rdata[237]

  PIN rdata[236]
    DIRECTION OUTPUT ;
    USE SIGNAL ;
    PORT
      LAYER met3 ;
        RECT 199.700 187.190 200.000 187.490 ;
    END
  END rdata[236]

  PIN rdata[235]
    DIRECTION OUTPUT ;
    USE SIGNAL ;
    PORT
      LAYER met3 ;
        RECT 199.700 187.870 200.000 188.170 ;
    END
  END rdata[235]

  PIN rdata[234]
    DIRECTION OUTPUT ;
    USE SIGNAL ;
    PORT
      LAYER met3 ;
        RECT 199.700 188.550 200.000 188.850 ;
    END
  END rdata[234]

  PIN rdata[233]
    DIRECTION OUTPUT ;
    USE SIGNAL ;
    PORT
      LAYER met3 ;
        RECT 199.700 189.230 200.000 189.530 ;
    END
  END rdata[233]

  PIN rdata[232]
    DIRECTION OUTPUT ;
    USE SIGNAL ;
    PORT
      LAYER met3 ;
        RECT 199.700 189.910 200.000 190.210 ;
    END
  END rdata[232]

  PIN rdata[231]
    DIRECTION OUTPUT ;
    USE SIGNAL ;
    PORT
      LAYER met3 ;
        RECT 199.700 190.590 200.000 190.890 ;
    END
  END rdata[231]

  PIN rdata[230]
    DIRECTION OUTPUT ;
    USE SIGNAL ;
    PORT
      LAYER met3 ;
        RECT 199.700 191.270 200.000 191.570 ;
    END
  END rdata[230]

  PIN rdata[229]
    DIRECTION OUTPUT ;
    USE SIGNAL ;
    PORT
      LAYER met3 ;
        RECT 199.700 191.950 200.000 192.250 ;
    END
  END rdata[229]

  PIN rdata[228]
    DIRECTION OUTPUT ;
    USE SIGNAL ;
    PORT
      LAYER met3 ;
        RECT 199.700 192.630 200.000 192.930 ;
    END
  END rdata[228]

  PIN rdata[227]
    DIRECTION OUTPUT ;
    USE SIGNAL ;
    PORT
      LAYER met3 ;
        RECT 199.700 193.310 200.000 193.610 ;
    END
  END rdata[227]

  PIN rdata[226]
    DIRECTION OUTPUT ;
    USE SIGNAL ;
    PORT
      LAYER met3 ;
        RECT 199.700 193.990 200.000 194.290 ;
    END
  END rdata[226]

  PIN rdata[225]
    DIRECTION OUTPUT ;
    USE SIGNAL ;
    PORT
      LAYER met3 ;
        RECT 199.700 194.670 200.000 194.970 ;
    END
  END rdata[225]

  PIN rdata[224]
    DIRECTION OUTPUT ;
    USE SIGNAL ;
    PORT
      LAYER met3 ;
        RECT 199.700 195.350 200.000 195.650 ;
    END
  END rdata[224]

  PIN rdata[223]
    DIRECTION OUTPUT ;
    USE SIGNAL ;
    PORT
      LAYER met3 ;
        RECT 199.700 196.030 200.000 196.330 ;
    END
  END rdata[223]

  PIN rdata[222]
    DIRECTION OUTPUT ;
    USE SIGNAL ;
    PORT
      LAYER met3 ;
        RECT 199.700 196.710 200.000 197.010 ;
    END
  END rdata[222]

  PIN rdata[221]
    DIRECTION OUTPUT ;
    USE SIGNAL ;
    PORT
      LAYER met3 ;
        RECT 199.700 197.390 200.000 197.690 ;
    END
  END rdata[221]

  PIN rdata[220]
    DIRECTION OUTPUT ;
    USE SIGNAL ;
    PORT
      LAYER met3 ;
        RECT 199.700 198.070 200.000 198.370 ;
    END
  END rdata[220]

  PIN rdata[219]
    DIRECTION OUTPUT ;
    USE SIGNAL ;
    PORT
      LAYER met3 ;
        RECT 199.700 198.750 200.000 199.050 ;
    END
  END rdata[219]

  PIN rdata[218]
    DIRECTION OUTPUT ;
    USE SIGNAL ;
    PORT
      LAYER met3 ;
        RECT 199.700 199.430 200.000 199.730 ;
    END
  END rdata[218]

  PIN rdata[217]
    DIRECTION OUTPUT ;
    USE SIGNAL ;
    PORT
      LAYER met3 ;
        RECT 199.700 200.110 200.000 200.410 ;
    END
  END rdata[217]

  PIN rdata[216]
    DIRECTION OUTPUT ;
    USE SIGNAL ;
    PORT
      LAYER met3 ;
        RECT 199.700 200.790 200.000 201.090 ;
    END
  END rdata[216]

  PIN rdata[215]
    DIRECTION OUTPUT ;
    USE SIGNAL ;
    PORT
      LAYER met3 ;
        RECT 199.700 201.470 200.000 201.770 ;
    END
  END rdata[215]

  PIN rdata[214]
    DIRECTION OUTPUT ;
    USE SIGNAL ;
    PORT
      LAYER met3 ;
        RECT 199.700 202.150 200.000 202.450 ;
    END
  END rdata[214]

  PIN rdata[213]
    DIRECTION OUTPUT ;
    USE SIGNAL ;
    PORT
      LAYER met3 ;
        RECT 199.700 202.830 200.000 203.130 ;
    END
  END rdata[213]

  PIN rdata[212]
    DIRECTION OUTPUT ;
    USE SIGNAL ;
    PORT
      LAYER met3 ;
        RECT 199.700 203.510 200.000 203.810 ;
    END
  END rdata[212]

  PIN rdata[211]
    DIRECTION OUTPUT ;
    USE SIGNAL ;
    PORT
      LAYER met3 ;
        RECT 199.700 204.190 200.000 204.490 ;
    END
  END rdata[211]

  PIN rdata[210]
    DIRECTION OUTPUT ;
    USE SIGNAL ;
    PORT
      LAYER met3 ;
        RECT 199.700 204.870 200.000 205.170 ;
    END
  END rdata[210]

  PIN rdata[209]
    DIRECTION OUTPUT ;
    USE SIGNAL ;
    PORT
      LAYER met3 ;
        RECT 199.700 205.550 200.000 205.850 ;
    END
  END rdata[209]

  PIN rdata[208]
    DIRECTION OUTPUT ;
    USE SIGNAL ;
    PORT
      LAYER met3 ;
        RECT 199.700 206.230 200.000 206.530 ;
    END
  END rdata[208]

  PIN rdata[207]
    DIRECTION OUTPUT ;
    USE SIGNAL ;
    PORT
      LAYER met3 ;
        RECT 199.700 206.910 200.000 207.210 ;
    END
  END rdata[207]

  PIN rdata[206]
    DIRECTION OUTPUT ;
    USE SIGNAL ;
    PORT
      LAYER met3 ;
        RECT 199.700 207.590 200.000 207.890 ;
    END
  END rdata[206]

  PIN rdata[205]
    DIRECTION OUTPUT ;
    USE SIGNAL ;
    PORT
      LAYER met3 ;
        RECT 199.700 208.270 200.000 208.570 ;
    END
  END rdata[205]

  PIN rdata[204]
    DIRECTION OUTPUT ;
    USE SIGNAL ;
    PORT
      LAYER met3 ;
        RECT 199.700 208.950 200.000 209.250 ;
    END
  END rdata[204]

  PIN rdata[203]
    DIRECTION OUTPUT ;
    USE SIGNAL ;
    PORT
      LAYER met3 ;
        RECT 199.700 209.630 200.000 209.930 ;
    END
  END rdata[203]

  PIN rdata[202]
    DIRECTION OUTPUT ;
    USE SIGNAL ;
    PORT
      LAYER met3 ;
        RECT 199.700 210.310 200.000 210.610 ;
    END
  END rdata[202]

  PIN rdata[201]
    DIRECTION OUTPUT ;
    USE SIGNAL ;
    PORT
      LAYER met3 ;
        RECT 199.700 210.990 200.000 211.290 ;
    END
  END rdata[201]

  PIN rdata[200]
    DIRECTION OUTPUT ;
    USE SIGNAL ;
    PORT
      LAYER met3 ;
        RECT 199.700 211.670 200.000 211.970 ;
    END
  END rdata[200]

  PIN rdata[199]
    DIRECTION OUTPUT ;
    USE SIGNAL ;
    PORT
      LAYER met3 ;
        RECT 199.700 212.350 200.000 212.650 ;
    END
  END rdata[199]

  PIN rdata[198]
    DIRECTION OUTPUT ;
    USE SIGNAL ;
    PORT
      LAYER met3 ;
        RECT 199.700 213.030 200.000 213.330 ;
    END
  END rdata[198]

  PIN rdata[197]
    DIRECTION OUTPUT ;
    USE SIGNAL ;
    PORT
      LAYER met3 ;
        RECT 199.700 213.710 200.000 214.010 ;
    END
  END rdata[197]

  PIN rdata[196]
    DIRECTION OUTPUT ;
    USE SIGNAL ;
    PORT
      LAYER met3 ;
        RECT 199.700 214.390 200.000 214.690 ;
    END
  END rdata[196]

  PIN rdata[195]
    DIRECTION OUTPUT ;
    USE SIGNAL ;
    PORT
      LAYER met3 ;
        RECT 199.700 215.070 200.000 215.370 ;
    END
  END rdata[195]

  PIN rdata[194]
    DIRECTION OUTPUT ;
    USE SIGNAL ;
    PORT
      LAYER met3 ;
        RECT 199.700 215.750 200.000 216.050 ;
    END
  END rdata[194]

  PIN rdata[193]
    DIRECTION OUTPUT ;
    USE SIGNAL ;
    PORT
      LAYER met3 ;
        RECT 199.700 216.430 200.000 216.730 ;
    END
  END rdata[193]

  PIN rdata[192]
    DIRECTION OUTPUT ;
    USE SIGNAL ;
    PORT
      LAYER met3 ;
        RECT 199.700 217.110 200.000 217.410 ;
    END
  END rdata[192]

  PIN rdata[191]
    DIRECTION OUTPUT ;
    USE SIGNAL ;
    PORT
      LAYER met3 ;
        RECT 199.700 217.790 200.000 218.090 ;
    END
  END rdata[191]

  PIN rdata[190]
    DIRECTION OUTPUT ;
    USE SIGNAL ;
    PORT
      LAYER met3 ;
        RECT 199.700 218.470 200.000 218.770 ;
    END
  END rdata[190]

  PIN rdata[189]
    DIRECTION OUTPUT ;
    USE SIGNAL ;
    PORT
      LAYER met3 ;
        RECT 199.700 219.150 200.000 219.450 ;
    END
  END rdata[189]

  PIN rdata[188]
    DIRECTION OUTPUT ;
    USE SIGNAL ;
    PORT
      LAYER met3 ;
        RECT 199.700 219.830 200.000 220.130 ;
    END
  END rdata[188]

  PIN rdata[187]
    DIRECTION OUTPUT ;
    USE SIGNAL ;
    PORT
      LAYER met3 ;
        RECT 199.700 220.510 200.000 220.810 ;
    END
  END rdata[187]

  PIN rdata[186]
    DIRECTION OUTPUT ;
    USE SIGNAL ;
    PORT
      LAYER met3 ;
        RECT 199.700 221.190 200.000 221.490 ;
    END
  END rdata[186]

  PIN rdata[185]
    DIRECTION OUTPUT ;
    USE SIGNAL ;
    PORT
      LAYER met3 ;
        RECT 199.700 221.870 200.000 222.170 ;
    END
  END rdata[185]

  PIN rdata[184]
    DIRECTION OUTPUT ;
    USE SIGNAL ;
    PORT
      LAYER met3 ;
        RECT 199.700 222.550 200.000 222.850 ;
    END
  END rdata[184]

  PIN rdata[183]
    DIRECTION OUTPUT ;
    USE SIGNAL ;
    PORT
      LAYER met3 ;
        RECT 199.700 223.230 200.000 223.530 ;
    END
  END rdata[183]

  PIN rdata[182]
    DIRECTION OUTPUT ;
    USE SIGNAL ;
    PORT
      LAYER met3 ;
        RECT 199.700 223.910 200.000 224.210 ;
    END
  END rdata[182]

  PIN rdata[181]
    DIRECTION OUTPUT ;
    USE SIGNAL ;
    PORT
      LAYER met3 ;
        RECT 199.700 224.590 200.000 224.890 ;
    END
  END rdata[181]

  PIN rdata[180]
    DIRECTION OUTPUT ;
    USE SIGNAL ;
    PORT
      LAYER met3 ;
        RECT 199.700 225.270 200.000 225.570 ;
    END
  END rdata[180]

  PIN rdata[179]
    DIRECTION OUTPUT ;
    USE SIGNAL ;
    PORT
      LAYER met3 ;
        RECT 199.700 225.950 200.000 226.250 ;
    END
  END rdata[179]

  PIN rdata[178]
    DIRECTION OUTPUT ;
    USE SIGNAL ;
    PORT
      LAYER met3 ;
        RECT 199.700 226.630 200.000 226.930 ;
    END
  END rdata[178]

  PIN rdata[177]
    DIRECTION OUTPUT ;
    USE SIGNAL ;
    PORT
      LAYER met3 ;
        RECT 199.700 227.310 200.000 227.610 ;
    END
  END rdata[177]

  PIN rdata[176]
    DIRECTION OUTPUT ;
    USE SIGNAL ;
    PORT
      LAYER met3 ;
        RECT 199.700 227.990 200.000 228.290 ;
    END
  END rdata[176]

  PIN rdata[175]
    DIRECTION OUTPUT ;
    USE SIGNAL ;
    PORT
      LAYER met3 ;
        RECT 199.700 228.670 200.000 228.970 ;
    END
  END rdata[175]

  PIN rdata[174]
    DIRECTION OUTPUT ;
    USE SIGNAL ;
    PORT
      LAYER met3 ;
        RECT 199.700 229.350 200.000 229.650 ;
    END
  END rdata[174]

  PIN rdata[173]
    DIRECTION OUTPUT ;
    USE SIGNAL ;
    PORT
      LAYER met3 ;
        RECT 199.700 230.030 200.000 230.330 ;
    END
  END rdata[173]

  PIN rdata[172]
    DIRECTION OUTPUT ;
    USE SIGNAL ;
    PORT
      LAYER met3 ;
        RECT 199.700 230.710 200.000 231.010 ;
    END
  END rdata[172]

  PIN rdata[171]
    DIRECTION OUTPUT ;
    USE SIGNAL ;
    PORT
      LAYER met3 ;
        RECT 199.700 231.390 200.000 231.690 ;
    END
  END rdata[171]

  PIN rdata[170]
    DIRECTION OUTPUT ;
    USE SIGNAL ;
    PORT
      LAYER met3 ;
        RECT 199.700 232.070 200.000 232.370 ;
    END
  END rdata[170]

  PIN rdata[169]
    DIRECTION OUTPUT ;
    USE SIGNAL ;
    PORT
      LAYER met3 ;
        RECT 199.700 232.750 200.000 233.050 ;
    END
  END rdata[169]

  PIN rdata[168]
    DIRECTION OUTPUT ;
    USE SIGNAL ;
    PORT
      LAYER met3 ;
        RECT 199.700 233.430 200.000 233.730 ;
    END
  END rdata[168]

  PIN rdata[167]
    DIRECTION OUTPUT ;
    USE SIGNAL ;
    PORT
      LAYER met3 ;
        RECT 199.700 234.110 200.000 234.410 ;
    END
  END rdata[167]

  PIN rdata[166]
    DIRECTION OUTPUT ;
    USE SIGNAL ;
    PORT
      LAYER met3 ;
        RECT 199.700 234.790 200.000 235.090 ;
    END
  END rdata[166]

  PIN rdata[165]
    DIRECTION OUTPUT ;
    USE SIGNAL ;
    PORT
      LAYER met3 ;
        RECT 199.700 235.470 200.000 235.770 ;
    END
  END rdata[165]

  PIN rdata[164]
    DIRECTION OUTPUT ;
    USE SIGNAL ;
    PORT
      LAYER met3 ;
        RECT 199.700 236.150 200.000 236.450 ;
    END
  END rdata[164]

  PIN rdata[163]
    DIRECTION OUTPUT ;
    USE SIGNAL ;
    PORT
      LAYER met3 ;
        RECT 199.700 236.830 200.000 237.130 ;
    END
  END rdata[163]

  PIN rdata[162]
    DIRECTION OUTPUT ;
    USE SIGNAL ;
    PORT
      LAYER met3 ;
        RECT 199.700 237.510 200.000 237.810 ;
    END
  END rdata[162]

  PIN rdata[161]
    DIRECTION OUTPUT ;
    USE SIGNAL ;
    PORT
      LAYER met3 ;
        RECT 199.700 238.190 200.000 238.490 ;
    END
  END rdata[161]

  PIN rdata[160]
    DIRECTION OUTPUT ;
    USE SIGNAL ;
    PORT
      LAYER met3 ;
        RECT 199.700 238.870 200.000 239.170 ;
    END
  END rdata[160]

  PIN rdata[159]
    DIRECTION OUTPUT ;
    USE SIGNAL ;
    PORT
      LAYER met3 ;
        RECT 199.700 239.550 200.000 239.850 ;
    END
  END rdata[159]

  PIN rdata[158]
    DIRECTION OUTPUT ;
    USE SIGNAL ;
    PORT
      LAYER met3 ;
        RECT 199.700 240.230 200.000 240.530 ;
    END
  END rdata[158]

  PIN rdata[157]
    DIRECTION OUTPUT ;
    USE SIGNAL ;
    PORT
      LAYER met3 ;
        RECT 199.700 240.910 200.000 241.210 ;
    END
  END rdata[157]

  PIN rdata[156]
    DIRECTION OUTPUT ;
    USE SIGNAL ;
    PORT
      LAYER met3 ;
        RECT 199.700 241.590 200.000 241.890 ;
    END
  END rdata[156]

  PIN rdata[155]
    DIRECTION OUTPUT ;
    USE SIGNAL ;
    PORT
      LAYER met3 ;
        RECT 199.700 242.270 200.000 242.570 ;
    END
  END rdata[155]

  PIN rdata[154]
    DIRECTION OUTPUT ;
    USE SIGNAL ;
    PORT
      LAYER met3 ;
        RECT 199.700 242.950 200.000 243.250 ;
    END
  END rdata[154]

  PIN rdata[153]
    DIRECTION OUTPUT ;
    USE SIGNAL ;
    PORT
      LAYER met3 ;
        RECT 199.700 243.630 200.000 243.930 ;
    END
  END rdata[153]

  PIN rdata[152]
    DIRECTION OUTPUT ;
    USE SIGNAL ;
    PORT
      LAYER met3 ;
        RECT 199.700 244.310 200.000 244.610 ;
    END
  END rdata[152]

  PIN rdata[151]
    DIRECTION OUTPUT ;
    USE SIGNAL ;
    PORT
      LAYER met3 ;
        RECT 199.700 244.990 200.000 245.290 ;
    END
  END rdata[151]

  PIN rdata[150]
    DIRECTION OUTPUT ;
    USE SIGNAL ;
    PORT
      LAYER met3 ;
        RECT 199.700 245.670 200.000 245.970 ;
    END
  END rdata[150]

  PIN rdata[149]
    DIRECTION OUTPUT ;
    USE SIGNAL ;
    PORT
      LAYER met3 ;
        RECT 199.700 246.350 200.000 246.650 ;
    END
  END rdata[149]

  PIN rdata[148]
    DIRECTION OUTPUT ;
    USE SIGNAL ;
    PORT
      LAYER met3 ;
        RECT 199.700 247.030 200.000 247.330 ;
    END
  END rdata[148]

  PIN rdata[147]
    DIRECTION OUTPUT ;
    USE SIGNAL ;
    PORT
      LAYER met3 ;
        RECT 199.700 247.710 200.000 248.010 ;
    END
  END rdata[147]

  PIN rdata[146]
    DIRECTION OUTPUT ;
    USE SIGNAL ;
    PORT
      LAYER met3 ;
        RECT 199.700 248.390 200.000 248.690 ;
    END
  END rdata[146]

  PIN rdata[145]
    DIRECTION OUTPUT ;
    USE SIGNAL ;
    PORT
      LAYER met3 ;
        RECT 199.700 249.070 200.000 249.370 ;
    END
  END rdata[145]

  PIN rdata[144]
    DIRECTION OUTPUT ;
    USE SIGNAL ;
    PORT
      LAYER met3 ;
        RECT 199.700 249.750 200.000 250.050 ;
    END
  END rdata[144]

  PIN rdata[143]
    DIRECTION OUTPUT ;
    USE SIGNAL ;
    PORT
      LAYER met3 ;
        RECT 199.700 250.430 200.000 250.730 ;
    END
  END rdata[143]

  PIN rdata[142]
    DIRECTION OUTPUT ;
    USE SIGNAL ;
    PORT
      LAYER met3 ;
        RECT 199.700 251.110 200.000 251.410 ;
    END
  END rdata[142]

  PIN rdata[141]
    DIRECTION OUTPUT ;
    USE SIGNAL ;
    PORT
      LAYER met3 ;
        RECT 199.700 251.790 200.000 252.090 ;
    END
  END rdata[141]

  PIN rdata[140]
    DIRECTION OUTPUT ;
    USE SIGNAL ;
    PORT
      LAYER met3 ;
        RECT 199.700 252.470 200.000 252.770 ;
    END
  END rdata[140]

  PIN rdata[139]
    DIRECTION OUTPUT ;
    USE SIGNAL ;
    PORT
      LAYER met3 ;
        RECT 199.700 253.150 200.000 253.450 ;
    END
  END rdata[139]

  PIN rdata[138]
    DIRECTION OUTPUT ;
    USE SIGNAL ;
    PORT
      LAYER met3 ;
        RECT 199.700 253.830 200.000 254.130 ;
    END
  END rdata[138]

  PIN rdata[137]
    DIRECTION OUTPUT ;
    USE SIGNAL ;
    PORT
      LAYER met3 ;
        RECT 199.700 254.510 200.000 254.810 ;
    END
  END rdata[137]

  PIN rdata[136]
    DIRECTION OUTPUT ;
    USE SIGNAL ;
    PORT
      LAYER met3 ;
        RECT 199.700 255.190 200.000 255.490 ;
    END
  END rdata[136]

  PIN rdata[135]
    DIRECTION OUTPUT ;
    USE SIGNAL ;
    PORT
      LAYER met3 ;
        RECT 199.700 255.870 200.000 256.170 ;
    END
  END rdata[135]

  PIN rdata[134]
    DIRECTION OUTPUT ;
    USE SIGNAL ;
    PORT
      LAYER met3 ;
        RECT 199.700 256.550 200.000 256.850 ;
    END
  END rdata[134]

  PIN rdata[133]
    DIRECTION OUTPUT ;
    USE SIGNAL ;
    PORT
      LAYER met3 ;
        RECT 199.700 257.230 200.000 257.530 ;
    END
  END rdata[133]

  PIN rdata[132]
    DIRECTION OUTPUT ;
    USE SIGNAL ;
    PORT
      LAYER met3 ;
        RECT 199.700 257.910 200.000 258.210 ;
    END
  END rdata[132]

  PIN rdata[131]
    DIRECTION OUTPUT ;
    USE SIGNAL ;
    PORT
      LAYER met3 ;
        RECT 199.700 258.590 200.000 258.890 ;
    END
  END rdata[131]

  PIN rdata[130]
    DIRECTION OUTPUT ;
    USE SIGNAL ;
    PORT
      LAYER met3 ;
        RECT 199.700 259.270 200.000 259.570 ;
    END
  END rdata[130]

  PIN rdata[129]
    DIRECTION OUTPUT ;
    USE SIGNAL ;
    PORT
      LAYER met3 ;
        RECT 199.700 259.950 200.000 260.250 ;
    END
  END rdata[129]

  PIN rdata[128]
    DIRECTION OUTPUT ;
    USE SIGNAL ;
    PORT
      LAYER met3 ;
        RECT 199.700 260.630 200.000 260.930 ;
    END
  END rdata[128]

  PIN rdata[127]
    DIRECTION OUTPUT ;
    USE SIGNAL ;
    PORT
      LAYER met3 ;
        RECT 199.700 261.310 200.000 261.610 ;
    END
  END rdata[127]

  PIN rdata[126]
    DIRECTION OUTPUT ;
    USE SIGNAL ;
    PORT
      LAYER met3 ;
        RECT 199.700 261.990 200.000 262.290 ;
    END
  END rdata[126]

  PIN rdata[125]
    DIRECTION OUTPUT ;
    USE SIGNAL ;
    PORT
      LAYER met3 ;
        RECT 199.700 262.670 200.000 262.970 ;
    END
  END rdata[125]

  PIN rdata[124]
    DIRECTION OUTPUT ;
    USE SIGNAL ;
    PORT
      LAYER met3 ;
        RECT 199.700 263.350 200.000 263.650 ;
    END
  END rdata[124]

  PIN rdata[123]
    DIRECTION OUTPUT ;
    USE SIGNAL ;
    PORT
      LAYER met3 ;
        RECT 199.700 264.030 200.000 264.330 ;
    END
  END rdata[123]

  PIN rdata[122]
    DIRECTION OUTPUT ;
    USE SIGNAL ;
    PORT
      LAYER met3 ;
        RECT 199.700 264.710 200.000 265.010 ;
    END
  END rdata[122]

  PIN rdata[121]
    DIRECTION OUTPUT ;
    USE SIGNAL ;
    PORT
      LAYER met3 ;
        RECT 199.700 265.390 200.000 265.690 ;
    END
  END rdata[121]

  PIN rdata[120]
    DIRECTION OUTPUT ;
    USE SIGNAL ;
    PORT
      LAYER met3 ;
        RECT 199.700 266.070 200.000 266.370 ;
    END
  END rdata[120]

  PIN rdata[119]
    DIRECTION OUTPUT ;
    USE SIGNAL ;
    PORT
      LAYER met3 ;
        RECT 199.700 266.750 200.000 267.050 ;
    END
  END rdata[119]

  PIN rdata[118]
    DIRECTION OUTPUT ;
    USE SIGNAL ;
    PORT
      LAYER met3 ;
        RECT 199.700 267.430 200.000 267.730 ;
    END
  END rdata[118]

  PIN rdata[117]
    DIRECTION OUTPUT ;
    USE SIGNAL ;
    PORT
      LAYER met3 ;
        RECT 199.700 268.110 200.000 268.410 ;
    END
  END rdata[117]

  PIN rdata[116]
    DIRECTION OUTPUT ;
    USE SIGNAL ;
    PORT
      LAYER met3 ;
        RECT 199.700 268.790 200.000 269.090 ;
    END
  END rdata[116]

  PIN rdata[115]
    DIRECTION OUTPUT ;
    USE SIGNAL ;
    PORT
      LAYER met3 ;
        RECT 199.700 269.470 200.000 269.770 ;
    END
  END rdata[115]

  PIN rdata[114]
    DIRECTION OUTPUT ;
    USE SIGNAL ;
    PORT
      LAYER met3 ;
        RECT 199.700 270.150 200.000 270.450 ;
    END
  END rdata[114]

  PIN rdata[113]
    DIRECTION OUTPUT ;
    USE SIGNAL ;
    PORT
      LAYER met3 ;
        RECT 199.700 270.830 200.000 271.130 ;
    END
  END rdata[113]

  PIN rdata[112]
    DIRECTION OUTPUT ;
    USE SIGNAL ;
    PORT
      LAYER met3 ;
        RECT 199.700 271.510 200.000 271.810 ;
    END
  END rdata[112]

  PIN rdata[111]
    DIRECTION OUTPUT ;
    USE SIGNAL ;
    PORT
      LAYER met3 ;
        RECT 199.700 272.190 200.000 272.490 ;
    END
  END rdata[111]

  PIN rdata[110]
    DIRECTION OUTPUT ;
    USE SIGNAL ;
    PORT
      LAYER met3 ;
        RECT 199.700 272.870 200.000 273.170 ;
    END
  END rdata[110]

  PIN rdata[109]
    DIRECTION OUTPUT ;
    USE SIGNAL ;
    PORT
      LAYER met3 ;
        RECT 199.700 273.550 200.000 273.850 ;
    END
  END rdata[109]

  PIN rdata[108]
    DIRECTION OUTPUT ;
    USE SIGNAL ;
    PORT
      LAYER met3 ;
        RECT 199.700 274.230 200.000 274.530 ;
    END
  END rdata[108]

  PIN rdata[107]
    DIRECTION OUTPUT ;
    USE SIGNAL ;
    PORT
      LAYER met3 ;
        RECT 199.700 274.910 200.000 275.210 ;
    END
  END rdata[107]

  PIN rdata[106]
    DIRECTION OUTPUT ;
    USE SIGNAL ;
    PORT
      LAYER met3 ;
        RECT 199.700 275.590 200.000 275.890 ;
    END
  END rdata[106]

  PIN rdata[105]
    DIRECTION OUTPUT ;
    USE SIGNAL ;
    PORT
      LAYER met3 ;
        RECT 199.700 276.270 200.000 276.570 ;
    END
  END rdata[105]

  PIN rdata[104]
    DIRECTION OUTPUT ;
    USE SIGNAL ;
    PORT
      LAYER met3 ;
        RECT 199.700 276.950 200.000 277.250 ;
    END
  END rdata[104]

  PIN rdata[103]
    DIRECTION OUTPUT ;
    USE SIGNAL ;
    PORT
      LAYER met3 ;
        RECT 199.700 277.630 200.000 277.930 ;
    END
  END rdata[103]

  PIN rdata[102]
    DIRECTION OUTPUT ;
    USE SIGNAL ;
    PORT
      LAYER met3 ;
        RECT 199.700 278.310 200.000 278.610 ;
    END
  END rdata[102]

  PIN rdata[101]
    DIRECTION OUTPUT ;
    USE SIGNAL ;
    PORT
      LAYER met3 ;
        RECT 199.700 278.990 200.000 279.290 ;
    END
  END rdata[101]

  PIN rdata[100]
    DIRECTION OUTPUT ;
    USE SIGNAL ;
    PORT
      LAYER met3 ;
        RECT 199.700 279.670 200.000 279.970 ;
    END
  END rdata[100]

  PIN rdata[99]
    DIRECTION OUTPUT ;
    USE SIGNAL ;
    PORT
      LAYER met3 ;
        RECT 199.700 280.350 200.000 280.650 ;
    END
  END rdata[99]

  PIN rdata[98]
    DIRECTION OUTPUT ;
    USE SIGNAL ;
    PORT
      LAYER met3 ;
        RECT 199.700 281.030 200.000 281.330 ;
    END
  END rdata[98]

  PIN rdata[97]
    DIRECTION OUTPUT ;
    USE SIGNAL ;
    PORT
      LAYER met3 ;
        RECT 199.700 281.710 200.000 282.010 ;
    END
  END rdata[97]

  PIN rdata[96]
    DIRECTION OUTPUT ;
    USE SIGNAL ;
    PORT
      LAYER met3 ;
        RECT 199.700 282.390 200.000 282.690 ;
    END
  END rdata[96]

  PIN rdata[95]
    DIRECTION OUTPUT ;
    USE SIGNAL ;
    PORT
      LAYER met3 ;
        RECT 199.700 283.070 200.000 283.370 ;
    END
  END rdata[95]

  PIN rdata[94]
    DIRECTION OUTPUT ;
    USE SIGNAL ;
    PORT
      LAYER met3 ;
        RECT 199.700 283.750 200.000 284.050 ;
    END
  END rdata[94]

  PIN rdata[93]
    DIRECTION OUTPUT ;
    USE SIGNAL ;
    PORT
      LAYER met3 ;
        RECT 199.700 284.430 200.000 284.730 ;
    END
  END rdata[93]

  PIN rdata[92]
    DIRECTION OUTPUT ;
    USE SIGNAL ;
    PORT
      LAYER met3 ;
        RECT 199.700 285.110 200.000 285.410 ;
    END
  END rdata[92]

  PIN rdata[91]
    DIRECTION OUTPUT ;
    USE SIGNAL ;
    PORT
      LAYER met3 ;
        RECT 199.700 285.790 200.000 286.090 ;
    END
  END rdata[91]

  PIN rdata[90]
    DIRECTION OUTPUT ;
    USE SIGNAL ;
    PORT
      LAYER met3 ;
        RECT 199.700 286.470 200.000 286.770 ;
    END
  END rdata[90]

  PIN rdata[89]
    DIRECTION OUTPUT ;
    USE SIGNAL ;
    PORT
      LAYER met3 ;
        RECT 199.700 287.150 200.000 287.450 ;
    END
  END rdata[89]

  PIN rdata[88]
    DIRECTION OUTPUT ;
    USE SIGNAL ;
    PORT
      LAYER met3 ;
        RECT 199.700 287.830 200.000 288.130 ;
    END
  END rdata[88]

  PIN rdata[87]
    DIRECTION OUTPUT ;
    USE SIGNAL ;
    PORT
      LAYER met3 ;
        RECT 199.700 288.510 200.000 288.810 ;
    END
  END rdata[87]

  PIN rdata[86]
    DIRECTION OUTPUT ;
    USE SIGNAL ;
    PORT
      LAYER met3 ;
        RECT 199.700 289.190 200.000 289.490 ;
    END
  END rdata[86]

  PIN rdata[85]
    DIRECTION OUTPUT ;
    USE SIGNAL ;
    PORT
      LAYER met3 ;
        RECT 199.700 289.870 200.000 290.170 ;
    END
  END rdata[85]

  PIN rdata[84]
    DIRECTION OUTPUT ;
    USE SIGNAL ;
    PORT
      LAYER met3 ;
        RECT 199.700 290.550 200.000 290.850 ;
    END
  END rdata[84]

  PIN rdata[83]
    DIRECTION OUTPUT ;
    USE SIGNAL ;
    PORT
      LAYER met3 ;
        RECT 199.700 291.230 200.000 291.530 ;
    END
  END rdata[83]

  PIN rdata[82]
    DIRECTION OUTPUT ;
    USE SIGNAL ;
    PORT
      LAYER met3 ;
        RECT 199.700 291.910 200.000 292.210 ;
    END
  END rdata[82]

  PIN rdata[81]
    DIRECTION OUTPUT ;
    USE SIGNAL ;
    PORT
      LAYER met3 ;
        RECT 199.700 292.590 200.000 292.890 ;
    END
  END rdata[81]

  PIN rdata[80]
    DIRECTION OUTPUT ;
    USE SIGNAL ;
    PORT
      LAYER met3 ;
        RECT 199.700 293.270 200.000 293.570 ;
    END
  END rdata[80]

  PIN rdata[79]
    DIRECTION OUTPUT ;
    USE SIGNAL ;
    PORT
      LAYER met3 ;
        RECT 199.700 293.950 200.000 294.250 ;
    END
  END rdata[79]

  PIN rdata[78]
    DIRECTION OUTPUT ;
    USE SIGNAL ;
    PORT
      LAYER met3 ;
        RECT 199.700 294.630 200.000 294.930 ;
    END
  END rdata[78]

  PIN rdata[77]
    DIRECTION OUTPUT ;
    USE SIGNAL ;
    PORT
      LAYER met3 ;
        RECT 199.700 295.310 200.000 295.610 ;
    END
  END rdata[77]

  PIN rdata[76]
    DIRECTION OUTPUT ;
    USE SIGNAL ;
    PORT
      LAYER met3 ;
        RECT 199.700 295.990 200.000 296.290 ;
    END
  END rdata[76]

  PIN rdata[75]
    DIRECTION OUTPUT ;
    USE SIGNAL ;
    PORT
      LAYER met3 ;
        RECT 199.700 296.670 200.000 296.970 ;
    END
  END rdata[75]

  PIN rdata[74]
    DIRECTION OUTPUT ;
    USE SIGNAL ;
    PORT
      LAYER met3 ;
        RECT 199.700 297.350 200.000 297.650 ;
    END
  END rdata[74]

  PIN rdata[73]
    DIRECTION OUTPUT ;
    USE SIGNAL ;
    PORT
      LAYER met3 ;
        RECT 199.700 298.030 200.000 298.330 ;
    END
  END rdata[73]

  PIN rdata[72]
    DIRECTION OUTPUT ;
    USE SIGNAL ;
    PORT
      LAYER met3 ;
        RECT 199.700 298.710 200.000 299.010 ;
    END
  END rdata[72]

  PIN rdata[71]
    DIRECTION OUTPUT ;
    USE SIGNAL ;
    PORT
      LAYER met3 ;
        RECT 199.700 299.390 200.000 299.690 ;
    END
  END rdata[71]

  PIN rdata[70]
    DIRECTION OUTPUT ;
    USE SIGNAL ;
    PORT
      LAYER met3 ;
        RECT 199.700 300.070 200.000 300.370 ;
    END
  END rdata[70]

  PIN rdata[69]
    DIRECTION OUTPUT ;
    USE SIGNAL ;
    PORT
      LAYER met3 ;
        RECT 199.700 300.750 200.000 301.050 ;
    END
  END rdata[69]

  PIN rdata[68]
    DIRECTION OUTPUT ;
    USE SIGNAL ;
    PORT
      LAYER met3 ;
        RECT 199.700 301.430 200.000 301.730 ;
    END
  END rdata[68]

  PIN rdata[67]
    DIRECTION OUTPUT ;
    USE SIGNAL ;
    PORT
      LAYER met3 ;
        RECT 199.700 302.110 200.000 302.410 ;
    END
  END rdata[67]

  PIN rdata[66]
    DIRECTION OUTPUT ;
    USE SIGNAL ;
    PORT
      LAYER met3 ;
        RECT 199.700 302.790 200.000 303.090 ;
    END
  END rdata[66]

  PIN rdata[65]
    DIRECTION OUTPUT ;
    USE SIGNAL ;
    PORT
      LAYER met3 ;
        RECT 199.700 303.470 200.000 303.770 ;
    END
  END rdata[65]

  PIN rdata[64]
    DIRECTION OUTPUT ;
    USE SIGNAL ;
    PORT
      LAYER met3 ;
        RECT 199.700 304.150 200.000 304.450 ;
    END
  END rdata[64]

  PIN rdata[63]
    DIRECTION OUTPUT ;
    USE SIGNAL ;
    PORT
      LAYER met3 ;
        RECT 199.700 304.830 200.000 305.130 ;
    END
  END rdata[63]

  PIN rdata[62]
    DIRECTION OUTPUT ;
    USE SIGNAL ;
    PORT
      LAYER met3 ;
        RECT 199.700 305.510 200.000 305.810 ;
    END
  END rdata[62]

  PIN rdata[61]
    DIRECTION OUTPUT ;
    USE SIGNAL ;
    PORT
      LAYER met3 ;
        RECT 199.700 306.190 200.000 306.490 ;
    END
  END rdata[61]

  PIN rdata[60]
    DIRECTION OUTPUT ;
    USE SIGNAL ;
    PORT
      LAYER met3 ;
        RECT 199.700 306.870 200.000 307.170 ;
    END
  END rdata[60]

  PIN rdata[59]
    DIRECTION OUTPUT ;
    USE SIGNAL ;
    PORT
      LAYER met3 ;
        RECT 199.700 307.550 200.000 307.850 ;
    END
  END rdata[59]

  PIN rdata[58]
    DIRECTION OUTPUT ;
    USE SIGNAL ;
    PORT
      LAYER met3 ;
        RECT 199.700 308.230 200.000 308.530 ;
    END
  END rdata[58]

  PIN rdata[57]
    DIRECTION OUTPUT ;
    USE SIGNAL ;
    PORT
      LAYER met3 ;
        RECT 199.700 308.910 200.000 309.210 ;
    END
  END rdata[57]

  PIN rdata[56]
    DIRECTION OUTPUT ;
    USE SIGNAL ;
    PORT
      LAYER met3 ;
        RECT 199.700 309.590 200.000 309.890 ;
    END
  END rdata[56]

  PIN rdata[55]
    DIRECTION OUTPUT ;
    USE SIGNAL ;
    PORT
      LAYER met3 ;
        RECT 199.700 310.270 200.000 310.570 ;
    END
  END rdata[55]

  PIN rdata[54]
    DIRECTION OUTPUT ;
    USE SIGNAL ;
    PORT
      LAYER met3 ;
        RECT 199.700 310.950 200.000 311.250 ;
    END
  END rdata[54]

  PIN rdata[53]
    DIRECTION OUTPUT ;
    USE SIGNAL ;
    PORT
      LAYER met3 ;
        RECT 199.700 311.630 200.000 311.930 ;
    END
  END rdata[53]

  PIN rdata[52]
    DIRECTION OUTPUT ;
    USE SIGNAL ;
    PORT
      LAYER met3 ;
        RECT 199.700 312.310 200.000 312.610 ;
    END
  END rdata[52]

  PIN rdata[51]
    DIRECTION OUTPUT ;
    USE SIGNAL ;
    PORT
      LAYER met3 ;
        RECT 199.700 312.990 200.000 313.290 ;
    END
  END rdata[51]

  PIN rdata[50]
    DIRECTION OUTPUT ;
    USE SIGNAL ;
    PORT
      LAYER met3 ;
        RECT 199.700 313.670 200.000 313.970 ;
    END
  END rdata[50]

  PIN rdata[49]
    DIRECTION OUTPUT ;
    USE SIGNAL ;
    PORT
      LAYER met3 ;
        RECT 199.700 314.350 200.000 314.650 ;
    END
  END rdata[49]

  PIN rdata[48]
    DIRECTION OUTPUT ;
    USE SIGNAL ;
    PORT
      LAYER met3 ;
        RECT 199.700 315.030 200.000 315.330 ;
    END
  END rdata[48]

  PIN rdata[47]
    DIRECTION OUTPUT ;
    USE SIGNAL ;
    PORT
      LAYER met3 ;
        RECT 199.700 315.710 200.000 316.010 ;
    END
  END rdata[47]

  PIN rdata[46]
    DIRECTION OUTPUT ;
    USE SIGNAL ;
    PORT
      LAYER met3 ;
        RECT 199.700 316.390 200.000 316.690 ;
    END
  END rdata[46]

  PIN rdata[45]
    DIRECTION OUTPUT ;
    USE SIGNAL ;
    PORT
      LAYER met3 ;
        RECT 199.700 317.070 200.000 317.370 ;
    END
  END rdata[45]

  PIN rdata[44]
    DIRECTION OUTPUT ;
    USE SIGNAL ;
    PORT
      LAYER met3 ;
        RECT 199.700 317.750 200.000 318.050 ;
    END
  END rdata[44]

  PIN rdata[43]
    DIRECTION OUTPUT ;
    USE SIGNAL ;
    PORT
      LAYER met3 ;
        RECT 199.700 318.430 200.000 318.730 ;
    END
  END rdata[43]

  PIN rdata[42]
    DIRECTION OUTPUT ;
    USE SIGNAL ;
    PORT
      LAYER met3 ;
        RECT 199.700 319.110 200.000 319.410 ;
    END
  END rdata[42]

  PIN rdata[41]
    DIRECTION OUTPUT ;
    USE SIGNAL ;
    PORT
      LAYER met3 ;
        RECT 199.700 319.790 200.000 320.090 ;
    END
  END rdata[41]

  PIN rdata[40]
    DIRECTION OUTPUT ;
    USE SIGNAL ;
    PORT
      LAYER met3 ;
        RECT 199.700 320.470 200.000 320.770 ;
    END
  END rdata[40]

  PIN rdata[39]
    DIRECTION OUTPUT ;
    USE SIGNAL ;
    PORT
      LAYER met3 ;
        RECT 199.700 321.150 200.000 321.450 ;
    END
  END rdata[39]

  PIN rdata[38]
    DIRECTION OUTPUT ;
    USE SIGNAL ;
    PORT
      LAYER met3 ;
        RECT 199.700 321.830 200.000 322.130 ;
    END
  END rdata[38]

  PIN rdata[37]
    DIRECTION OUTPUT ;
    USE SIGNAL ;
    PORT
      LAYER met3 ;
        RECT 199.700 322.510 200.000 322.810 ;
    END
  END rdata[37]

  PIN rdata[36]
    DIRECTION OUTPUT ;
    USE SIGNAL ;
    PORT
      LAYER met3 ;
        RECT 199.700 323.190 200.000 323.490 ;
    END
  END rdata[36]

  PIN rdata[35]
    DIRECTION OUTPUT ;
    USE SIGNAL ;
    PORT
      LAYER met3 ;
        RECT 199.700 323.870 200.000 324.170 ;
    END
  END rdata[35]

  PIN rdata[34]
    DIRECTION OUTPUT ;
    USE SIGNAL ;
    PORT
      LAYER met3 ;
        RECT 199.700 324.550 200.000 324.850 ;
    END
  END rdata[34]

  PIN rdata[33]
    DIRECTION OUTPUT ;
    USE SIGNAL ;
    PORT
      LAYER met3 ;
        RECT 199.700 325.230 200.000 325.530 ;
    END
  END rdata[33]

  PIN rdata[32]
    DIRECTION OUTPUT ;
    USE SIGNAL ;
    PORT
      LAYER met3 ;
        RECT 199.700 325.910 200.000 326.210 ;
    END
  END rdata[32]

  PIN rdata[31]
    DIRECTION OUTPUT ;
    USE SIGNAL ;
    PORT
      LAYER met3 ;
        RECT 199.700 326.590 200.000 326.890 ;
    END
  END rdata[31]

  PIN rdata[30]
    DIRECTION OUTPUT ;
    USE SIGNAL ;
    PORT
      LAYER met3 ;
        RECT 199.700 327.270 200.000 327.570 ;
    END
  END rdata[30]

  PIN rdata[29]
    DIRECTION OUTPUT ;
    USE SIGNAL ;
    PORT
      LAYER met3 ;
        RECT 199.700 327.950 200.000 328.250 ;
    END
  END rdata[29]

  PIN rdata[28]
    DIRECTION OUTPUT ;
    USE SIGNAL ;
    PORT
      LAYER met3 ;
        RECT 199.700 328.630 200.000 328.930 ;
    END
  END rdata[28]

  PIN rdata[27]
    DIRECTION OUTPUT ;
    USE SIGNAL ;
    PORT
      LAYER met3 ;
        RECT 199.700 329.310 200.000 329.610 ;
    END
  END rdata[27]

  PIN rdata[26]
    DIRECTION OUTPUT ;
    USE SIGNAL ;
    PORT
      LAYER met3 ;
        RECT 199.700 329.990 200.000 330.290 ;
    END
  END rdata[26]

  PIN rdata[25]
    DIRECTION OUTPUT ;
    USE SIGNAL ;
    PORT
      LAYER met3 ;
        RECT 199.700 330.670 200.000 330.970 ;
    END
  END rdata[25]

  PIN rdata[24]
    DIRECTION OUTPUT ;
    USE SIGNAL ;
    PORT
      LAYER met3 ;
        RECT 199.700 331.350 200.000 331.650 ;
    END
  END rdata[24]

  PIN rdata[23]
    DIRECTION OUTPUT ;
    USE SIGNAL ;
    PORT
      LAYER met3 ;
        RECT 199.700 332.030 200.000 332.330 ;
    END
  END rdata[23]

  PIN rdata[22]
    DIRECTION OUTPUT ;
    USE SIGNAL ;
    PORT
      LAYER met3 ;
        RECT 199.700 332.710 200.000 333.010 ;
    END
  END rdata[22]

  PIN rdata[21]
    DIRECTION OUTPUT ;
    USE SIGNAL ;
    PORT
      LAYER met3 ;
        RECT 199.700 333.390 200.000 333.690 ;
    END
  END rdata[21]

  PIN rdata[20]
    DIRECTION OUTPUT ;
    USE SIGNAL ;
    PORT
      LAYER met3 ;
        RECT 199.700 334.070 200.000 334.370 ;
    END
  END rdata[20]

  PIN rdata[19]
    DIRECTION OUTPUT ;
    USE SIGNAL ;
    PORT
      LAYER met3 ;
        RECT 199.700 334.750 200.000 335.050 ;
    END
  END rdata[19]

  PIN rdata[18]
    DIRECTION OUTPUT ;
    USE SIGNAL ;
    PORT
      LAYER met3 ;
        RECT 199.700 335.430 200.000 335.730 ;
    END
  END rdata[18]

  PIN rdata[17]
    DIRECTION OUTPUT ;
    USE SIGNAL ;
    PORT
      LAYER met3 ;
        RECT 199.700 336.110 200.000 336.410 ;
    END
  END rdata[17]

  PIN rdata[16]
    DIRECTION OUTPUT ;
    USE SIGNAL ;
    PORT
      LAYER met3 ;
        RECT 199.700 336.790 200.000 337.090 ;
    END
  END rdata[16]

  PIN rdata[15]
    DIRECTION OUTPUT ;
    USE SIGNAL ;
    PORT
      LAYER met3 ;
        RECT 199.700 337.470 200.000 337.770 ;
    END
  END rdata[15]

  PIN rdata[14]
    DIRECTION OUTPUT ;
    USE SIGNAL ;
    PORT
      LAYER met3 ;
        RECT 199.700 338.150 200.000 338.450 ;
    END
  END rdata[14]

  PIN rdata[13]
    DIRECTION OUTPUT ;
    USE SIGNAL ;
    PORT
      LAYER met3 ;
        RECT 199.700 338.830 200.000 339.130 ;
    END
  END rdata[13]

  PIN rdata[12]
    DIRECTION OUTPUT ;
    USE SIGNAL ;
    PORT
      LAYER met3 ;
        RECT 199.700 339.510 200.000 339.810 ;
    END
  END rdata[12]

  PIN rdata[11]
    DIRECTION OUTPUT ;
    USE SIGNAL ;
    PORT
      LAYER met3 ;
        RECT 199.700 340.190 200.000 340.490 ;
    END
  END rdata[11]

  PIN rdata[10]
    DIRECTION OUTPUT ;
    USE SIGNAL ;
    PORT
      LAYER met3 ;
        RECT 199.700 340.870 200.000 341.170 ;
    END
  END rdata[10]

  PIN rdata[9]
    DIRECTION OUTPUT ;
    USE SIGNAL ;
    PORT
      LAYER met3 ;
        RECT 199.700 341.550 200.000 341.850 ;
    END
  END rdata[9]

  PIN rdata[8]
    DIRECTION OUTPUT ;
    USE SIGNAL ;
    PORT
      LAYER met3 ;
        RECT 199.700 342.230 200.000 342.530 ;
    END
  END rdata[8]

  PIN rdata[7]
    DIRECTION OUTPUT ;
    USE SIGNAL ;
    PORT
      LAYER met3 ;
        RECT 199.700 342.910 200.000 343.210 ;
    END
  END rdata[7]

  PIN rdata[6]
    DIRECTION OUTPUT ;
    USE SIGNAL ;
    PORT
      LAYER met3 ;
        RECT 199.700 343.590 200.000 343.890 ;
    END
  END rdata[6]

  PIN rdata[5]
    DIRECTION OUTPUT ;
    USE SIGNAL ;
    PORT
      LAYER met3 ;
        RECT 199.700 344.270 200.000 344.570 ;
    END
  END rdata[5]

  PIN rdata[4]
    DIRECTION OUTPUT ;
    USE SIGNAL ;
    PORT
      LAYER met3 ;
        RECT 199.700 344.950 200.000 345.250 ;
    END
  END rdata[4]

  PIN rdata[3]
    DIRECTION OUTPUT ;
    USE SIGNAL ;
    PORT
      LAYER met3 ;
        RECT 199.700 345.630 200.000 345.930 ;
    END
  END rdata[3]

  PIN rdata[2]
    DIRECTION OUTPUT ;
    USE SIGNAL ;
    PORT
      LAYER met3 ;
        RECT 199.700 346.310 200.000 346.610 ;
    END
  END rdata[2]

  PIN rdata[1]
    DIRECTION OUTPUT ;
    USE SIGNAL ;
    PORT
      LAYER met3 ;
        RECT 199.700 346.990 200.000 347.290 ;
    END
  END rdata[1]

  PIN rdata[0]
    DIRECTION OUTPUT ;
    USE SIGNAL ;
    PORT
      LAYER met3 ;
        RECT 199.700 347.670 200.000 347.970 ;
    END
  END rdata[0]

  OBS
    LAYER met1 ;
      RECT 0.500 0.500 199.500 353.100 ;
    LAYER met2 ;
      RECT 0.500 0.500 199.500 353.100 ;
  END

END weight_sram

END LIBRARY
